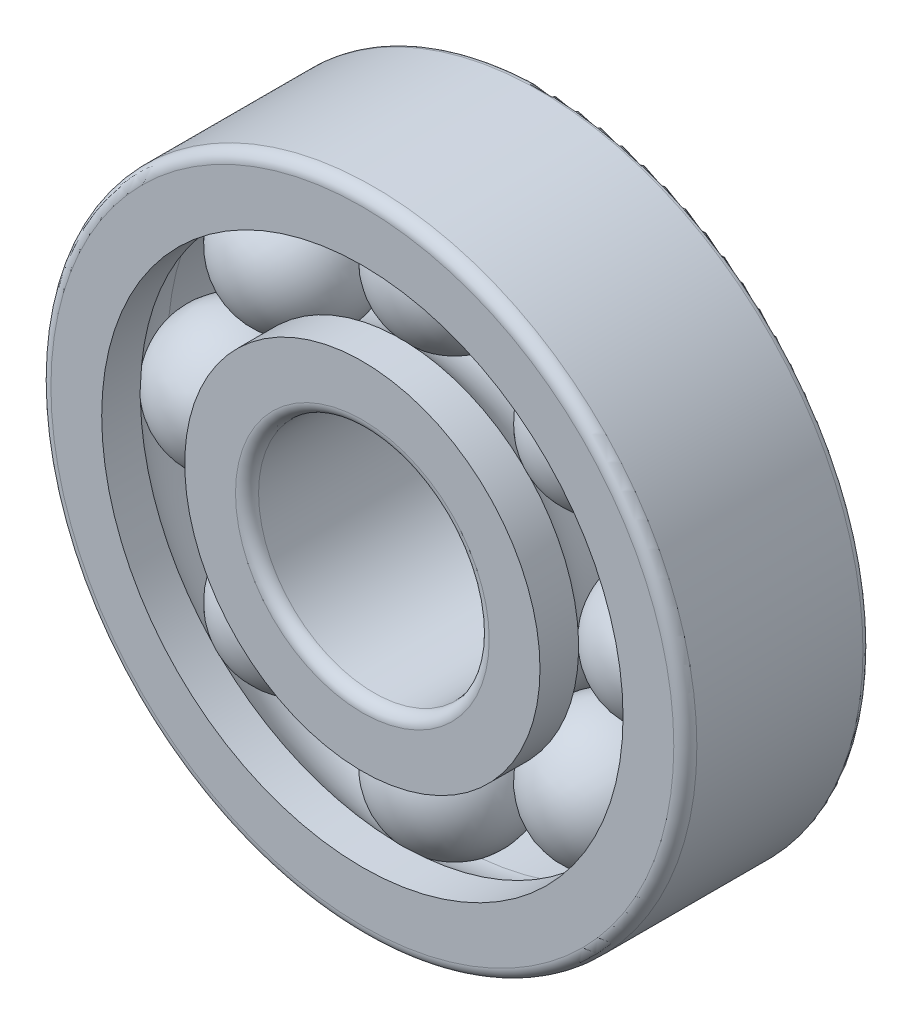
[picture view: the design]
ISO-10303-21;
HEADER;
FILE_DESCRIPTION(('STEP AP214'),'2;1');
FILE_NAME('part.step','',(''),(''),'','','');
FILE_SCHEMA(('AUTOMOTIVE_DESIGN { 1 0 10303 214 1 1 1 1 }'));
ENDSEC;
DATA;
#1=APPLICATION_CONTEXT('core data for automotive mechanical design processes');
#2=APPLICATION_PROTOCOL_DEFINITION('international standard','automotive_design',2000,#1);
#3=PRODUCT_CONTEXT('',#1,'mechanical');
#4=PRODUCT('Part','Part','',(#3));
#5=PRODUCT_RELATED_PRODUCT_CATEGORY('part','',(#4));
#6=PRODUCT_DEFINITION_FORMATION('','',#4);
#7=PRODUCT_DEFINITION_CONTEXT('part definition',#1,'design');
#8=PRODUCT_DEFINITION('design','',#6,#7);
#9=PRODUCT_DEFINITION_SHAPE('','',#8);
#10=(LENGTH_UNIT() NAMED_UNIT(*) SI_UNIT(.MILLI.,.METRE.));
#11=(NAMED_UNIT(*) PLANE_ANGLE_UNIT() SI_UNIT($,.RADIAN.));
#12=(NAMED_UNIT(*) SI_UNIT($,.STERADIAN.) SOLID_ANGLE_UNIT());
#13=UNCERTAINTY_MEASURE_WITH_UNIT(LENGTH_MEASURE(1.E-05),#10,'distance_accuracy_value','');
#14=(GEOMETRIC_REPRESENTATION_CONTEXT(3) GLOBAL_UNCERTAINTY_ASSIGNED_CONTEXT((#13)) GLOBAL_UNIT_ASSIGNED_CONTEXT((#10,
#11,#12)) REPRESENTATION_CONTEXT('',''));
#15=CARTESIAN_POINT('',(0.,0.,0.));
#16=DIRECTION('',(0.,0.,1.));
#17=DIRECTION('',(1.,0.,0.));
#18=AXIS2_PLACEMENT_3D('',#15,#16,#17);
#19=CARTESIAN_POINT('',(0.,0.,0.));
#20=DIRECTION('',(0.,0.,1.));
#21=DIRECTION('',(1.,0.,0.));
#22=AXIS2_PLACEMENT_3D('',#19,#20,#21);
#23=TOROIDAL_SURFACE('',#22,9.5,2.94);
#24=CARTESIAN_POINT('',(0.,0.,2.32456447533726));
#25=DIRECTION('',(0.,0.,1.));
#26=DIRECTION('',(1.,0.,0.));
#27=AXIS2_PLACEMENT_3D('',#24,#25,#26);
#28=CIRCLE('',#27,11.3);
#29=CARTESIAN_POINT('',(-0.264670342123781,11.2969,2.32456447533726));
#30=VERTEX_POINT('',#29);
#31=CARTESIAN_POINT('',(-7.80096440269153,8.17526479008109,2.32456447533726));
#32=VERTEX_POINT('',#31);
#33=EDGE_CURVE('E258',#30,#32,#28,.T.);
#34=ORIENTED_EDGE('',*,*,#33,.T.);
#35=CARTESIAN_POINT('',(-8.59785136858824,8.9905812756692,-0.0002));
#36=CARTESIAN_POINT('',(-8.59786091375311,8.99059098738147,0.0824851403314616));
#37=CARTESIAN_POINT('',(-8.59542029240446,8.98809530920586,0.165166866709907));
#38=CARTESIAN_POINT('',(-8.58568181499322,8.97813688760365,0.329940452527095));
#39=CARTESIAN_POINT('',(-8.57838412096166,8.97067430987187,0.412032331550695));
#40=CARTESIAN_POINT('',(-8.55898133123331,8.95083269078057,0.57499217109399));
#41=CARTESIAN_POINT('',(-8.5468795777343,8.93845706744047,0.655860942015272));
#42=CARTESIAN_POINT('',(-8.51796677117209,8.90888896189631,0.815832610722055));
#43=CARTESIAN_POINT('',(-8.50115585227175,8.89169661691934,0.894935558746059));
#44=CARTESIAN_POINT('',(-8.44378919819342,8.83302595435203,1.12887100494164));
#45=CARTESIAN_POINT('',(-8.39629702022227,8.7844514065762,1.2803513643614));
#46=CARTESIAN_POINT('',(-8.28425024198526,8.66983603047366,1.56959083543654));
#47=CARTESIAN_POINT('',(-8.21970879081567,8.60380866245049,1.70736040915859));
#48=CARTESIAN_POINT('',(-8.09678328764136,8.4780320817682,1.92723825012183));
#49=CARTESIAN_POINT('',(-8.04221252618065,8.42219015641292,2.01376675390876));
#50=CARTESIAN_POINT('',(-7.92635085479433,8.30361390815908,2.17693738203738));
#51=CARTESIAN_POINT('',(-7.86506421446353,8.2408839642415,2.2535857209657));
#52=CARTESIAN_POINT('',(-7.80078388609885,8.17507999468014,2.32476447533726));
#53=B_SPLINE_CURVE_WITH_KNOTS('',3,(#35,#36,#37,#38,#39,#40,#41,#42,#43,#44,#45,#46,#47,#48,#49,
#50,#51,#52),.UNSPECIFIED.,.F.,.F.,(4,2,2,2,2,2,2,2,4),(0.,0.24797496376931,0.495941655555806,
0.743736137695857,0.991523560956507,1.4870345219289,1.98216443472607,2.33102949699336,
2.67967404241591),.UNSPECIFIED.);
#54=CARTESIAN_POINT('',(-8.59785137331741,8.99058128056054,0.));
#55=VERTEX_POINT('',#54);
#56=EDGE_CURVE('E241',#55,#32,#53,.T.);
#57=ORIENTED_EDGE('',*,*,#56,.F.);
#58=CARTESIAN_POINT('',(0.,0.,0.));
#59=DIRECTION('',(0.,0.,1.));
#60=DIRECTION('',(1.,0.,0.));
#61=AXIS2_PLACEMENT_3D('',#58,#59,#60);
#62=CIRCLE('',#61,12.44);
#63=CARTESIAN_POINT('',(-0.277701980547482,12.4369,0.));
#64=VERTEX_POINT('',#63);
#65=EDGE_CURVE('E274',#64,#55,#62,.T.);
#66=ORIENTED_EDGE('',*,*,#65,.F.);
#67=CARTESIAN_POINT('',(-0.264667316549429,11.2966416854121,2.32476447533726));
#68=CARTESIAN_POINT('',(-0.265433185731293,11.3620290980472,2.27415420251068));
#69=CARTESIAN_POINT('',(-0.266170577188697,11.4252687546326,2.22077514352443));
#70=CARTESIAN_POINT('',(-0.267584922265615,11.5470290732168,2.10888477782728));
#71=CARTESIAN_POINT('',(-0.268261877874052,11.6055498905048,2.050373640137));
#72=CARTESIAN_POINT('',(-0.269551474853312,11.7174148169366,1.92866304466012));
#73=CARTESIAN_POINT('',(-0.270164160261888,11.7707624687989,1.86546684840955));
#74=CARTESIAN_POINT('',(-0.271322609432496,11.8719376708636,1.73482862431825));
#75=CARTESIAN_POINT('',(-0.271868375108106,11.9197653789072,1.66738671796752));
#76=CARTESIAN_POINT('',(-0.273401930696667,12.0545086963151,1.45928173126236));
#77=CARTESIAN_POINT('',(-0.27428614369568,12.1326988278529,1.31282376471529));
#78=CARTESIAN_POINT('',(-0.275758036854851,12.2632799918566,1.00899965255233));
#79=CARTESIAN_POINT('',(-0.276345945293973,12.3156908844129,0.851642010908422));
#80=CARTESIAN_POINT('',(-0.277087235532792,12.3818760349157,0.577980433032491));
#81=CARTESIAN_POINT('',(-0.277317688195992,12.4024912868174,0.463288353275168));
#82=CARTESIAN_POINT('',(-0.27762513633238,12.4300152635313,0.232345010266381));
#83=CARTESIAN_POINT('',(-0.277702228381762,12.4369326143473,0.11609477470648));
#84=CARTESIAN_POINT('',(-0.277701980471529,12.4368999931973,-0.000199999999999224));
#85=B_SPLINE_CURVE_WITH_KNOTS('',3,(#67,#68,#69,#70,#71,#72,#73,#74,#75,#76,#77,#78,#79,#80,#81,
#82,#83,#84),.UNSPECIFIED.,.F.,.F.,(4,2,2,2,2,2,2,2,4),(0.,0.247987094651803,0.495966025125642,
0.743773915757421,0.991574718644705,1.4871135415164,1.9822700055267,2.33108183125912,
2.67967392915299),.UNSPECIFIED.);
#86=EDGE_CURVE('E264',#30,#64,#85,.T.);
#87=ORIENTED_EDGE('',*,*,#86,.F.);
#88=EDGE_LOOP('',(#34,#57,#66,#87));
#89=FACE_BOUND('',#88,.T.);
#90=ADVANCED_FACE('F34',(#89),#23,.F.);
#91=CARTESIAN_POINT('',(0.,0.,0.));
#92=DIRECTION('',(0.,0.,1.));
#93=DIRECTION('',(1.,0.,0.));
#94=AXIS2_PLACEMENT_3D('',#91,#92,#93);
#95=TOROIDAL_SURFACE('',#94,9.5,2.94);
#96=CARTESIAN_POINT('',(0.,0.,2.32456447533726));
#97=DIRECTION('',(0.,0.,1.));
#98=DIRECTION('',(1.,0.,0.));
#99=AXIS2_PLACEMENT_3D('',#96,#97,#98);
#100=CIRCLE('',#99,7.7);
#101=CARTESIAN_POINT('',(-5.59701382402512,5.28804654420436,2.32456447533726));
#102=VERTEX_POINT('',#101);
#103=CARTESIAN_POINT('',(-7.6969,0.21847285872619,2.32456447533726));
#104=VERTEX_POINT('',#103);
#105=EDGE_CURVE('E305',#102,#104,#100,.T.);
#106=ORIENTED_EDGE('',*,*,#105,.F.);
#107=CARTESIAN_POINT('',(-5.59719907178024,5.28822660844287,-2.32476447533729));
#108=CARTESIAN_POINT('',(-5.55030713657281,5.24264670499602,-2.27415407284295));
#109=CARTESIAN_POINT('',(-5.50495120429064,5.19856819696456,-2.22077502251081));
#110=CARTESIAN_POINT('',(-5.417617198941,5.11370815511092,-2.10888540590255));
#111=CARTESIAN_POINT('',(-5.37563896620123,5.07292646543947,-2.05037508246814));
#112=CARTESIAN_POINT('',(-5.29538898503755,4.99497636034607,-1.92866518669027));
#113=CARTESIAN_POINT('',(-5.2571147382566,4.95780550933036,-1.86546882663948));
#114=CARTESIAN_POINT('',(-5.18452081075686,4.8873147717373,-1.73483020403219));
#115=CARTESIAN_POINT('',(-5.15020108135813,4.85399483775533,-1.66738799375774));
#116=CARTESIAN_POINT('',(-5.05352345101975,4.76014612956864,-1.45931209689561));
#117=CARTESIAN_POINT('',(-4.99741517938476,4.70569744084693,-1.31288063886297));
#118=CARTESIAN_POINT('',(-4.90367911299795,4.614750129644,-1.00908566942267));
#119=CARTESIAN_POINT('',(-4.8660464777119,4.578246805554,-0.851725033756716));
#120=CARTESIAN_POINT('',(-4.81027119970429,4.52415007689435,-0.530443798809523));
#121=CARTESIAN_POINT('',(-4.79212516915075,4.50655338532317,-0.366524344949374));
#122=CARTESIAN_POINT('',(-4.77584458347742,4.49076552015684,-0.0366933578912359));
#123=CARTESIAN_POINT('',(-4.77771919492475,4.49258323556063,0.129219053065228));
#124=CARTESIAN_POINT('',(-4.80143983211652,4.51558639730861,0.458305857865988));
#125=CARTESIAN_POINT('',(-4.82329472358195,4.53678044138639,0.621479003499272));
#126=CARTESIAN_POINT('',(-4.88635256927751,4.59794384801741,0.940223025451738));
#127=CARTESIAN_POINT('',(-4.92752699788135,4.63788552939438,1.09580473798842));
#128=CARTESIAN_POINT('',(-5.0051179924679,4.71317439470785,1.32701813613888));
#129=CARTESIAN_POINT('',(-5.03521272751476,4.74237952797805,1.40688828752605));
#130=CARTESIAN_POINT('',(-5.10053105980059,4.8057771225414,1.56244542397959));
#131=CARTESIAN_POINT('',(-5.13575390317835,4.83996885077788,1.63813302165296));
#132=CARTESIAN_POINT('',(-5.22336373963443,4.92502886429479,1.80867878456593));
#133=CARTESIAN_POINT('',(-5.27759567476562,4.97769294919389,1.90170534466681));
#134=CARTESIAN_POINT('',(-5.39374990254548,5.09051839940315,2.07781658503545));
#135=CARTESIAN_POINT('',(-5.45566783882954,5.15067551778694,2.16090684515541));
#136=CARTESIAN_POINT('',(-5.5458769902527,5.23834308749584,2.26802026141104));
#137=CARTESIAN_POINT('',(-5.57130760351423,5.26305959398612,2.29681885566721));
#138=CARTESIAN_POINT('',(-5.59719907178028,5.28822660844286,2.32476447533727));
#139=B_SPLINE_CURVE_WITH_KNOTS('',3,(#107,#108,#109,#110,#111,#112,#113,#114,#115,#116,#117,
#118,#119,#120,#121,#122,#123,#124,#125,#126,#127,#128,#129,#130,#131,#132,#133,#134,#135,#136,
#137,#138),.UNSPECIFIED.,.F.,.F.,(4,2,2,2,2,2,2,2,2,2,2,2,2,2,2,4),(0.,0.247992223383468,
0.495972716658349,0.743784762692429,0.991593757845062,1.48701674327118,1.98230986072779,
2.47751685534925,2.97295059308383,3.46860427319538,3.96352840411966,4.23382992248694,
4.50409174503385,4.86279314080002,5.22129214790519,5.35828916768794),.UNSPECIFIED.);
#140=CARTESIAN_POINT('',(-5.59701382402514,5.28804654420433,-2.32456447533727));
#141=VERTEX_POINT('',#140);
#142=EDGE_CURVE('E57',#141,#102,#139,.T.);
#143=ORIENTED_EDGE('',*,*,#142,.F.);
#144=CARTESIAN_POINT('',(0.,0.,-2.32456447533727));
#145=DIRECTION('',(0.,0.,1.));
#146=DIRECTION('',(1.,0.,0.));
#147=AXIS2_PLACEMENT_3D('',#144,#145,#146);
#148=CIRCLE('',#147,7.7);
#149=CARTESIAN_POINT('',(-7.6969,0.218472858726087,-2.32456447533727));
#150=VERTEX_POINT('',#149);
#151=EDGE_CURVE('E300',#141,#150,#148,.T.);
#152=ORIENTED_EDGE('',*,*,#151,.T.);
#153=CARTESIAN_POINT('',(-7.69715831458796,0.218476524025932,2.32476447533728));
#154=CARTESIAN_POINT('',(-7.63177085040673,0.217548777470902,2.27415407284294));
#155=CARTESIAN_POINT('',(-7.56853115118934,0.216645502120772,2.2207750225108));
#156=CARTESIAN_POINT('',(-7.44677157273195,0.214896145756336,2.10888540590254));
#157=CARTESIAN_POINT('',(-7.38825147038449,0.214050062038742,2.05037508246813));
#158=CARTESIAN_POINT('',(-7.27638711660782,0.212423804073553,1.92866518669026));
#159=CARTESIAN_POINT('',(-7.22303937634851,0.211643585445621,1.86546882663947));
#160=CARTESIAN_POINT('',(-7.12186323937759,0.210156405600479,1.73483020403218));
#161=CARTESIAN_POINT('',(-7.07403477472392,0.209449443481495,1.66738799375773));
#162=CARTESIAN_POINT('',(-6.9393123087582,0.207449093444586,1.4593120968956));
#163=CARTESIAN_POINT('',(-6.8611367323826,0.206275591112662,1.31288063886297));
#164=CARTESIAN_POINT('',(-6.73054586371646,0.204303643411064,1.00908566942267));
#165=CARTESIAN_POINT('',(-6.67812382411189,0.203505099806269,0.851725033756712));
#166=CARTESIAN_POINT('',(-6.60043258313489,0.202318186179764,0.530443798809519));
#167=CARTESIAN_POINT('',(-6.57515866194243,0.201929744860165,0.36652434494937));
#168=CARTESIAN_POINT('',(-6.55248284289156,0.201581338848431,0.0366933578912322));
#169=CARTESIAN_POINT('',(-6.55509371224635,0.20162157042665,-0.129219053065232));
#170=CARTESIAN_POINT('',(-6.58813242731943,0.202128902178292,-0.458305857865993));
#171=CARTESIAN_POINT('',(-6.61857262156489,0.202596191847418,-0.621479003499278));
#172=CARTESIAN_POINT('',(-6.7064103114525,0.203935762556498,-0.940223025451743));
#173=CARTESIAN_POINT('',(-6.76376806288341,0.204807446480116,-1.09580473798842));
#174=CARTESIAN_POINT('',(-6.87187044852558,0.206435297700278,-1.32701813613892));
#175=CARTESIAN_POINT('',(-6.91380178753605,0.207064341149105,-1.40688828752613));
#176=CARTESIAN_POINT('',(-7.00481769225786,0.208422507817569,-1.56244542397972));
#177=CARTESIAN_POINT('',(-7.05390120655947,0.209151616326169,-1.63813302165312));
#178=CARTESIAN_POINT('',(-7.1759972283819,0.210954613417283,-1.80867878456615));
#179=CARTESIAN_POINT('',(-7.2515841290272,0.212063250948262,-1.90170534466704));
#180=CARTESIAN_POINT('',(-7.41349721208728,0.214417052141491,-2.07781658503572));
#181=CARTESIAN_POINT('',(-7.49981731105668,0.215662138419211,-2.1609068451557));
#182=CARTESIAN_POINT('',(-7.62559514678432,0.217459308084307,-2.26802026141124));
#183=CARTESIAN_POINT('',(-7.66105451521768,0.217964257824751,-2.29681885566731));
#184=CARTESIAN_POINT('',(-7.69715831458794,0.218476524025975,-2.32476447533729));
#185=B_SPLINE_CURVE_WITH_KNOTS('',3,(#153,#154,#155,#156,#157,#158,#159,#160,#161,#162,#163,
#164,#165,#166,#167,#168,#169,#170,#171,#172,#173,#174,#175,#176,#177,#178,#179,#180,#181,#182,
#183,#184),.UNSPECIFIED.,.F.,.F.,(4,2,2,2,2,2,2,2,2,2,2,2,2,2,2,4),(0.,0.247992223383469,
0.495972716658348,0.743784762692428,0.991593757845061,1.48701674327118,1.98230986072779,
2.47751685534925,2.97295059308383,3.46860427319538,3.96352840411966,4.23382992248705,
4.50409174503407,4.86279314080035,5.22129214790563,5.35828916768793),.UNSPECIFIED.);
#186=EDGE_CURVE('E669',#104,#150,#185,.T.);
#187=ORIENTED_EDGE('',*,*,#186,.F.);
#188=EDGE_LOOP('',(#106,#143,#152,#187));
#189=FACE_BOUND('',#188,.T.);
#190=ADVANCED_FACE('F445',(#189),#95,.F.);
#191=CARTESIAN_POINT('',(-8.99058128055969,8.59785137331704,0.));
#192=VERTEX_POINT('',#191);
#193=CARTESIAN_POINT('',(-12.4369,0.277701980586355,0.));
#194=VERTEX_POINT('',#193);
#195=EDGE_CURVE('E280',#192,#194,#62,.T.);
#196=ORIENTED_EDGE('',*,*,#195,.F.);
#197=CARTESIAN_POINT('',(-8.17507999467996,7.80078388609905,2.32476447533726));
#198=CARTESIAN_POINT('',(-8.22185742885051,7.84647821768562,2.27415420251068));
#199=CARTESIAN_POINT('',(-8.26709603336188,7.89067399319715,2.22077514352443));
#200=CARTESIAN_POINT('',(-8.35419367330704,7.97577144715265,2.10888477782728));
#201=CARTESIAN_POINT('',(-8.39605281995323,8.01667323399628,2.050373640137));
#202=CARTESIAN_POINT('',(-8.47606515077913,8.09486179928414,1.92866304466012));
#203=CARTESIAN_POINT('',(-8.51422087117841,8.13215105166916,1.86546684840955));
#204=CARTESIAN_POINT('',(-8.58658168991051,8.20287357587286,1.73482862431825));
#205=CARTESIAN_POINT('',(-8.62078690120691,8.23630695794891,1.66738671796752));
#206=CARTESIAN_POINT('',(-8.71714920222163,8.3305004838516,1.45928173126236));
#207=CARTESIAN_POINT('',(-8.77306320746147,8.38516402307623,1.31282376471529));
#208=CARTESIAN_POINT('',(-8.86643881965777,8.47645806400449,1.00899965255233));
#209=CARTESIAN_POINT('',(-8.90391463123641,8.51310244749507,0.851642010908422));
#210=CARTESIAN_POINT('',(-8.95123877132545,8.55937824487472,0.577980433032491));
#211=CARTESIAN_POINT('',(-8.96597891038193,8.57379247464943,0.463288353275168));
#212=CARTESIAN_POINT('',(-8.98565869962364,8.59303746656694,0.232345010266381));
#213=CARTESIAN_POINT('',(-8.99060451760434,8.59787425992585,0.116094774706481));
#214=CARTESIAN_POINT('',(-8.99058127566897,8.59785136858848,-0.000199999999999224));
#215=B_SPLINE_CURVE_WITH_KNOTS('',3,(#197,#198,#199,#200,#201,#202,#203,#204,#205,#206,#207,
#208,#209,#210,#211,#212,#213,#214),.UNSPECIFIED.,.F.,.F.,(4,2,2,2,2,2,2,2,4),(0.,
0.247987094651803,0.495966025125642,0.743773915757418,0.991574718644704,1.4871135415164,
1.9822700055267,2.33108183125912,2.67967392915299),.UNSPECIFIED.);
#216=CARTESIAN_POINT('',(-8.17526479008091,7.80096440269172,2.32456447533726));
#217=VERTEX_POINT('',#216);
#218=EDGE_CURVE('E49',#217,#192,#215,.T.);
#219=ORIENTED_EDGE('',*,*,#218,.F.);
#220=CARTESIAN_POINT('',(-11.2969,0.264670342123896,2.32456447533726));
#221=VERTEX_POINT('',#220);
#222=EDGE_CURVE('E261',#217,#221,#28,.T.);
#223=ORIENTED_EDGE('',*,*,#222,.T.);
#224=CARTESIAN_POINT('',(-12.4368999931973,0.277701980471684,-0.0002));
#225=CARTESIAN_POINT('',(-12.4369136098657,0.277702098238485,0.082485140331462));
#226=CARTESIAN_POINT('',(-12.4334231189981,0.277663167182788,0.165166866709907));
#227=CARTESIAN_POINT('',(-12.4194953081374,0.277507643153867,0.329940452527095));
#228=CARTESIAN_POINT('',(-12.4090582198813,0.277391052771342,0.412032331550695));
#229=CARTESIAN_POINT('',(-12.3813082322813,0.277080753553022,0.57499217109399));
#230=CARTESIAN_POINT('',(-12.3640001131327,0.276887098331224,0.655860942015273));
#231=CARTESIAN_POINT('',(-12.3226478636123,0.276423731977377,0.815832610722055));
#232=CARTESIAN_POINT('',(-12.2986039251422,0.276154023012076,0.894935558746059));
#233=CARTESIAN_POINT('',(-12.2165531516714,0.275231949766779,1.12887100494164));
#234=CARTESIAN_POINT('',(-12.1486237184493,0.274466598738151,1.2803513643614));
#235=CARTESIAN_POINT('',(-11.9883493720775,0.272650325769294,1.56959083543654));
#236=CARTESIAN_POINT('',(-11.8960232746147,0.271599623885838,1.70736040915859));
#237=CARTESIAN_POINT('',(-11.7201643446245,0.269583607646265,1.92723825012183));
#238=CARTESIAN_POINT('',(-11.6420907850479,0.26868475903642,2.01376675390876));
#239=CARTESIAN_POINT('',(-11.4763181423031,0.26676526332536,2.17693738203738));
#240=CARTESIAN_POINT('',(-11.3886251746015,0.265744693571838,2.2535857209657));
#241=CARTESIAN_POINT('',(-11.2966416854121,0.264667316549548,2.32476447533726));
#242=B_SPLINE_CURVE_WITH_KNOTS('',3,(#224,#225,#226,#227,#228,#229,#230,#231,#232,#233,#234,
#235,#236,#237,#238,#239,#240,#241),.UNSPECIFIED.,.F.,.F.,(4,2,2,2,2,2,2,2,4),(0.,
0.24797496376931,0.495941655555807,0.743736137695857,0.991523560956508,1.4870345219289,
1.98216443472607,2.33102949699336,2.67967404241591),.UNSPECIFIED.);
#243=EDGE_CURVE('E676',#194,#221,#242,.T.);
#244=ORIENTED_EDGE('',*,*,#243,.F.);
#245=EDGE_LOOP('',(#196,#219,#223,#244));
#246=FACE_BOUND('',#245,.T.);
#247=ADVANCED_FACE('F446',(#246),#23,.F.);
#248=CARTESIAN_POINT('',(-7.6969,-0.218472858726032,2.32456447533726));
#249=VERTEX_POINT('',#248);
#250=CARTESIAN_POINT('',(-5.59701382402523,-5.28804654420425,2.32456447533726));
#251=VERTEX_POINT('',#250);
#252=EDGE_CURVE('E656',#249,#251,#100,.T.);
#253=ORIENTED_EDGE('',*,*,#252,.F.);
#254=CARTESIAN_POINT('',(-7.69715831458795,-0.218476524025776,-2.32476447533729));
#255=CARTESIAN_POINT('',(-7.63177085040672,-0.217548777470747,-2.27415407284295));
#256=CARTESIAN_POINT('',(-7.56853115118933,-0.216645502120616,-2.22077502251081));
#257=CARTESIAN_POINT('',(-7.44677157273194,-0.214896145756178,-2.10888540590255));
#258=CARTESIAN_POINT('',(-7.38825147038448,-0.214050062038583,-2.05037508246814));
#259=CARTESIAN_POINT('',(-7.27638711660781,-0.212423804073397,-1.92866518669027));
#260=CARTESIAN_POINT('',(-7.2230393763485,-0.211643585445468,-1.86546882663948));
#261=CARTESIAN_POINT('',(-7.12186323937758,-0.210156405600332,-1.73483020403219));
#262=CARTESIAN_POINT('',(-7.07403477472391,-0.209449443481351,-1.66738799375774));
#263=CARTESIAN_POINT('',(-6.93931230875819,-0.207449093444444,-1.45931209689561));
#264=CARTESIAN_POINT('',(-6.8611367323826,-0.206275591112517,-1.31288063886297));
#265=CARTESIAN_POINT('',(-6.73054586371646,-0.204303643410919,-1.00908566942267));
#266=CARTESIAN_POINT('',(-6.67812382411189,-0.203505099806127,-0.851725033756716));
#267=CARTESIAN_POINT('',(-6.60043258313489,-0.202318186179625,-0.530443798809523));
#268=CARTESIAN_POINT('',(-6.57515866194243,-0.201929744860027,-0.366524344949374));
#269=CARTESIAN_POINT('',(-6.55248284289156,-0.201581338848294,-0.0366933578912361));
#270=CARTESIAN_POINT('',(-6.55509371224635,-0.201621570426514,0.129219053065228));
#271=CARTESIAN_POINT('',(-6.58813242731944,-0.202128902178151,0.458305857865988));
#272=CARTESIAN_POINT('',(-6.6185726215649,-0.202596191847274,0.621479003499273));
#273=CARTESIAN_POINT('',(-6.70641031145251,-0.203935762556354,0.940223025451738));
#274=CARTESIAN_POINT('',(-6.76376806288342,-0.204807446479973,1.09580473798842));
#275=CARTESIAN_POINT('',(-6.87187044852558,-0.206435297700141,1.32701813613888));
#276=CARTESIAN_POINT('',(-6.91380178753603,-0.20706434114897,1.40688828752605));
#277=CARTESIAN_POINT('',(-7.0048176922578,-0.208422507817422,1.56244542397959));
#278=CARTESIAN_POINT('',(-7.05390120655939,-0.209151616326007,1.63813302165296));
#279=CARTESIAN_POINT('',(-7.17599722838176,-0.210954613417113,1.80867878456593));
#280=CARTESIAN_POINT('',(-7.25158412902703,-0.212063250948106,1.90170534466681));
#281=CARTESIAN_POINT('',(-7.41349721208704,-0.214417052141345,2.07781658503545));
#282=CARTESIAN_POINT('',(-7.49981731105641,-0.21566213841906,2.16090684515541));
#283=CARTESIAN_POINT('',(-7.62559514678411,-0.217459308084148,2.26802026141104));
#284=CARTESIAN_POINT('',(-7.66105451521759,-0.217964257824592,2.29681885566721));
#285=CARTESIAN_POINT('',(-7.69715831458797,-0.218476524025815,2.32476447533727));
#286=B_SPLINE_CURVE_WITH_KNOTS('',3,(#254,#255,#256,#257,#258,#259,#260,#261,#262,#263,#264,
#265,#266,#267,#268,#269,#270,#271,#272,#273,#274,#275,#276,#277,#278,#279,#280,#281,#282,#283,
#284,#285),.UNSPECIFIED.,.F.,.F.,(4,2,2,2,2,2,2,2,2,2,2,2,2,2,2,4),(0.,0.247992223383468,
0.495972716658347,0.743784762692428,0.991593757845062,1.48701674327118,1.98230986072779,
2.47751685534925,2.97295059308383,3.46860427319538,3.96352840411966,4.23382992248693,
4.50409174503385,4.86279314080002,5.22129214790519,5.35828916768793),.UNSPECIFIED.);
#287=CARTESIAN_POINT('',(-7.6969,-0.21847285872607,-2.32456447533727));
#288=VERTEX_POINT('',#287);
#289=EDGE_CURVE('E672',#288,#249,#286,.T.);
#290=ORIENTED_EDGE('',*,*,#289,.F.);
#291=CARTESIAN_POINT('',(-5.59701382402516,-5.28804654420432,-2.32456447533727));
#292=VERTEX_POINT('',#291);
#293=EDGE_CURVE('E934',#288,#292,#148,.T.);
#294=ORIENTED_EDGE('',*,*,#293,.T.);
#295=CARTESIAN_POINT('',(-5.59719907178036,-5.28822660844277,2.32476447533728));
#296=CARTESIAN_POINT('',(-5.55030713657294,-5.24264670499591,2.27415407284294));
#297=CARTESIAN_POINT('',(-5.50495120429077,-5.19856819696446,2.2207750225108));
#298=CARTESIAN_POINT('',(-5.41761719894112,-5.11370815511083,2.10888540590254));
#299=CARTESIAN_POINT('',(-5.37563896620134,-5.07292646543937,2.05037508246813));
#300=CARTESIAN_POINT('',(-5.29538898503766,-4.99497636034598,1.92866518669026));
#301=CARTESIAN_POINT('',(-5.2571147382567,-4.95780550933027,1.86546882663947));
#302=CARTESIAN_POINT('',(-5.18452081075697,-4.88731477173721,1.73483020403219));
#303=CARTESIAN_POINT('',(-5.15020108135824,-4.85399483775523,1.66738799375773));
#304=CARTESIAN_POINT('',(-5.05352345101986,-4.76014612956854,1.4593120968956));
#305=CARTESIAN_POINT('',(-4.99741517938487,-4.70569744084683,1.31288063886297));
#306=CARTESIAN_POINT('',(-4.90367911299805,-4.61475012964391,1.00908566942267));
#307=CARTESIAN_POINT('',(-4.86604647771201,-4.57824680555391,0.851725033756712));
#308=CARTESIAN_POINT('',(-4.81027119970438,-4.52415007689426,0.530443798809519));
#309=CARTESIAN_POINT('',(-4.79212516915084,-4.50655338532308,0.36652434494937));
#310=CARTESIAN_POINT('',(-4.7758445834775,-4.49076552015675,0.0366933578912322));
#311=CARTESIAN_POINT('',(-4.77771919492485,-4.49258323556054,-0.129219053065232));
#312=CARTESIAN_POINT('',(-4.80143983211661,-4.5155863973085,-0.458305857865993));
#313=CARTESIAN_POINT('',(-4.82329472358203,-4.53678044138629,-0.621479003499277));
#314=CARTESIAN_POINT('',(-4.88635256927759,-4.59794384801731,-0.940223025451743));
#315=CARTESIAN_POINT('',(-4.92752699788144,-4.63788552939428,-1.09580473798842));
#316=CARTESIAN_POINT('',(-5.005117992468,-4.71317439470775,-1.32701813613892));
#317=CARTESIAN_POINT('',(-5.03521272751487,-4.74237952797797,-1.40688828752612));
#318=CARTESIAN_POINT('',(-5.10053105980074,-4.80577712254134,-1.56244542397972));
#319=CARTESIAN_POINT('',(-5.13575390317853,-4.83996885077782,-1.63813302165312));
#320=CARTESIAN_POINT('',(-5.22336373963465,-4.92502886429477,-1.80867878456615));
#321=CARTESIAN_POINT('',(-5.27759567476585,-4.9776929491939,-1.90170534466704));
#322=CARTESIAN_POINT('',(-5.39374990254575,-5.09051839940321,-2.07781658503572));
#323=CARTESIAN_POINT('',(-5.45566783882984,-5.15067551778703,-2.1609068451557));
#324=CARTESIAN_POINT('',(-5.54587699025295,-5.23834308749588,-2.26802026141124));
#325=CARTESIAN_POINT('',(-5.57130760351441,-5.26305959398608,-2.29681885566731));
#326=CARTESIAN_POINT('',(-5.59719907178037,-5.28822660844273,-2.32476447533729));
#327=B_SPLINE_CURVE_WITH_KNOTS('',3,(#295,#296,#297,#298,#299,#300,#301,#302,#303,#304,#305,
#306,#307,#308,#309,#310,#311,#312,#313,#314,#315,#316,#317,#318,#319,#320,#321,#322,#323,#324,
#325,#326),.UNSPECIFIED.,.F.,.F.,(4,2,2,2,2,2,2,2,2,2,2,2,2,2,2,4),(0.,0.247992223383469,
0.495972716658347,0.743784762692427,0.991593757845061,1.48701674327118,1.98230986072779,
2.47751685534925,2.97295059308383,3.46860427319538,3.96352840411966,4.23382992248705,
4.50409174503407,4.86279314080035,5.22129214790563,5.35828916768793),.UNSPECIFIED.);
#328=EDGE_CURVE('E740',#251,#292,#327,.T.);
#329=ORIENTED_EDGE('',*,*,#328,.F.);
#330=EDGE_LOOP('',(#253,#290,#294,#329));
#331=FACE_BOUND('',#330,.T.);
#332=ADVANCED_FACE('F451',(#331),#95,.F.);
#333=CARTESIAN_POINT('',(-12.4368999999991,-0.277701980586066,0.));
#334=VERTEX_POINT('',#333);
#335=CARTESIAN_POINT('',(-8.99058128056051,-8.59785137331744,0.));
#336=VERTEX_POINT('',#335);
#337=EDGE_CURVE('E283',#334,#336,#62,.T.);
#338=ORIENTED_EDGE('',*,*,#337,.F.);
#339=CARTESIAN_POINT('',(-11.2966416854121,-0.264667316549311,2.32476447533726));
#340=CARTESIAN_POINT('',(-11.3620290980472,-0.265433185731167,2.27415420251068));
#341=CARTESIAN_POINT('',(-11.4252687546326,-0.266170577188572,2.22077514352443));
#342=CARTESIAN_POINT('',(-11.5470290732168,-0.267584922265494,2.10888477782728));
#343=CARTESIAN_POINT('',(-11.6055498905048,-0.268261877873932,2.050373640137));
#344=CARTESIAN_POINT('',(-11.7174148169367,-0.269551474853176,1.92866304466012));
#345=CARTESIAN_POINT('',(-11.7707624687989,-0.270164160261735,1.86546684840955));
#346=CARTESIAN_POINT('',(-11.8719376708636,-0.271322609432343,1.73482862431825));
#347=CARTESIAN_POINT('',(-11.9197653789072,-0.271868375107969,1.66738671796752));
#348=CARTESIAN_POINT('',(-12.0545086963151,-0.273401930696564,1.45928173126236));
#349=CARTESIAN_POINT('',(-12.1326988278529,-0.274286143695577,1.31282376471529));
#350=CARTESIAN_POINT('',(-12.2632799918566,-0.275758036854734,1.00899965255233));
#351=CARTESIAN_POINT('',(-12.3156908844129,-0.276345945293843,0.851642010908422));
#352=CARTESIAN_POINT('',(-12.3818760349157,-0.277087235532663,0.577980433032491));
#353=CARTESIAN_POINT('',(-12.4024912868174,-0.27731768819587,0.463288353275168));
#354=CARTESIAN_POINT('',(-12.4300152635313,-0.277625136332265,0.232345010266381));
#355=CARTESIAN_POINT('',(-12.4369326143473,-0.277702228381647,0.11609477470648));
#356=CARTESIAN_POINT('',(-12.4368999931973,-0.277701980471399,-0.000199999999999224));
#357=B_SPLINE_CURVE_WITH_KNOTS('',3,(#339,#340,#341,#342,#343,#344,#345,#346,#347,#348,#349,
#350,#351,#352,#353,#354,#355,#356),.UNSPECIFIED.,.F.,.F.,(4,2,2,2,2,2,2,2,4),(0.,
0.247987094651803,0.495966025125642,0.74377391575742,0.991574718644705,1.4871135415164,
1.9822700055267,2.33108183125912,2.67967392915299),.UNSPECIFIED.);
#358=CARTESIAN_POINT('',(-11.2969,-0.264670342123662,2.32456447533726));
#359=VERTEX_POINT('',#358);
#360=EDGE_CURVE('E678',#359,#334,#357,.T.);
#361=ORIENTED_EDGE('',*,*,#360,.F.);
#362=CARTESIAN_POINT('',(-8.17526479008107,-7.80096440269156,2.32456447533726));
#363=VERTEX_POINT('',#362);
#364=EDGE_CURVE('E271',#359,#363,#28,.T.);
#365=ORIENTED_EDGE('',*,*,#364,.T.);
#366=CARTESIAN_POINT('',(-8.99058127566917,-8.59785136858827,-0.0002));
#367=CARTESIAN_POINT('',(-8.99059098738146,-8.59786091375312,0.0824851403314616));
#368=CARTESIAN_POINT('',(-8.98809530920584,-8.59542029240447,0.165166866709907));
#369=CARTESIAN_POINT('',(-8.97813688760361,-8.58568181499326,0.329940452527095));
#370=CARTESIAN_POINT('',(-8.97067430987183,-8.57838412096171,0.412032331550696));
#371=CARTESIAN_POINT('',(-8.95083269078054,-8.55898133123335,0.574992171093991));
#372=CARTESIAN_POINT('',(-8.93845706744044,-8.54687957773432,0.655860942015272));
#373=CARTESIAN_POINT('',(-8.90888896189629,-8.51796677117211,0.815832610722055));
#374=CARTESIAN_POINT('',(-8.89169661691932,-8.50115585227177,0.894935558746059));
#375=CARTESIAN_POINT('',(-8.83302595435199,-8.44378919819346,1.12887100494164));
#376=CARTESIAN_POINT('',(-8.78445140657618,-8.39629702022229,1.2803513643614));
#377=CARTESIAN_POINT('',(-8.66983603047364,-8.28425024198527,1.56959083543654));
#378=CARTESIAN_POINT('',(-8.60380866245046,-8.2197087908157,1.70736040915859));
#379=CARTESIAN_POINT('',(-8.47803208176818,-8.09678328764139,1.92723825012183));
#380=CARTESIAN_POINT('',(-8.42219015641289,-8.04221252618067,2.01376675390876));
#381=CARTESIAN_POINT('',(-8.30361390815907,-7.92635085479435,2.17693738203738));
#382=CARTESIAN_POINT('',(-8.24088396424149,-7.86506421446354,2.2535857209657));
#383=CARTESIAN_POINT('',(-8.17507999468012,-7.80078388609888,2.32476447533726));
#384=B_SPLINE_CURVE_WITH_KNOTS('',3,(#366,#367,#368,#369,#370,#371,#372,#373,#374,#375,#376,
#377,#378,#379,#380,#381,#382,#383),.UNSPECIFIED.,.F.,.F.,(4,2,2,2,2,2,2,2,4),(0.,
0.24797496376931,0.495941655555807,0.743736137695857,0.991523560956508,1.4870345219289,
1.98216443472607,2.33102949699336,2.67967404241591),.UNSPECIFIED.);
#385=EDGE_CURVE('E673',#336,#363,#384,.T.);
#386=ORIENTED_EDGE('',*,*,#385,.F.);
#387=EDGE_LOOP('',(#338,#361,#365,#386));
#388=FACE_BOUND('',#387,.T.);
#389=ADVANCED_FACE('F454',(#388),#23,.F.);
#390=CARTESIAN_POINT('',(-5.28804654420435,-5.59701382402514,2.32456447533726));
#391=VERTEX_POINT('',#390);
#392=CARTESIAN_POINT('',(-0.218472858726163,-7.6969,2.32456447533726));
#393=VERTEX_POINT('',#392);
#394=EDGE_CURVE('E652',#391,#393,#100,.T.);
#395=ORIENTED_EDGE('',*,*,#394,.F.);
#396=CARTESIAN_POINT('',(-5.28822660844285,-5.59719907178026,-2.32476447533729));
#397=CARTESIAN_POINT('',(-5.242646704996,-5.55030713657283,-2.27415407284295));
#398=CARTESIAN_POINT('',(-5.19856819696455,-5.50495120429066,-2.22077502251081));
#399=CARTESIAN_POINT('',(-5.11370815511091,-5.41761719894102,-2.10888540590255));
#400=CARTESIAN_POINT('',(-5.07292646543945,-5.37563896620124,-2.05037508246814));
#401=CARTESIAN_POINT('',(-4.99497636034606,-5.29538898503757,-1.92866518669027));
#402=CARTESIAN_POINT('',(-4.95780550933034,-5.25711473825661,-1.86546882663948));
#403=CARTESIAN_POINT('',(-4.88731477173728,-5.18452081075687,-1.73483020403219));
#404=CARTESIAN_POINT('',(-4.85399483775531,-5.15020108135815,-1.66738799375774));
#405=CARTESIAN_POINT('',(-4.76014612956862,-5.05352345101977,-1.45931209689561));
#406=CARTESIAN_POINT('',(-4.70569744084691,-4.99741517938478,-1.31288063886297));
#407=CARTESIAN_POINT('',(-4.61475012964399,-4.90367911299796,-1.00908566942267));
#408=CARTESIAN_POINT('',(-4.57824680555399,-4.86604647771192,-0.851725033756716));
#409=CARTESIAN_POINT('',(-4.52415007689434,-4.8102711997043,-0.530443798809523));
#410=CARTESIAN_POINT('',(-4.50655338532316,-4.79212516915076,-0.366524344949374));
#411=CARTESIAN_POINT('',(-4.49076552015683,-4.77584458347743,-0.0366933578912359));
#412=CARTESIAN_POINT('',(-4.49258323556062,-4.77771919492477,0.129219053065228));
#413=CARTESIAN_POINT('',(-4.51558639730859,-4.80143983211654,0.458305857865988));
#414=CARTESIAN_POINT('',(-4.53678044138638,-4.82329472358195,0.621479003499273));
#415=CARTESIAN_POINT('',(-4.5979438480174,-4.88635256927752,0.940223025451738));
#416=CARTESIAN_POINT('',(-4.63788552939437,-4.92752699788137,1.09580473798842));
#417=CARTESIAN_POINT('',(-4.71317439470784,-5.00511799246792,1.32701813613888));
#418=CARTESIAN_POINT('',(-4.74237952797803,-5.03521272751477,1.40688828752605));
#419=CARTESIAN_POINT('',(-4.80577712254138,-5.10053105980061,1.56244542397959));
#420=CARTESIAN_POINT('',(-4.83996885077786,-5.13575390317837,1.63813302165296));
#421=CARTESIAN_POINT('',(-4.92502886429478,-5.22336373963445,1.80867878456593));
#422=CARTESIAN_POINT('',(-4.97769294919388,-5.27759567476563,1.90170534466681));
#423=CARTESIAN_POINT('',(-5.09051839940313,-5.39374990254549,2.07781658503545));
#424=CARTESIAN_POINT('',(-5.15067551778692,-5.45566783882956,2.16090684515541));
#425=CARTESIAN_POINT('',(-5.23834308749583,-5.54587699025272,2.26802026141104));
#426=CARTESIAN_POINT('',(-5.2630595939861,-5.57130760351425,2.29681885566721));
#427=CARTESIAN_POINT('',(-5.28822660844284,-5.5971990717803,2.32476447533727));
#428=B_SPLINE_CURVE_WITH_KNOTS('',3,(#396,#397,#398,#399,#400,#401,#402,#403,#404,#405,#406,
#407,#408,#409,#410,#411,#412,#413,#414,#415,#416,#417,#418,#419,#420,#421,#422,#423,#424,#425,
#426,#427),.UNSPECIFIED.,.F.,.F.,(4,2,2,2,2,2,2,2,2,2,2,2,2,2,2,4),(0.,0.247992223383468,
0.495972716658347,0.743784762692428,0.991593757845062,1.48701674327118,1.98230986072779,
2.47751685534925,2.97295059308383,3.46860427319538,3.96352840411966,4.23382992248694,
4.50409174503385,4.86279314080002,5.22129214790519,5.35828916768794),.UNSPECIFIED.);
#429=CARTESIAN_POINT('',(-5.28804654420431,-5.59701382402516,-2.32456447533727));
#430=VERTEX_POINT('',#429);
#431=EDGE_CURVE('E771',#430,#391,#428,.T.);
#432=ORIENTED_EDGE('',*,*,#431,.F.);
#433=CARTESIAN_POINT('',(-0.218472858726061,-7.6969,-2.32456447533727));
#434=VERTEX_POINT('',#433);
#435=EDGE_CURVE('E924',#430,#434,#148,.T.);
#436=ORIENTED_EDGE('',*,*,#435,.T.);
#437=CARTESIAN_POINT('',(-0.218476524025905,-7.69715831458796,2.32476447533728));
#438=CARTESIAN_POINT('',(-0.217548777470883,-7.63177085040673,2.27415407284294));
#439=CARTESIAN_POINT('',(-0.216645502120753,-7.56853115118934,2.2207750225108));
#440=CARTESIAN_POINT('',(-0.214896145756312,-7.44677157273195,2.10888540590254));
#441=CARTESIAN_POINT('',(-0.214050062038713,-7.38825147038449,2.05037508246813));
#442=CARTESIAN_POINT('',(-0.212423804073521,-7.27638711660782,1.92866518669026));
#443=CARTESIAN_POINT('',(-0.211643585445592,-7.22303937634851,1.86546882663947));
#444=CARTESIAN_POINT('',(-0.210156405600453,-7.12186323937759,1.73483020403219));
#445=CARTESIAN_POINT('',(-0.20944944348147,-7.07403477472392,1.66738799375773));
#446=CARTESIAN_POINT('',(-0.207449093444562,-6.9393123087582,1.4593120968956));
#447=CARTESIAN_POINT('',(-0.206275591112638,-6.8611367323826,1.31288063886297));
#448=CARTESIAN_POINT('',(-0.204303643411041,-6.73054586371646,1.00908566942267));
#449=CARTESIAN_POINT('',(-0.203505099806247,-6.67812382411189,0.851725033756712));
#450=CARTESIAN_POINT('',(-0.202318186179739,-6.60043258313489,0.530443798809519));
#451=CARTESIAN_POINT('',(-0.201929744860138,-6.57515866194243,0.36652434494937));
#452=CARTESIAN_POINT('',(-0.201581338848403,-6.55248284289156,0.0366933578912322));
#453=CARTESIAN_POINT('',(-0.201621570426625,-6.55509371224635,-0.129219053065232));
#454=CARTESIAN_POINT('',(-0.202128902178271,-6.58813242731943,-0.458305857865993));
#455=CARTESIAN_POINT('',(-0.2025961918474,-6.61857262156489,-0.621479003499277));
#456=CARTESIAN_POINT('',(-0.203935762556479,-6.7064103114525,-0.940223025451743));
#457=CARTESIAN_POINT('',(-0.204807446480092,-6.76376806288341,-1.09580473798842));
#458=CARTESIAN_POINT('',(-0.206435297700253,-6.87187044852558,-1.32701813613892));
#459=CARTESIAN_POINT('',(-0.207064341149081,-6.91380178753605,-1.40688828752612));
#460=CARTESIAN_POINT('',(-0.208422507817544,-7.00481769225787,-1.56244542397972));
#461=CARTESIAN_POINT('',(-0.209151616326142,-7.05390120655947,-1.63813302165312));
#462=CARTESIAN_POINT('',(-0.210954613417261,-7.1759972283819,-1.80867878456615));
#463=CARTESIAN_POINT('',(-0.212063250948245,-7.2515841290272,-1.90170534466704));
#464=CARTESIAN_POINT('',(-0.214417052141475,-7.41349721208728,-2.07781658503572));
#465=CARTESIAN_POINT('',(-0.215662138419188,-7.49981731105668,-2.1609068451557));
#466=CARTESIAN_POINT('',(-0.217459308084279,-7.62559514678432,-2.26802026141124));
#467=CARTESIAN_POINT('',(-0.217964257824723,-7.66105451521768,-2.29681885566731));
#468=CARTESIAN_POINT('',(-0.218476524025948,-7.69715831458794,-2.32476447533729));
#469=B_SPLINE_CURVE_WITH_KNOTS('',3,(#437,#438,#439,#440,#441,#442,#443,#444,#445,#446,#447,
#448,#449,#450,#451,#452,#453,#454,#455,#456,#457,#458,#459,#460,#461,#462,#463,#464,#465,#466,
#467,#468),.UNSPECIFIED.,.F.,.F.,(4,2,2,2,2,2,2,2,2,2,2,2,2,2,2,4),(0.,0.247992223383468,
0.495972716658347,0.743784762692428,0.991593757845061,1.48701674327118,1.98230986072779,
2.47751685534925,2.97295059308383,3.46860427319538,3.96352840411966,4.23382992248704,
4.50409174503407,4.86279314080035,5.22129214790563,5.35828916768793),.UNSPECIFIED.);
#470=EDGE_CURVE('E805',#393,#434,#469,.T.);
#471=ORIENTED_EDGE('',*,*,#470,.F.);
#472=EDGE_LOOP('',(#395,#432,#436,#471));
#473=FACE_BOUND('',#472,.T.);
#474=ADVANCED_FACE('F459',(#473),#95,.F.);
#475=CARTESIAN_POINT('',(-8.59785137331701,-8.99058128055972,0.));
#476=VERTEX_POINT('',#475);
#477=CARTESIAN_POINT('',(-0.277701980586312,-12.4369,0.));
#478=VERTEX_POINT('',#477);
#479=EDGE_CURVE('E948',#476,#478,#62,.T.);
#480=ORIENTED_EDGE('',*,*,#479,.F.);
#481=CARTESIAN_POINT('',(-7.80078388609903,-8.17507999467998,2.32476447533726));
#482=CARTESIAN_POINT('',(-7.84647821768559,-8.22185742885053,2.27415420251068));
#483=CARTESIAN_POINT('',(-7.89067399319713,-8.2670960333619,2.22077514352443));
#484=CARTESIAN_POINT('',(-7.97577144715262,-8.35419367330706,2.10888477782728));
#485=CARTESIAN_POINT('',(-8.01667323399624,-8.39605281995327,2.050373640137));
#486=CARTESIAN_POINT('',(-8.09486179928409,-8.47606515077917,1.92866304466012));
#487=CARTESIAN_POINT('',(-8.13215105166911,-8.51422087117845,1.86546684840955));
#488=CARTESIAN_POINT('',(-8.20287357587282,-8.58658168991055,1.73482862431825));
#489=CARTESIAN_POINT('',(-8.23630695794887,-8.62078690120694,1.66738671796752));
#490=CARTESIAN_POINT('',(-8.33050048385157,-8.71714920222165,1.45928173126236));
#491=CARTESIAN_POINT('',(-8.3851640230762,-8.7730632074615,1.31282376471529));
#492=CARTESIAN_POINT('',(-8.47645806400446,-8.8664388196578,1.00899965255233));
#493=CARTESIAN_POINT('',(-8.51310244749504,-8.90391463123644,0.851642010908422));
#494=CARTESIAN_POINT('',(-8.5593782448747,-8.95123877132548,0.577980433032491));
#495=CARTESIAN_POINT('',(-8.5737924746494,-8.96597891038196,0.463288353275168));
#496=CARTESIAN_POINT('',(-8.59303746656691,-8.98565869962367,0.232345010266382));
#497=CARTESIAN_POINT('',(-8.59787425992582,-8.99060451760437,0.116094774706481));
#498=CARTESIAN_POINT('',(-8.59785136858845,-8.990581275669,-0.000199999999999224));
#499=B_SPLINE_CURVE_WITH_KNOTS('',3,(#481,#482,#483,#484,#485,#486,#487,#488,#489,#490,#491,
#492,#493,#494,#495,#496,#497,#498),.UNSPECIFIED.,.F.,.F.,(4,2,2,2,2,2,2,2,4),(0.,
0.247987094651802,0.495966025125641,0.74377391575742,0.991574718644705,1.4871135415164,
1.9822700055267,2.33108183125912,2.67967392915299),.UNSPECIFIED.);
#500=CARTESIAN_POINT('',(-7.80096440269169,-8.17526479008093,2.32456447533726));
#501=VERTEX_POINT('',#500);
#502=EDGE_CURVE('E753',#501,#476,#499,.T.);
#503=ORIENTED_EDGE('',*,*,#502,.F.);
#504=CARTESIAN_POINT('',(-0.264670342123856,-11.2969,2.32456447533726));
#505=VERTEX_POINT('',#504);
#506=EDGE_CURVE('E943',#501,#505,#28,.T.);
#507=ORIENTED_EDGE('',*,*,#506,.T.);
#508=CARTESIAN_POINT('',(-0.27770198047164,-12.4368999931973,-0.0002));
#509=CARTESIAN_POINT('',(-0.277702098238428,-12.4369136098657,0.082485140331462));
#510=CARTESIAN_POINT('',(-0.277663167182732,-12.4334231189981,0.165166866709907));
#511=CARTESIAN_POINT('',(-0.277507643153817,-12.4194953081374,0.329940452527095));
#512=CARTESIAN_POINT('',(-0.277391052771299,-12.4090582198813,0.412032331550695));
#513=CARTESIAN_POINT('',(-0.277080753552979,-12.3813082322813,0.57499217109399));
#514=CARTESIAN_POINT('',(-0.276887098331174,-12.3640001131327,0.655860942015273));
#515=CARTESIAN_POINT('',(-0.276423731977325,-12.3226478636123,0.815832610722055));
#516=CARTESIAN_POINT('',(-0.276154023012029,-12.2986039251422,0.894935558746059));
#517=CARTESIAN_POINT('',(-0.275231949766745,-12.2165531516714,1.12887100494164));
#518=CARTESIAN_POINT('',(-0.274466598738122,-12.1486237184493,1.2803513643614));
#519=CARTESIAN_POINT('',(-0.272650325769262,-11.9883493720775,1.56959083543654));
#520=CARTESIAN_POINT('',(-0.271599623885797,-11.8960232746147,1.70736040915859));
#521=CARTESIAN_POINT('',(-0.269583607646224,-11.7201643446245,1.92723825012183));
#522=CARTESIAN_POINT('',(-0.268684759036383,-11.6420907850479,2.01376675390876));
#523=CARTESIAN_POINT('',(-0.266765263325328,-11.4763181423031,2.17693738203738));
#524=CARTESIAN_POINT('',(-0.265744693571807,-11.3886251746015,2.2535857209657));
#525=CARTESIAN_POINT('',(-0.264667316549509,-11.2966416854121,2.32476447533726));
#526=B_SPLINE_CURVE_WITH_KNOTS('',3,(#508,#509,#510,#511,#512,#513,#514,#515,#516,#517,#518,
#519,#520,#521,#522,#523,#524,#525),.UNSPECIFIED.,.F.,.F.,(4,2,2,2,2,2,2,2,4),(0.,
0.24797496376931,0.495941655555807,0.743736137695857,0.991523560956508,1.4870345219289,
1.98216443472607,2.33102949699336,2.67967404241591),.UNSPECIFIED.);
#527=EDGE_CURVE('E797',#478,#505,#526,.T.);
#528=ORIENTED_EDGE('',*,*,#527,.F.);
#529=EDGE_LOOP('',(#480,#503,#507,#528));
#530=FACE_BOUND('',#529,.T.);
#531=ADVANCED_FACE('F463',(#530),#23,.F.);
#532=CARTESIAN_POINT('',(0.218472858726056,-7.69690000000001,2.32456447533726));
#533=VERTEX_POINT('',#532);
#534=CARTESIAN_POINT('',(5.28804654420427,-5.59701382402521,2.32456447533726));
#535=VERTEX_POINT('',#534);
#536=EDGE_CURVE('E649',#533,#535,#100,.T.);
#537=ORIENTED_EDGE('',*,*,#536,.F.);
#538=CARTESIAN_POINT('',(0.218476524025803,-7.69715831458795,-2.32476447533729));
#539=CARTESIAN_POINT('',(0.217548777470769,-7.63177085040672,-2.27415407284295));
#540=CARTESIAN_POINT('',(0.216645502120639,-7.56853115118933,-2.22077502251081));
#541=CARTESIAN_POINT('',(0.214896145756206,-7.44677157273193,-2.10888540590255));
#542=CARTESIAN_POINT('',(0.214050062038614,-7.38825147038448,-2.05037508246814));
#543=CARTESIAN_POINT('',(0.212423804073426,-7.27638711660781,-1.92866518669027));
#544=CARTESIAN_POINT('',(0.211643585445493,-7.2230393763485,-1.86546882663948));
#545=CARTESIAN_POINT('',(0.210156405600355,-7.12186323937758,-1.73483020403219));
#546=CARTESIAN_POINT('',(0.209449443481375,-7.07403477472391,-1.66738799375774));
#547=CARTESIAN_POINT('',(0.20744909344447,-6.93931230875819,-1.45931209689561));
#548=CARTESIAN_POINT('',(0.206275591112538,-6.8611367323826,-1.31288063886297));
#549=CARTESIAN_POINT('',(0.204303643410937,-6.73054586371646,-1.00908566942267));
#550=CARTESIAN_POINT('',(0.203505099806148,-6.67812382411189,-0.851725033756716));
#551=CARTESIAN_POINT('',(0.20231818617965,-6.60043258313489,-0.530443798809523));
#552=CARTESIAN_POINT('',(0.201929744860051,-6.57515866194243,-0.366524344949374));
#553=CARTESIAN_POINT('',(0.201581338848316,-6.55248284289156,-0.036693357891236));
#554=CARTESIAN_POINT('',(0.201621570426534,-6.55509371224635,0.129219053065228));
#555=CARTESIAN_POINT('',(0.202128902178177,-6.58813242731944,0.458305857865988));
#556=CARTESIAN_POINT('',(0.202596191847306,-6.6185726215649,0.621479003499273));
#557=CARTESIAN_POINT('',(0.203935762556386,-6.70641031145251,0.940223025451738));
#558=CARTESIAN_POINT('',(0.204807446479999,-6.76376806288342,1.09580473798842));
#559=CARTESIAN_POINT('',(0.206435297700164,-6.87187044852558,1.32701813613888));
#560=CARTESIAN_POINT('',(0.207064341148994,-6.91380178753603,1.40688828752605));
#561=CARTESIAN_POINT('',(0.208422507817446,-7.0048176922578,1.56244542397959));
#562=CARTESIAN_POINT('',(0.209151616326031,-7.05390120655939,1.63813302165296));
#563=CARTESIAN_POINT('',(0.210954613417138,-7.17599722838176,1.80867878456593));
#564=CARTESIAN_POINT('',(0.212063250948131,-7.25158412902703,1.90170534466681));
#565=CARTESIAN_POINT('',(0.214417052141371,-7.41349721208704,2.07781658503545));
#566=CARTESIAN_POINT('',(0.215662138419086,-7.4998173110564,2.16090684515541));
#567=CARTESIAN_POINT('',(0.217459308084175,-7.62559514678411,2.26802026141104));
#568=CARTESIAN_POINT('',(0.217964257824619,-7.66105451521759,2.29681885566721));
#569=CARTESIAN_POINT('',(0.218476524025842,-7.69715831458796,2.32476447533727));
#570=B_SPLINE_CURVE_WITH_KNOTS('',3,(#538,#539,#540,#541,#542,#543,#544,#545,#546,#547,#548,
#549,#550,#551,#552,#553,#554,#555,#556,#557,#558,#559,#560,#561,#562,#563,#564,#565,#566,#567,
#568,#569),.UNSPECIFIED.,.F.,.F.,(4,2,2,2,2,2,2,2,2,2,2,2,2,2,2,4),(0.,0.247992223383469,
0.495972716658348,0.743784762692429,0.991593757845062,1.48701674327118,1.98230986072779,
2.47751685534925,2.97295059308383,3.46860427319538,3.96352840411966,4.23382992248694,
4.50409174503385,4.86279314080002,5.22129214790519,5.35828916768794),.UNSPECIFIED.);
#571=CARTESIAN_POINT('',(0.218472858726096,-7.6969,-2.32456447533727));
#572=VERTEX_POINT('',#571);
#573=EDGE_CURVE('E836',#572,#533,#570,.T.);
#574=ORIENTED_EDGE('',*,*,#573,.F.);
#575=CARTESIAN_POINT('',(5.28804654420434,-5.59701382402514,-2.32456447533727));
#576=VERTEX_POINT('',#575);
#577=EDGE_CURVE('E963',#572,#576,#148,.T.);
#578=ORIENTED_EDGE('',*,*,#577,.T.);
#579=CARTESIAN_POINT('',(5.28822660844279,-5.59719907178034,2.32476447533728));
#580=CARTESIAN_POINT('',(5.24264670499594,-5.55030713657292,2.27415407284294));
#581=CARTESIAN_POINT('',(5.19856819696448,-5.50495120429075,2.2207750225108));
#582=CARTESIAN_POINT('',(5.11370815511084,-5.41761719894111,2.10888540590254));
#583=CARTESIAN_POINT('',(5.07292646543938,-5.37563896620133,2.05037508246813));
#584=CARTESIAN_POINT('',(4.99497636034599,-5.29538898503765,1.92866518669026));
#585=CARTESIAN_POINT('',(4.95780550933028,-5.25711473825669,1.86546882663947));
#586=CARTESIAN_POINT('',(4.88731477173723,-5.18452081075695,1.73483020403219));
#587=CARTESIAN_POINT('',(4.85399483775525,-5.15020108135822,1.66738799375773));
#588=CARTESIAN_POINT('',(4.76014612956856,-5.05352345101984,1.4593120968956));
#589=CARTESIAN_POINT('',(4.70569744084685,-4.99741517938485,1.31288063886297));
#590=CARTESIAN_POINT('',(4.61475012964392,-4.90367911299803,1.00908566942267));
#591=CARTESIAN_POINT('',(4.57824680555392,-4.86604647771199,0.851725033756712));
#592=CARTESIAN_POINT('',(4.52415007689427,-4.81027119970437,0.530443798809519));
#593=CARTESIAN_POINT('',(4.50655338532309,-4.79212516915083,0.36652434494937));
#594=CARTESIAN_POINT('',(4.49076552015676,-4.77584458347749,0.036693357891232));
#595=CARTESIAN_POINT('',(4.49258323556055,-4.77771919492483,-0.129219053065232));
#596=CARTESIAN_POINT('',(4.51558639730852,-4.8014398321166,-0.458305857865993));
#597=CARTESIAN_POINT('',(4.5367804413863,-4.82329472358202,-0.621479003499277));
#598=CARTESIAN_POINT('',(4.59794384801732,-4.88635256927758,-0.940223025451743));
#599=CARTESIAN_POINT('',(4.63788552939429,-4.92752699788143,-1.09580473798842));
#600=CARTESIAN_POINT('',(4.71317439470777,-5.00511799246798,-1.32701813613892));
#601=CARTESIAN_POINT('',(4.74237952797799,-5.03521272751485,-1.40688828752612));
#602=CARTESIAN_POINT('',(4.80577712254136,-5.10053105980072,-1.56244542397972));
#603=CARTESIAN_POINT('',(4.83996885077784,-5.13575390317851,-1.63813302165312));
#604=CARTESIAN_POINT('',(4.92502886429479,-5.22336373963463,-1.80867878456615));
#605=CARTESIAN_POINT('',(4.97769294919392,-5.27759567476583,-1.90170534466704));
#606=CARTESIAN_POINT('',(5.09051839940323,-5.39374990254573,-2.07781658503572));
#607=CARTESIAN_POINT('',(5.15067551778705,-5.45566783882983,-2.1609068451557));
#608=CARTESIAN_POINT('',(5.2383430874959,-5.54587699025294,-2.26802026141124));
#609=CARTESIAN_POINT('',(5.2630595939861,-5.57130760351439,-2.29681885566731));
#610=CARTESIAN_POINT('',(5.28822660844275,-5.59719907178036,-2.32476447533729));
#611=B_SPLINE_CURVE_WITH_KNOTS('',3,(#579,#580,#581,#582,#583,#584,#585,#586,#587,#588,#589,
#590,#591,#592,#593,#594,#595,#596,#597,#598,#599,#600,#601,#602,#603,#604,#605,#606,#607,#608,
#609,#610),.UNSPECIFIED.,.F.,.F.,(4,2,2,2,2,2,2,2,2,2,2,2,2,2,2,4),(0.,0.247992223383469,
0.495972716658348,0.743784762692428,0.991593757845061,1.48701674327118,1.98230986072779,
2.47751685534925,2.97295059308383,3.46860427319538,3.96352840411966,4.23382992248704,
4.50409174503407,4.86279314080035,5.22129214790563,5.35828916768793),.UNSPECIFIED.);
#612=EDGE_CURVE('E867',#535,#576,#611,.T.);
#613=ORIENTED_EDGE('',*,*,#612,.F.);
#614=EDGE_LOOP('',(#537,#574,#578,#613));
#615=FACE_BOUND('',#614,.T.);
#616=ADVANCED_FACE('F468',(#615),#95,.F.);
#617=CARTESIAN_POINT('',(0.277701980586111,-12.4368999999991,0.));
#618=VERTEX_POINT('',#617);
#619=CARTESIAN_POINT('',(8.59785137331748,-8.99058128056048,0.));
#620=VERTEX_POINT('',#619);
#621=EDGE_CURVE('E947',#618,#620,#62,.T.);
#622=ORIENTED_EDGE('',*,*,#621,.F.);
#623=CARTESIAN_POINT('',(0.26466731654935,-11.2966416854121,2.32476447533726));
#624=CARTESIAN_POINT('',(0.265433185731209,-11.3620290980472,2.27415420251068));
#625=CARTESIAN_POINT('',(0.266170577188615,-11.4252687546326,2.22077514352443));
#626=CARTESIAN_POINT('',(0.267584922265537,-11.5470290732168,2.10888477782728));
#627=CARTESIAN_POINT('',(0.268261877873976,-11.6055498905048,2.050373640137));
#628=CARTESIAN_POINT('',(0.269551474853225,-11.7174148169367,1.92866304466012));
#629=CARTESIAN_POINT('',(0.270164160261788,-11.7707624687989,1.86546684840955));
#630=CARTESIAN_POINT('',(0.271322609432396,-11.8719376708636,1.73482862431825));
#631=CARTESIAN_POINT('',(0.271868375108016,-11.9197653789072,1.66738671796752));
#632=CARTESIAN_POINT('',(0.273401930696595,-12.0545086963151,1.45928173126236));
#633=CARTESIAN_POINT('',(0.274286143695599,-12.1326988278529,1.31282376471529));
#634=CARTESIAN_POINT('',(0.275758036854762,-12.2632799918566,1.00899965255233));
#635=CARTESIAN_POINT('',(0.276345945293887,-12.3156908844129,0.851642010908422));
#636=CARTESIAN_POINT('',(0.277087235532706,-12.3818760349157,0.577980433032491));
#637=CARTESIAN_POINT('',(0.277317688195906,-12.4024912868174,0.463288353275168));
#638=CARTESIAN_POINT('',(0.277625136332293,-12.4300152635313,0.232345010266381));
#639=CARTESIAN_POINT('',(0.277702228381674,-12.4369326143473,0.11609477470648));
#640=CARTESIAN_POINT('',(0.277701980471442,-12.4368999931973,-0.000199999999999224));
#641=B_SPLINE_CURVE_WITH_KNOTS('',3,(#623,#624,#625,#626,#627,#628,#629,#630,#631,#632,#633,
#634,#635,#636,#637,#638,#639,#640),.UNSPECIFIED.,.F.,.F.,(4,2,2,2,2,2,2,2,4),(0.,
0.247987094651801,0.495966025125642,0.74377391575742,0.991574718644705,1.4871135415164,
1.9822700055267,2.33108183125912,2.67967392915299),.UNSPECIFIED.);
#642=CARTESIAN_POINT('',(0.264670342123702,-11.2969,2.32456447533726));
#643=VERTEX_POINT('',#642);
#644=EDGE_CURVE('E818',#643,#618,#641,.T.);
#645=ORIENTED_EDGE('',*,*,#644,.F.);
#646=CARTESIAN_POINT('',(7.80096440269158,-8.17526479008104,2.32456447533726));
#647=VERTEX_POINT('',#646);
#648=EDGE_CURVE('E945',#643,#647,#28,.T.);
#649=ORIENTED_EDGE('',*,*,#648,.T.);
#650=CARTESIAN_POINT('',(8.5978513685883,-8.99058127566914,-0.0002));
#651=CARTESIAN_POINT('',(8.59786091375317,-8.99059098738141,0.0824851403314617));
#652=CARTESIAN_POINT('',(8.59542029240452,-8.98809530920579,0.165166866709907));
#653=CARTESIAN_POINT('',(8.5856818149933,-8.97813688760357,0.329940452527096));
#654=CARTESIAN_POINT('',(8.57838412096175,-8.97067430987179,0.412032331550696));
#655=CARTESIAN_POINT('',(8.55898133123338,-8.9508326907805,0.574992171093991));
#656=CARTESIAN_POINT('',(8.54687957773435,-8.93845706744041,0.655860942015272));
#657=CARTESIAN_POINT('',(8.51796677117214,-8.90888896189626,0.815832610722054));
#658=CARTESIAN_POINT('',(8.50115585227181,-8.89169661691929,0.894935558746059));
#659=CARTESIAN_POINT('',(8.44378919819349,-8.83302595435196,1.12887100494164));
#660=CARTESIAN_POINT('',(8.39629702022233,-8.78445140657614,1.2803513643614));
#661=CARTESIAN_POINT('',(8.28425024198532,-8.6698360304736,1.56959083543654));
#662=CARTESIAN_POINT('',(8.21970879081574,-8.60380866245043,1.70736040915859));
#663=CARTESIAN_POINT('',(8.09678328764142,-8.47803208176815,1.92723825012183));
#664=CARTESIAN_POINT('',(8.0422125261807,-8.42219015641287,2.01376675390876));
#665=CARTESIAN_POINT('',(7.92635085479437,-8.30361390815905,2.17693738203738));
#666=CARTESIAN_POINT('',(7.86506421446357,-8.24088396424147,2.2535857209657));
#667=CARTESIAN_POINT('',(7.80078388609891,-8.17507999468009,2.32476447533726));
#668=B_SPLINE_CURVE_WITH_KNOTS('',3,(#650,#651,#652,#653,#654,#655,#656,#657,#658,#659,#660,
#661,#662,#663,#664,#665,#666,#667),.UNSPECIFIED.,.F.,.F.,(4,2,2,2,2,2,2,2,4),(0.,
0.24797496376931,0.495941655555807,0.743736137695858,0.991523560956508,1.4870345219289,
1.98216443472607,2.33102949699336,2.67967404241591),.UNSPECIFIED.);
#669=EDGE_CURVE('E860',#620,#647,#668,.T.);
#670=ORIENTED_EDGE('',*,*,#669,.F.);
#671=EDGE_LOOP('',(#622,#645,#649,#670));
#672=FACE_BOUND('',#671,.T.);
#673=ADVANCED_FACE('F472',(#672),#23,.F.);
#674=CARTESIAN_POINT('',(5.59701382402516,-5.28804654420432,2.32456447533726));
#675=VERTEX_POINT('',#674);
#676=CARTESIAN_POINT('',(7.6969,-0.218472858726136,2.32456447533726));
#677=VERTEX_POINT('',#676);
#678=EDGE_CURVE('E646',#675,#677,#100,.T.);
#679=ORIENTED_EDGE('',*,*,#678,.F.);
#680=CARTESIAN_POINT('',(5.59719907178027,-5.28822660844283,-2.32476447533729));
#681=CARTESIAN_POINT('',(5.55030713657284,-5.24264670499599,-2.27415407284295));
#682=CARTESIAN_POINT('',(5.50495120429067,-5.19856819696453,-2.22077502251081));
#683=CARTESIAN_POINT('',(5.41761719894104,-5.11370815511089,-2.10888540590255));
#684=CARTESIAN_POINT('',(5.37563896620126,-5.07292646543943,-2.05037508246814));
#685=CARTESIAN_POINT('',(5.29538898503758,-4.99497636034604,-1.92866518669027));
#686=CARTESIAN_POINT('',(5.25711473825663,-4.95780550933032,-1.86546882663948));
#687=CARTESIAN_POINT('',(5.18452081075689,-4.88731477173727,-1.73483020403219));
#688=CARTESIAN_POINT('',(5.15020108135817,-4.85399483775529,-1.66738799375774));
#689=CARTESIAN_POINT('',(5.05352345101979,-4.7601461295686,-1.45931209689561));
#690=CARTESIAN_POINT('',(4.9974151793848,-4.70569744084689,-1.31288063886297));
#691=CARTESIAN_POINT('',(4.90367911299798,-4.61475012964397,-1.00908566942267));
#692=CARTESIAN_POINT('',(4.86604647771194,-4.57824680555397,-0.851725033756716));
#693=CARTESIAN_POINT('',(4.81027119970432,-4.52415007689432,-0.530443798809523));
#694=CARTESIAN_POINT('',(4.79212516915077,-4.50655338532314,-0.366524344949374));
#695=CARTESIAN_POINT('',(4.77584458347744,-4.49076552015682,-0.0366933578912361));
#696=CARTESIAN_POINT('',(4.77771919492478,-4.4925832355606,0.129219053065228));
#697=CARTESIAN_POINT('',(4.80143983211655,-4.51558639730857,0.458305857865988));
#698=CARTESIAN_POINT('',(4.82329472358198,-4.53678044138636,0.621479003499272));
#699=CARTESIAN_POINT('',(4.88635256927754,-4.59794384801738,0.940223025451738));
#700=CARTESIAN_POINT('',(4.92752699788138,-4.63788552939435,1.09580473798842));
#701=CARTESIAN_POINT('',(5.00511799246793,-4.71317439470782,1.32701813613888));
#702=CARTESIAN_POINT('',(5.03521272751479,-4.74237952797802,1.40688828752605));
#703=CARTESIAN_POINT('',(5.10053105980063,-4.80577712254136,1.56244542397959));
#704=CARTESIAN_POINT('',(5.13575390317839,-4.83996885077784,1.63813302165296));
#705=CARTESIAN_POINT('',(5.22336373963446,-4.92502886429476,1.80867878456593));
#706=CARTESIAN_POINT('',(5.27759567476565,-4.97769294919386,1.90170534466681));
#707=CARTESIAN_POINT('',(5.39374990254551,-5.09051839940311,2.07781658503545));
#708=CARTESIAN_POINT('',(5.45566783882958,-5.15067551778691,2.16090684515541));
#709=CARTESIAN_POINT('',(5.54587699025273,-5.23834308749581,2.26802026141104));
#710=CARTESIAN_POINT('',(5.57130760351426,-5.26305959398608,2.29681885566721));
#711=CARTESIAN_POINT('',(5.59719907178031,-5.28822660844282,2.32476447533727));
#712=B_SPLINE_CURVE_WITH_KNOTS('',3,(#680,#681,#682,#683,#684,#685,#686,#687,#688,#689,#690,
#691,#692,#693,#694,#695,#696,#697,#698,#699,#700,#701,#702,#703,#704,#705,#706,#707,#708,#709,
#710,#711),.UNSPECIFIED.,.F.,.F.,(4,2,2,2,2,2,2,2,2,2,2,2,2,2,2,4),(0.,0.247992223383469,
0.495972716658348,0.743784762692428,0.991593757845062,1.48701674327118,1.98230986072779,
2.47751685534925,2.97295059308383,3.46860427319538,3.96352840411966,4.23382992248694,
4.50409174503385,4.86279314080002,5.22129214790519,5.35828916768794),.UNSPECIFIED.);
#713=CARTESIAN_POINT('',(5.59701382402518,-5.28804654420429,-2.32456447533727));
#714=VERTEX_POINT('',#713);
#715=EDGE_CURVE('E897',#714,#675,#712,.T.);
#716=ORIENTED_EDGE('',*,*,#715,.F.);
#717=CARTESIAN_POINT('',(7.6969,-0.218472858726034,-2.32456447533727));
#718=VERTEX_POINT('',#717);
#719=EDGE_CURVE('E964',#714,#718,#148,.T.);
#720=ORIENTED_EDGE('',*,*,#719,.T.);
#721=CARTESIAN_POINT('',(7.69715831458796,-0.218476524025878,2.32476447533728));
#722=CARTESIAN_POINT('',(7.63177085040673,-0.217548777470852,2.27415407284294));
#723=CARTESIAN_POINT('',(7.56853115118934,-0.21664550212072,2.2207750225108));
#724=CARTESIAN_POINT('',(7.44677157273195,-0.214896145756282,2.10888540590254));
#725=CARTESIAN_POINT('',(7.38825147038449,-0.214050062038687,2.05037508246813));
#726=CARTESIAN_POINT('',(7.27638711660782,-0.212423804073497,1.92866518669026));
#727=CARTESIAN_POINT('',(7.22303937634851,-0.211643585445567,1.86546882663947));
#728=CARTESIAN_POINT('',(7.12186323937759,-0.210156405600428,1.73483020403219));
#729=CARTESIAN_POINT('',(7.07403477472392,-0.209449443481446,1.66738799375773));
#730=CARTESIAN_POINT('',(6.9393123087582,-0.207449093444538,1.4593120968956));
#731=CARTESIAN_POINT('',(6.86113673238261,-0.206275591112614,1.31288063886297));
#732=CARTESIAN_POINT('',(6.73054586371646,-0.204303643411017,1.00908566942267));
#733=CARTESIAN_POINT('',(6.67812382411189,-0.203505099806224,0.851725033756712));
#734=CARTESIAN_POINT('',(6.60043258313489,-0.202318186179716,0.530443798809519));
#735=CARTESIAN_POINT('',(6.57515866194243,-0.201929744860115,0.36652434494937));
#736=CARTESIAN_POINT('',(6.55248284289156,-0.20158133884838,0.0366933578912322));
#737=CARTESIAN_POINT('',(6.55509371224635,-0.201621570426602,-0.129219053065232));
#738=CARTESIAN_POINT('',(6.58813242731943,-0.202128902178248,-0.458305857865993));
#739=CARTESIAN_POINT('',(6.61857262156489,-0.202596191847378,-0.621479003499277));
#740=CARTESIAN_POINT('',(6.7064103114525,-0.203935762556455,-0.940223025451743));
#741=CARTESIAN_POINT('',(6.76376806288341,-0.204807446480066,-1.09580473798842));
#742=CARTESIAN_POINT('',(6.87187044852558,-0.206435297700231,-1.32701813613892));
#743=CARTESIAN_POINT('',(6.91380178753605,-0.207064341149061,-1.40688828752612));
#744=CARTESIAN_POINT('',(7.00481769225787,-0.208422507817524,-1.56244542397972));
#745=CARTESIAN_POINT('',(7.05390120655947,-0.20915161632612,-1.63813302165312));
#746=CARTESIAN_POINT('',(7.1759972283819,-0.210954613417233,-1.80867878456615));
#747=CARTESIAN_POINT('',(7.2515841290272,-0.212063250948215,-1.90170534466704));
#748=CARTESIAN_POINT('',(7.41349721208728,-0.214417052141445,-2.07781658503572));
#749=CARTESIAN_POINT('',(7.49981731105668,-0.21566213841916,-2.1609068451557));
#750=CARTESIAN_POINT('',(7.62559514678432,-0.217459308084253,-2.26802026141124));
#751=CARTESIAN_POINT('',(7.66105451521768,-0.217964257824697,-2.29681885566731));
#752=CARTESIAN_POINT('',(7.69715831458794,-0.218476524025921,-2.32476447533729));
#753=B_SPLINE_CURVE_WITH_KNOTS('',3,(#721,#722,#723,#724,#725,#726,#727,#728,#729,#730,#731,
#732,#733,#734,#735,#736,#737,#738,#739,#740,#741,#742,#743,#744,#745,#746,#747,#748,#749,#750,
#751,#752),.UNSPECIFIED.,.F.,.F.,(4,2,2,2,2,2,2,2,2,2,2,2,2,2,2,4),(0.,0.247992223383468,
0.495972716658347,0.743784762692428,0.991593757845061,1.48701674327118,1.98230986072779,
2.47751685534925,2.97295059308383,3.46860427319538,3.96352840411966,4.23382992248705,
4.50409174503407,4.86279314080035,5.22129214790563,5.35828916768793),.UNSPECIFIED.);
#754=EDGE_CURVE('E603',#677,#718,#753,.T.);
#755=ORIENTED_EDGE('',*,*,#754,.F.);
#756=EDGE_LOOP('',(#679,#716,#720,#755));
#757=FACE_BOUND('',#756,.T.);
#758=ADVANCED_FACE('F477',(#757),#95,.F.);
#759=CARTESIAN_POINT('',(8.99058128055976,-8.59785137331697,0.));
#760=VERTEX_POINT('',#759);
#761=CARTESIAN_POINT('',(12.4369,-0.277701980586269,0.));
#762=VERTEX_POINT('',#761);
#763=EDGE_CURVE('E289',#760,#762,#62,.T.);
#764=ORIENTED_EDGE('',*,*,#763,.F.);
#765=CARTESIAN_POINT('',(8.17507999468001,-7.800783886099,2.32476447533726));
#766=CARTESIAN_POINT('',(8.22185742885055,-7.84647821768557,2.27415420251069));
#767=CARTESIAN_POINT('',(8.26709603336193,-7.8906739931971,2.22077514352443));
#768=CARTESIAN_POINT('',(8.35419367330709,-7.9757714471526,2.10888477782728));
#769=CARTESIAN_POINT('',(8.3960528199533,-8.01667323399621,2.050373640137));
#770=CARTESIAN_POINT('',(8.4760651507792,-8.09486179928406,1.92866304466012));
#771=CARTESIAN_POINT('',(8.51422087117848,-8.13215105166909,1.86546684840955));
#772=CARTESIAN_POINT('',(8.58658168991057,-8.2028735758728,1.73482862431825));
#773=CARTESIAN_POINT('',(8.62078690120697,-8.23630695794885,1.66738671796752));
#774=CARTESIAN_POINT('',(8.71714920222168,-8.33050048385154,1.45928173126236));
#775=CARTESIAN_POINT('',(8.77306320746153,-8.38516402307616,1.31282376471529));
#776=CARTESIAN_POINT('',(8.86643881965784,-8.47645806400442,1.00899965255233));
#777=CARTESIAN_POINT('',(8.90391463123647,-8.513102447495,0.851642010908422));
#778=CARTESIAN_POINT('',(8.95123877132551,-8.55937824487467,0.577980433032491));
#779=CARTESIAN_POINT('',(8.96597891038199,-8.57379247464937,0.463288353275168));
#780=CARTESIAN_POINT('',(8.9856586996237,-8.59303746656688,0.232345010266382));
#781=CARTESIAN_POINT('',(8.9906045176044,-8.59787425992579,0.116094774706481));
#782=CARTESIAN_POINT('',(8.99058127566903,-8.59785136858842,-0.000199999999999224));
#783=B_SPLINE_CURVE_WITH_KNOTS('',3,(#765,#766,#767,#768,#769,#770,#771,#772,#773,#774,#775,
#776,#777,#778,#779,#780,#781,#782),.UNSPECIFIED.,.F.,.F.,(4,2,2,2,2,2,2,2,4),(0.,
0.247987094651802,0.49596602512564,0.743773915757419,0.991574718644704,1.4871135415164,
1.9822700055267,2.33108183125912,2.67967392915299),.UNSPECIFIED.);
#784=CARTESIAN_POINT('',(8.17526479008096,-7.80096440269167,2.32456447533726));
#785=VERTEX_POINT('',#784);
#786=EDGE_CURVE('E880',#785,#760,#783,.T.);
#787=ORIENTED_EDGE('',*,*,#786,.F.);
#788=CARTESIAN_POINT('',(11.2969,-0.264670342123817,2.32456447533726));
#789=VERTEX_POINT('',#788);
#790=EDGE_CURVE('E279',#785,#789,#28,.T.);
#791=ORIENTED_EDGE('',*,*,#790,.T.);
#792=CARTESIAN_POINT('',(12.4368999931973,-0.277701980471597,-0.0002));
#793=CARTESIAN_POINT('',(12.4369136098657,-0.27770209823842,0.0824851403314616));
#794=CARTESIAN_POINT('',(12.4334231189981,-0.277663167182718,0.165166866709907));
#795=CARTESIAN_POINT('',(12.4194953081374,-0.277507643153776,0.329940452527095));
#796=CARTESIAN_POINT('',(12.4090582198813,-0.277391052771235,0.412032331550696));
#797=CARTESIAN_POINT('',(12.3813082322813,-0.27708075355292,0.574992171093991));
#798=CARTESIAN_POINT('',(12.3640001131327,-0.276887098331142,0.655860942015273));
#799=CARTESIAN_POINT('',(12.3226478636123,-0.276423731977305,0.815832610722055));
#800=CARTESIAN_POINT('',(12.2986039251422,-0.276154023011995,0.894935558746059));
#801=CARTESIAN_POINT('',(12.2165531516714,-0.275231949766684,1.12887100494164));
#802=CARTESIAN_POINT('',(12.1486237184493,-0.274466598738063,1.2803513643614));
#803=CARTESIAN_POINT('',(11.9883493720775,-0.272650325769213,1.56959083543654));
#804=CARTESIAN_POINT('',(11.8960232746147,-0.271599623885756,1.70736040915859));
#805=CARTESIAN_POINT('',(11.7201643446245,-0.269583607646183,1.92723825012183));
#806=CARTESIAN_POINT('',(11.6420907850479,-0.268684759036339,2.01376675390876));
#807=CARTESIAN_POINT('',(11.4763181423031,-0.26676526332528,2.17693738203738));
#808=CARTESIAN_POINT('',(11.3886251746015,-0.265744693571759,2.2535857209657));
#809=CARTESIAN_POINT('',(11.2966416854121,-0.264667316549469,2.32476447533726));
#810=B_SPLINE_CURVE_WITH_KNOTS('',3,(#792,#793,#794,#795,#796,#797,#798,#799,#800,#801,#802,
#803,#804,#805,#806,#807,#808,#809),.UNSPECIFIED.,.F.,.F.,(4,2,2,2,2,2,2,2,4),(0.,
0.24797496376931,0.495941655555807,0.743736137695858,0.991523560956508,1.4870345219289,
1.98216443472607,2.33102949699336,2.67967404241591),.UNSPECIFIED.);
#811=EDGE_CURVE('E597',#762,#789,#810,.T.);
#812=ORIENTED_EDGE('',*,*,#811,.F.);
#813=EDGE_LOOP('',(#764,#787,#791,#812));
#814=FACE_BOUND('',#813,.T.);
#815=ADVANCED_FACE('F481',(#814),#23,.F.);
#816=CARTESIAN_POINT('',(7.6969,0.218472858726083,2.32456447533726));
#817=VERTEX_POINT('',#816);
#818=CARTESIAN_POINT('',(5.59701382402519,5.28804654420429,2.32456447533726));
#819=VERTEX_POINT('',#818);
#820=EDGE_CURVE('E645',#817,#819,#100,.T.);
#821=ORIENTED_EDGE('',*,*,#820,.F.);
#822=CARTESIAN_POINT('',(7.69715831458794,0.21847652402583,-2.32476447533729));
#823=CARTESIAN_POINT('',(7.63177085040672,0.217548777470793,-2.27415407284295));
#824=CARTESIAN_POINT('',(7.56853115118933,0.216645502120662,-2.22077502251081));
#825=CARTESIAN_POINT('',(7.44677157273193,0.214896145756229,-2.10888540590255));
#826=CARTESIAN_POINT('',(7.38825147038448,0.214050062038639,-2.05037508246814));
#827=CARTESIAN_POINT('',(7.27638711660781,0.212423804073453,-1.92866518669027));
#828=CARTESIAN_POINT('',(7.2230393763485,0.211643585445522,-1.86546882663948));
#829=CARTESIAN_POINT('',(7.12186323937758,0.210156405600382,-1.73483020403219));
#830=CARTESIAN_POINT('',(7.07403477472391,0.2094494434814,-1.66738799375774));
#831=CARTESIAN_POINT('',(6.93931230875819,0.207449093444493,-1.45931209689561));
#832=CARTESIAN_POINT('',(6.8611367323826,0.206275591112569,-1.31288063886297));
#833=CARTESIAN_POINT('',(6.73054586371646,0.204303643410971,-1.00908566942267));
#834=CARTESIAN_POINT('',(6.67812382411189,0.203505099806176,-0.851725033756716));
#835=CARTESIAN_POINT('',(6.60043258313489,0.202318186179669,-0.530443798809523));
#836=CARTESIAN_POINT('',(6.57515866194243,0.201929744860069,-0.366524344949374));
#837=CARTESIAN_POINT('',(6.55248284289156,0.201581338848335,-0.0366933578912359));
#838=CARTESIAN_POINT('',(6.55509371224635,0.201621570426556,0.129219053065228));
#839=CARTESIAN_POINT('',(6.58813242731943,0.202128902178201,0.458305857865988));
#840=CARTESIAN_POINT('',(6.6185726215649,0.20259619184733,0.621479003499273));
#841=CARTESIAN_POINT('',(6.70641031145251,0.203935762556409,0.940223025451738));
#842=CARTESIAN_POINT('',(6.76376806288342,0.204807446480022,1.09580473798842));
#843=CARTESIAN_POINT('',(6.87187044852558,0.206435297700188,1.32701813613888));
#844=CARTESIAN_POINT('',(6.91380178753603,0.207064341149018,1.40688828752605));
#845=CARTESIAN_POINT('',(7.0048176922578,0.208422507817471,1.56244542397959));
#846=CARTESIAN_POINT('',(7.05390120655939,0.209151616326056,1.63813302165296));
#847=CARTESIAN_POINT('',(7.17599722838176,0.210954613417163,1.80867878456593));
#848=CARTESIAN_POINT('',(7.25158412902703,0.212063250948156,1.90170534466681));
#849=CARTESIAN_POINT('',(7.41349721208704,0.214417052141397,2.07781658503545));
#850=CARTESIAN_POINT('',(7.4998173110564,0.215662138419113,2.16090684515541));
#851=CARTESIAN_POINT('',(7.62559514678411,0.217459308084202,2.26802026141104));
#852=CARTESIAN_POINT('',(7.66105451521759,0.217964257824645,2.29681885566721));
#853=CARTESIAN_POINT('',(7.69715831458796,0.218476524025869,2.32476447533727));
#854=B_SPLINE_CURVE_WITH_KNOTS('',3,(#822,#823,#824,#825,#826,#827,#828,#829,#830,#831,#832,
#833,#834,#835,#836,#837,#838,#839,#840,#841,#842,#843,#844,#845,#846,#847,#848,#849,#850,#851,
#852,#853),.UNSPECIFIED.,.F.,.F.,(4,2,2,2,2,2,2,2,2,2,2,2,2,2,2,4),(0.,0.247992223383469,
0.495972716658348,0.743784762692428,0.991593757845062,1.48701674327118,1.98230986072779,
2.47751685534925,2.97295059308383,3.46860427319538,3.96352840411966,4.23382992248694,
4.50409174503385,4.86279314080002,5.22129214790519,5.35828916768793),.UNSPECIFIED.);
#855=CARTESIAN_POINT('',(7.6969,0.218472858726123,-2.32456447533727));
#856=VERTEX_POINT('',#855);
#857=EDGE_CURVE('E559',#856,#817,#854,.T.);
#858=ORIENTED_EDGE('',*,*,#857,.F.);
#859=CARTESIAN_POINT('',(5.59701382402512,5.28804654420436,-2.32456447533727));
#860=VERTEX_POINT('',#859);
#861=EDGE_CURVE('E632',#856,#860,#148,.T.);
#862=ORIENTED_EDGE('',*,*,#861,.T.);
#863=CARTESIAN_POINT('',(5.59719907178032,5.28822660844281,2.32476447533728));
#864=CARTESIAN_POINT('',(5.5503071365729,5.24264670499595,2.27415407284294));
#865=CARTESIAN_POINT('',(5.50495120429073,5.1985681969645,2.2207750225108));
#866=CARTESIAN_POINT('',(5.41761719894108,5.11370815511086,2.10888540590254));
#867=CARTESIAN_POINT('',(5.3756389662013,5.07292646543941,2.05037508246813));
#868=CARTESIAN_POINT('',(5.29538898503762,4.99497636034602,1.92866518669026));
#869=CARTESIAN_POINT('',(5.25711473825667,4.9578055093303,1.86546882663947));
#870=CARTESIAN_POINT('',(5.18452081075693,4.88731477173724,1.73483020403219));
#871=CARTESIAN_POINT('',(5.15020108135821,4.85399483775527,1.66738799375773));
#872=CARTESIAN_POINT('',(5.05352345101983,4.76014612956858,1.4593120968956));
#873=CARTESIAN_POINT('',(4.99741517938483,4.70569744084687,1.31288063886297));
#874=CARTESIAN_POINT('',(4.90367911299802,4.61475012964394,1.00908566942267));
#875=CARTESIAN_POINT('',(4.86604647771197,4.57824680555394,0.851725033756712));
#876=CARTESIAN_POINT('',(4.81027119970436,4.52415007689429,0.530443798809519));
#877=CARTESIAN_POINT('',(4.79212516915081,4.50655338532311,0.36652434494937));
#878=CARTESIAN_POINT('',(4.77584458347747,4.49076552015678,0.0366933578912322));
#879=CARTESIAN_POINT('',(4.77771919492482,4.49258323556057,-0.129219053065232));
#880=CARTESIAN_POINT('',(4.80143983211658,4.51558639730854,-0.458305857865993));
#881=CARTESIAN_POINT('',(4.823294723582,4.53678044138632,-0.621479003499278));
#882=CARTESIAN_POINT('',(4.88635256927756,4.59794384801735,-0.940223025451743));
#883=CARTESIAN_POINT('',(4.92752699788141,4.63788552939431,-1.09580473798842));
#884=CARTESIAN_POINT('',(5.00511799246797,4.71317439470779,-1.32701813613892));
#885=CARTESIAN_POINT('',(5.03521272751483,4.742379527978,-1.40688828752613));
#886=CARTESIAN_POINT('',(5.1005310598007,4.80577712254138,-1.56244542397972));
#887=CARTESIAN_POINT('',(5.13575390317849,4.83996885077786,-1.63813302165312));
#888=CARTESIAN_POINT('',(5.22336373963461,4.92502886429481,-1.80867878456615));
#889=CARTESIAN_POINT('',(5.27759567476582,4.97769294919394,-1.90170534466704));
#890=CARTESIAN_POINT('',(5.39374990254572,5.09051839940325,-2.07781658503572));
#891=CARTESIAN_POINT('',(5.45566783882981,5.15067551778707,-2.1609068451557));
#892=CARTESIAN_POINT('',(5.54587699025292,5.23834308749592,-2.26802026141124));
#893=CARTESIAN_POINT('',(5.57130760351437,5.26305959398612,-2.29681885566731));
#894=CARTESIAN_POINT('',(5.59719907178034,5.28822660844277,-2.32476447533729));
#895=B_SPLINE_CURVE_WITH_KNOTS('',3,(#863,#864,#865,#866,#867,#868,#869,#870,#871,#872,#873,
#874,#875,#876,#877,#878,#879,#880,#881,#882,#883,#884,#885,#886,#887,#888,#889,#890,#891,#892,
#893,#894),.UNSPECIFIED.,.F.,.F.,(4,2,2,2,2,2,2,2,2,2,2,2,2,2,2,4),(0.,0.247992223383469,
0.495972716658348,0.743784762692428,0.991593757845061,1.48701674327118,1.98230986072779,
2.47751685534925,2.97295059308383,3.46860427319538,3.96352840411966,4.23382992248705,
4.50409174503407,4.86279314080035,5.22129214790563,5.35828916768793),.UNSPECIFIED.);
#896=EDGE_CURVE('E540',#819,#860,#895,.T.);
#897=ORIENTED_EDGE('',*,*,#896,.F.);
#898=EDGE_LOOP('',(#821,#858,#862,#897));
#899=FACE_BOUND('',#898,.T.);
#900=ADVANCED_FACE('F486',(#899),#95,.F.);
#901=CARTESIAN_POINT('',(12.4368999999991,0.277701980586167,0.));
#902=VERTEX_POINT('',#901);
#903=CARTESIAN_POINT('',(8.99058128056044,8.59785137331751,0.));
#904=VERTEX_POINT('',#903);
#905=EDGE_CURVE('E285',#902,#904,#62,.T.);
#906=ORIENTED_EDGE('',*,*,#905,.F.);
#907=CARTESIAN_POINT('',(11.2966416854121,0.26466731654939,2.32476447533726));
#908=CARTESIAN_POINT('',(11.3620290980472,0.265433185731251,2.27415420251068));
#909=CARTESIAN_POINT('',(11.4252687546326,0.266170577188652,2.22077514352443));
#910=CARTESIAN_POINT('',(11.5470290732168,0.267584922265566,2.10888477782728));
#911=CARTESIAN_POINT('',(11.6055498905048,0.268261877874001,2.050373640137));
#912=CARTESIAN_POINT('',(11.7174148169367,0.269551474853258,1.92866304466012));
#913=CARTESIAN_POINT('',(11.7707624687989,0.270164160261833,1.86546684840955));
#914=CARTESIAN_POINT('',(11.8719376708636,0.271322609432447,1.73482862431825));
#915=CARTESIAN_POINT('',(11.9197653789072,0.271868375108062,1.66738671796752));
#916=CARTESIAN_POINT('',(12.0545086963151,0.273401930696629,1.45928173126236));
#917=CARTESIAN_POINT('',(12.1326988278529,0.274286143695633,1.31282376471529));
#918=CARTESIAN_POINT('',(12.2632799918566,0.275758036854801,1.00899965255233));
#919=CARTESIAN_POINT('',(12.3156908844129,0.276345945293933,0.851642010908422));
#920=CARTESIAN_POINT('',(12.3818760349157,0.277087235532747,0.577980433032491));
#921=CARTESIAN_POINT('',(12.4024912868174,0.27731768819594,0.463288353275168));
#922=CARTESIAN_POINT('',(12.4300152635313,0.277625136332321,0.232345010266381));
#923=CARTESIAN_POINT('',(12.4369326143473,0.277702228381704,0.11609477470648));
#924=CARTESIAN_POINT('',(12.4368999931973,0.277701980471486,-0.000199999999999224));
#925=B_SPLINE_CURVE_WITH_KNOTS('',3,(#907,#908,#909,#910,#911,#912,#913,#914,#915,#916,#917,
#918,#919,#920,#921,#922,#923,#924),.UNSPECIFIED.,.F.,.F.,(4,2,2,2,2,2,2,2,4),(0.,
0.247987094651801,0.495966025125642,0.743773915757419,0.991574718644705,1.4871135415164,
1.9822700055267,2.33108183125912,2.67967392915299),.UNSPECIFIED.);
#926=CARTESIAN_POINT('',(11.2969,0.264670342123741,2.32456447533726));
#927=VERTEX_POINT('',#926);
#928=EDGE_CURVE('E504',#927,#902,#925,.T.);
#929=ORIENTED_EDGE('',*,*,#928,.F.);
#930=CARTESIAN_POINT('',(8.17526479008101,7.80096440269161,2.32456447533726));
#931=VERTEX_POINT('',#930);
#932=EDGE_CURVE('E273',#927,#931,#28,.T.);
#933=ORIENTED_EDGE('',*,*,#932,.T.);
#934=CARTESIAN_POINT('',(8.99058127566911,8.59785136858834,-0.0002));
#935=CARTESIAN_POINT('',(8.99059098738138,8.5978609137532,0.0824851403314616));
#936=CARTESIAN_POINT('',(8.98809530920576,8.59542029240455,0.165166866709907));
#937=CARTESIAN_POINT('',(8.97813688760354,8.58568181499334,0.329940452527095));
#938=CARTESIAN_POINT('',(8.97067430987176,8.57838412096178,0.412032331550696));
#939=CARTESIAN_POINT('',(8.95083269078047,8.55898133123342,0.57499217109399));
#940=CARTESIAN_POINT('',(8.93845706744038,8.54687957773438,0.655860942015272));
#941=CARTESIAN_POINT('',(8.90888896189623,8.51796677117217,0.815832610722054));
#942=CARTESIAN_POINT('',(8.89169661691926,8.50115585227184,0.894935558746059));
#943=CARTESIAN_POINT('',(8.83302595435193,8.44378919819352,1.12887100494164));
#944=CARTESIAN_POINT('',(8.78445140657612,8.39629702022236,1.2803513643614));
#945=CARTESIAN_POINT('',(8.66983603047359,8.28425024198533,1.56959083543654));
#946=CARTESIAN_POINT('',(8.60380866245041,8.21970879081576,1.70736040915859));
#947=CARTESIAN_POINT('',(8.47803208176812,8.09678328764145,1.92723825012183));
#948=CARTESIAN_POINT('',(8.42219015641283,8.04221252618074,2.01376675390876));
#949=CARTESIAN_POINT('',(8.30361390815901,7.92635085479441,2.17693738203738));
#950=CARTESIAN_POINT('',(8.24088396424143,7.86506421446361,2.2535857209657));
#951=CARTESIAN_POINT('',(8.17507999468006,7.80078388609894,2.32476447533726));
#952=B_SPLINE_CURVE_WITH_KNOTS('',3,(#934,#935,#936,#937,#938,#939,#940,#941,#942,#943,#944,
#945,#946,#947,#948,#949,#950,#951),.UNSPECIFIED.,.F.,.F.,(4,2,2,2,2,2,2,2,4),(0.,
0.24797496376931,0.495941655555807,0.743736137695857,0.991523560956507,1.4870345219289,
1.98216443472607,2.33102949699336,2.67967404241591),.UNSPECIFIED.);
#953=EDGE_CURVE('E507',#904,#931,#952,.T.);
#954=ORIENTED_EDGE('',*,*,#953,.F.);
#955=EDGE_LOOP('',(#906,#929,#933,#954));
#956=FACE_BOUND('',#955,.T.);
#957=ADVANCED_FACE('F436',(#956),#23,.F.);
#958=CARTESIAN_POINT('',(5.28804654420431,5.59701382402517,2.32456447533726));
#959=VERTEX_POINT('',#958);
#960=CARTESIAN_POINT('',(0.218472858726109,7.6969,2.32456447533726));
#961=VERTEX_POINT('',#960);
#962=EDGE_CURVE('E306',#959,#961,#100,.T.);
#963=ORIENTED_EDGE('',*,*,#962,.F.);
#964=CARTESIAN_POINT('',(5.28822660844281,5.59719907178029,-2.32476447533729));
#965=CARTESIAN_POINT('',(5.24264670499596,5.55030713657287,-2.27415407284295));
#966=CARTESIAN_POINT('',(5.19856819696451,5.5049512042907,-2.22077502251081));
#967=CARTESIAN_POINT('',(5.11370815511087,5.41761719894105,-2.10888540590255));
#968=CARTESIAN_POINT('',(5.07292646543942,5.37563896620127,-2.05037508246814));
#969=CARTESIAN_POINT('',(4.99497636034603,5.29538898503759,-1.92866518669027));
#970=CARTESIAN_POINT('',(4.95780550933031,5.25711473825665,-1.86546882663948));
#971=CARTESIAN_POINT('',(4.88731477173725,5.18452081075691,-1.73483020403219));
#972=CARTESIAN_POINT('',(4.85399483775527,5.15020108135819,-1.66738799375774));
#973=CARTESIAN_POINT('',(4.76014612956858,5.0535234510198,-1.45931209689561));
#974=CARTESIAN_POINT('',(4.70569744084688,4.9974151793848,-1.31288063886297));
#975=CARTESIAN_POINT('',(4.61475012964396,4.90367911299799,-1.00908566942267));
#976=CARTESIAN_POINT('',(4.57824680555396,4.86604647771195,-0.851725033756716));
#977=CARTESIAN_POINT('',(4.5241500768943,4.81027119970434,-0.530443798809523));
#978=CARTESIAN_POINT('',(4.50655338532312,4.79212516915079,-0.366524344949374));
#979=CARTESIAN_POINT('',(4.4907655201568,4.77584458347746,-0.0366933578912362));
#980=CARTESIAN_POINT('',(4.49258323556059,4.7777191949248,0.129219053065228));
#981=CARTESIAN_POINT('',(4.51558639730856,4.80143983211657,0.458305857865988));
#982=CARTESIAN_POINT('',(4.53678044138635,4.82329472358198,0.621479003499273));
#983=CARTESIAN_POINT('',(4.59794384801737,4.88635256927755,0.940223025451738));
#984=CARTESIAN_POINT('',(4.63788552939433,4.9275269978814,1.09580473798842));
#985=CARTESIAN_POINT('',(4.7131743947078,5.00511799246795,1.32701813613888));
#986=CARTESIAN_POINT('',(4.742379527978,5.0352127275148,1.40688828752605));
#987=CARTESIAN_POINT('',(4.80577712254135,5.10053105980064,1.56244542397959));
#988=CARTESIAN_POINT('',(4.83996885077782,5.1357539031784,1.63813302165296));
#989=CARTESIAN_POINT('',(4.92502886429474,5.22336373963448,1.80867878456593));
#990=CARTESIAN_POINT('',(4.97769294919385,5.27759567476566,1.90170534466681));
#991=CARTESIAN_POINT('',(5.0905183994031,5.39374990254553,2.07781658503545));
#992=CARTESIAN_POINT('',(5.15067551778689,5.4556678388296,2.16090684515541));
#993=CARTESIAN_POINT('',(5.23834308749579,5.54587699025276,2.26802026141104));
#994=CARTESIAN_POINT('',(5.26305959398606,5.57130760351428,2.29681885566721));
#995=CARTESIAN_POINT('',(5.2882266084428,5.59719907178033,2.32476447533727));
#996=B_SPLINE_CURVE_WITH_KNOTS('',3,(#964,#965,#966,#967,#968,#969,#970,#971,#972,#973,#974,
#975,#976,#977,#978,#979,#980,#981,#982,#983,#984,#985,#986,#987,#988,#989,#990,#991,#992,#993,
#994,#995),.UNSPECIFIED.,.F.,.F.,(4,2,2,2,2,2,2,2,2,2,2,2,2,2,2,4),(0.,0.247992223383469,
0.495972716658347,0.743784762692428,0.991593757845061,1.48701674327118,1.98230986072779,
2.47751685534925,2.97295059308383,3.46860427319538,3.96352840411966,4.23382992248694,
4.50409174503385,4.86279314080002,5.22129214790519,5.35828916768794),.UNSPECIFIED.);
#997=CARTESIAN_POINT('',(5.28804654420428,5.5970138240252,-2.32456447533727));
#998=VERTEX_POINT('',#997);
#999=EDGE_CURVE('E318',#998,#959,#996,.T.);
#1000=ORIENTED_EDGE('',*,*,#999,.F.);
#1001=CARTESIAN_POINT('',(0.218472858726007,7.6969,-2.32456447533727));
#1002=VERTEX_POINT('',#1001);
#1003=EDGE_CURVE('E301',#998,#1002,#148,.T.);
#1004=ORIENTED_EDGE('',*,*,#1003,.T.);
#1005=CARTESIAN_POINT('',(0.218476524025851,7.69715831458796,2.32476447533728));
#1006=CARTESIAN_POINT('',(0.217548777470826,7.63177085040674,2.27415407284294));
#1007=CARTESIAN_POINT('',(0.216645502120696,7.56853115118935,2.2207750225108));
#1008=CARTESIAN_POINT('',(0.21489614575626,7.44677157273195,2.10888540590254));
#1009=CARTESIAN_POINT('',(0.214050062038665,7.38825147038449,2.05037508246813));
#1010=CARTESIAN_POINT('',(0.212423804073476,7.27638711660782,1.92866518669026));
#1011=CARTESIAN_POINT('',(0.211643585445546,7.22303937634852,1.86546882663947));
#1012=CARTESIAN_POINT('',(0.210156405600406,7.12186323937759,1.73483020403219));
#1013=CARTESIAN_POINT('',(0.209449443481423,7.07403477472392,1.66738799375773));
#1014=CARTESIAN_POINT('',(0.20744909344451,6.9393123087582,1.4593120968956));
#1015=CARTESIAN_POINT('',(0.206275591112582,6.86113673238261,1.31288063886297));
#1016=CARTESIAN_POINT('',(0.204303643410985,6.73054586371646,1.00908566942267));
#1017=CARTESIAN_POINT('',(0.203505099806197,6.67812382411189,0.851725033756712));
#1018=CARTESIAN_POINT('',(0.202318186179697,6.60043258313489,0.530443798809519));
#1019=CARTESIAN_POINT('',(0.201929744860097,6.57515866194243,0.36652434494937));
#1020=CARTESIAN_POINT('',(0.201581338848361,6.55248284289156,0.0366933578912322));
#1021=CARTESIAN_POINT('',(0.20162157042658,6.55509371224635,-0.129219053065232));
#1022=CARTESIAN_POINT('',(0.202128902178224,6.58813242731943,-0.458305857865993));
#1023=CARTESIAN_POINT('',(0.202596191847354,6.6185726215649,-0.621479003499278));
#1024=CARTESIAN_POINT('',(0.203935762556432,6.70641031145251,-0.940223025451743));
#1025=CARTESIAN_POINT('',(0.204807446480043,6.76376806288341,-1.09580473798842));
#1026=CARTESIAN_POINT('',(0.206435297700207,6.87187044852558,-1.32701813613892));
#1027=CARTESIAN_POINT('',(0.207064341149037,6.91380178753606,-1.40688828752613));
#1028=CARTESIAN_POINT('',(0.2084225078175,7.00481769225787,-1.56244542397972));
#1029=CARTESIAN_POINT('',(0.209151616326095,7.05390120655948,-1.63813302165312));
#1030=CARTESIAN_POINT('',(0.210954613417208,7.1759972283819,-1.80867878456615));
#1031=CARTESIAN_POINT('',(0.21206325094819,7.2515841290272,-1.90170534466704));
#1032=CARTESIAN_POINT('',(0.214417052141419,7.41349721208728,-2.07781658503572));
#1033=CARTESIAN_POINT('',(0.215662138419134,7.49981731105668,-2.1609068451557));
#1034=CARTESIAN_POINT('',(0.217459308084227,7.62559514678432,-2.26802026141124));
#1035=CARTESIAN_POINT('',(0.21796425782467,7.66105451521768,-2.29681885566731));
#1036=CARTESIAN_POINT('',(0.218476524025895,7.69715831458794,-2.32476447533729));
#1037=B_SPLINE_CURVE_WITH_KNOTS('',3,(#1005,#1006,#1007,#1008,#1009,#1010,#1011,#1012,#1013,
#1014,#1015,#1016,#1017,#1018,#1019,#1020,#1021,#1022,#1023,#1024,#1025,#1026,#1027,#1028,#1029,
#1030,#1031,#1032,#1033,#1034,#1035,#1036),.UNSPECIFIED.,.F.,.F.,(4,2,2,2,2,2,2,2,2,2,2,2,2,2,2,
4),(0.,0.247992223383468,0.495972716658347,0.743784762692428,0.991593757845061,1.48701674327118,
1.98230986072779,2.47751685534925,2.97295059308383,3.46860427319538,3.96352840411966,
4.23382992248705,4.50409174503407,4.86279314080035,5.22129214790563,5.35828916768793),.UNSPECIFIED.);
#1038=EDGE_CURVE('E393',#961,#1002,#1037,.T.);
#1039=ORIENTED_EDGE('',*,*,#1038,.F.);
#1040=EDGE_LOOP('',(#963,#1000,#1004,#1039));
#1041=FACE_BOUND('',#1040,.T.);
#1042=ADVANCED_FACE('F368',(#1041),#95,.F.);
#1043=CARTESIAN_POINT('',(0.,9.5,0.));
#1044=DIRECTION('',(0.,1.,0.));
#1045=DIRECTION('',(0.,0.,-1.));
#1046=AXIS2_PLACEMENT_3D('',#1043,#1044,#1045);
#1047=SPHERICAL_SURFACE('',#1046,2.95);
#1048=CARTESIAN_POINT('',(0.277701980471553,12.4368999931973,-0.0002));
#1049=CARTESIAN_POINT('',(0.277702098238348,12.4369136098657,0.0824851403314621));
#1050=CARTESIAN_POINT('',(0.277663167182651,12.4334231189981,0.165166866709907));
#1051=CARTESIAN_POINT('',(0.27750764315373,12.4194953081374,0.329940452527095));
#1052=CARTESIAN_POINT('',(0.277391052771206,12.4090582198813,0.412032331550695));
#1053=CARTESIAN_POINT('',(0.277080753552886,12.3813082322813,0.57499217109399));
#1054=CARTESIAN_POINT('',(0.276887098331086,12.3640001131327,0.655860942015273));
#1055=CARTESIAN_POINT('',(0.276423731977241,12.3226478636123,0.815832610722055));
#1056=CARTESIAN_POINT('',(0.276154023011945,12.2986039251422,0.894935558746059));
#1057=CARTESIAN_POINT('',(0.275231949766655,12.2165531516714,1.12887100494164));
#1058=CARTESIAN_POINT('',(0.274466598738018,12.1486237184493,1.2803513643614));
#1059=CARTESIAN_POINT('',(0.272650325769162,11.9883493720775,1.56959083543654));
#1060=CARTESIAN_POINT('',(0.271599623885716,11.8960232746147,1.70736040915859));
#1061=CARTESIAN_POINT('',(0.269583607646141,11.7201643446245,1.92723825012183));
#1062=CARTESIAN_POINT('',(0.26868475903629,11.6420907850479,2.01376675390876));
#1063=CARTESIAN_POINT('',(0.266765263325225,11.4763181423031,2.17693738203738));
#1064=CARTESIAN_POINT('',(0.265744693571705,11.3886251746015,2.2535857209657));
#1065=CARTESIAN_POINT('',(0.26466731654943,11.2966416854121,2.32476447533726));
#1066=B_SPLINE_CURVE_WITH_KNOTS('',3,(#1048,#1049,#1050,#1051,#1052,#1053,#1054,#1055,#1056,
#1057,#1058,#1059,#1060,#1061,#1062,#1063,#1064,#1065),.UNSPECIFIED.,.F.,.F.,(4,2,2,2,2,2,2,2,
4),(0.,0.24797496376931,0.495941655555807,0.743736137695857,0.991523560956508,1.4870345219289,
1.98216443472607,2.33102949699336,2.67967404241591),.UNSPECIFIED.);
#1067=CARTESIAN_POINT('',(0.277701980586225,12.4369,0.));
#1068=VERTEX_POINT('',#1067);
#1069=CARTESIAN_POINT('',(0.264670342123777,11.2969,2.32456447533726));
#1070=VERTEX_POINT('',#1069);
#1071=EDGE_CURVE('E382',#1068,#1070,#1066,.T.);
#1072=ORIENTED_EDGE('',*,*,#1071,.T.);
#1073=CARTESIAN_POINT('',(0.266750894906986,11.2968510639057,2.32436447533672));
#1074=CARTESIAN_POINT('',(0.177833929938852,11.2989503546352,2.33292094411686));
#1075=CARTESIAN_POINT('',(0.0889169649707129,11.3,2.33719917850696));
#1076=CARTESIAN_POINT('',(-0.0889169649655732,11.3,2.33719917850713));
#1077=CARTESIAN_POINT('',(-0.17783392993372,11.2989503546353,2.33292094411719));
#1078=CARTESIAN_POINT('',(-0.266750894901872,11.2968510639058,2.32436447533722));
#1079=B_SPLINE_CURVE_WITH_KNOTS('',3,(#1073,#1074,#1075,#1076,#1077,#1078),.UNSPECIFIED.,.F.,
.F.,(4,2,4),(0.,0.267078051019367,0.534156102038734),.UNSPECIFIED.);
#1080=EDGE_CURVE('E352',#1070,#30,#1079,.T.);
#1081=ORIENTED_EDGE('',*,*,#1080,.T.);
#1082=ORIENTED_EDGE('',*,*,#86,.T.);
#1083=CARTESIAN_POINT('',(-0.277701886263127,12.4369000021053,0.000199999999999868));
#1084=CARTESIAN_POINT('',(-0.277735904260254,12.4368986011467,-0.0128250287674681));
#1085=CARTESIAN_POINT('',(-0.27652841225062,12.4369262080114,-0.0258344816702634));
#1086=CARTESIAN_POINT('',(-0.271806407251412,12.4370306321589,-0.0513664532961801));
#1087=CARTESIAN_POINT('',(-0.268302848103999,12.4371072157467,-0.0638909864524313));
#1088=CARTESIAN_POINT('',(-0.259166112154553,12.4373008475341,-0.0881169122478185));
#1089=CARTESIAN_POINT('',(-0.253534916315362,12.437417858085,-0.0998190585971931));
#1090=CARTESIAN_POINT('',(-0.240409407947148,12.4376785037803,-0.122130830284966));
#1091=CARTESIAN_POINT('',(-0.232913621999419,12.4378221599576,-0.132739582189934));
#1092=CARTESIAN_POINT('',(-0.21628523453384,12.4381224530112,-0.152734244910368));
#1093=CARTESIAN_POINT('',(-0.207138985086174,12.4382791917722,-0.162108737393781));
#1094=CARTESIAN_POINT('',(-0.187559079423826,12.4385898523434,-0.179393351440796));
#1095=CARTESIAN_POINT('',(-0.177125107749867,12.4387437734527,-0.18730311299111));
#1096=CARTESIAN_POINT('',(-0.153890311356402,12.4390541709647,-0.202469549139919));
#1097=CARTESIAN_POINT('',(-0.140956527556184,12.43920858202,-0.209522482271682));
#1098=CARTESIAN_POINT('',(-0.114183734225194,12.4394831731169,-0.2216233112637));
#1099=CARTESIAN_POINT('',(-0.100344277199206,12.4396033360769,-0.22667020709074));
#1100=CARTESIAN_POINT('',(-0.0703947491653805,12.4398108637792,-0.235217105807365));
#1101=CARTESIAN_POINT('',(-0.0542110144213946,12.4398925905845,-0.238460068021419));
#1102=CARTESIAN_POINT('',(-0.0215336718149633,12.4399921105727,-0.242391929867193));
#1103=CARTESIAN_POINT('',(-0.00503992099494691,12.440009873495,-0.243079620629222));
#1104=CARTESIAN_POINT('',(0.029076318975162,12.4399785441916,-0.241853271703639));
#1105=CARTESIAN_POINT('',(0.0466921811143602,12.4399244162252,-0.239743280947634));
#1106=CARTESIAN_POINT('',(0.0813217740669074,12.4397462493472,-0.232575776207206));
#1107=CARTESIAN_POINT('',(0.0983353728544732,12.4396221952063,-0.227517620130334));
#1108=CARTESIAN_POINT('',(0.131067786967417,12.4393201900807,-0.214535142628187));
#1109=CARTESIAN_POINT('',(0.14679665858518,12.4391427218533,-0.206636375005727));
#1110=CARTESIAN_POINT('',(0.176512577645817,12.4387565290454,-0.188042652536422));
#1111=CARTESIAN_POINT('',(0.190500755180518,12.4385478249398,-0.177349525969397));
#1112=CARTESIAN_POINT('',(0.214810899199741,12.438150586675,-0.154525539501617));
#1113=CARTESIAN_POINT('',(0.225356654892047,12.4379620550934,-0.142633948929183));
#1114=CARTESIAN_POINT('',(0.243917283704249,12.4376119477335,-0.117004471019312));
#1115=CARTESIAN_POINT('',(0.251933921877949,12.4374503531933,-0.103267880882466));
#1116=CARTESIAN_POINT('',(0.264026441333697,12.43719910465,-0.0764074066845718));
#1117=CARTESIAN_POINT('',(0.268492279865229,12.4371026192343,-0.0634583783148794));
#1118=CARTESIAN_POINT('',(0.274893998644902,12.4369628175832,-0.0369737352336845));
#1119=CARTESIAN_POINT('',(0.27683793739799,12.4369193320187,-0.0234401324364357));
#1120=CARTESIAN_POINT('',(0.277629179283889,12.4369016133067,-0.00651308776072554));
#1121=CARTESIAN_POINT('',(0.277705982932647,12.4368998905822,-0.00315564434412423));
#1122=CARTESIAN_POINT('',(0.277701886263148,12.4369000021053,0.000199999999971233));
#1123=B_SPLINE_CURVE_WITH_KNOTS('',3,(#1083,#1084,#1085,#1086,#1087,#1088,#1089,#1090,#1091,
#1092,#1093,#1094,#1095,#1096,#1097,#1098,#1099,#1100,#1101,#1102,#1103,#1104,#1105,#1106,#1107,
#1108,#1109,#1110,#1111,#1112,#1113,#1114,#1115,#1116,#1117,#1118,#1119,#1120,#1121,#1122),
.UNSPECIFIED.,.F.,.F.,(4,2,2,2,2,2,2,2,2,2,2,2,2,2,2,2,2,2,2,4),(0.,0.0389918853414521,
0.077799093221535,0.116570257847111,0.155372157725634,0.194510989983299,0.233659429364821,
0.277679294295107,0.321721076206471,0.371027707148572,0.420357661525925,0.47333177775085,
0.526317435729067,0.578837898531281,0.631324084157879,0.678731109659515,0.726104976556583,
0.766973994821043,0.807712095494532,0.817782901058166),.UNSPECIFIED.);
#1124=EDGE_CURVE('E269',#64,#1068,#1123,.T.);
#1125=ORIENTED_EDGE('',*,*,#1124,.T.);
#1126=EDGE_LOOP('',(#1072,#1081,#1082,#1125));
#1127=FACE_BOUND('',#1126,.T.);
#1128=ORIENTED_EDGE('',*,*,#1038,.T.);
#1129=CARTESIAN_POINT('',(0.220190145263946,7.69685106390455,-2.32436447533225));
#1130=CARTESIAN_POINT('',(0.1467934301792,7.69895035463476,-2.33292094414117));
#1131=CARTESIAN_POINT('',(0.0733967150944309,7.69999999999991,-2.33719917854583));
#1132=CARTESIAN_POINT('',(-0.0733967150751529,7.70000000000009,-2.33719917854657));
#1133=CARTESIAN_POINT('',(-0.146793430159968,7.69895035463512,-2.33292094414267));
#1134=CARTESIAN_POINT('',(-0.220190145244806,7.6968510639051,-2.32436447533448));
#1135=B_SPLINE_CURVE_WITH_KNOTS('',3,(#1129,#1130,#1131,#1132,#1133,#1134),.UNSPECIFIED.,.F.,
.F.,(4,2,4),(0.,0.220586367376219,0.441172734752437),.UNSPECIFIED.);
#1136=CARTESIAN_POINT('',(-0.21847285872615,7.6969,-2.32456447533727));
#1137=VERTEX_POINT('',#1136);
#1138=EDGE_CURVE('E398',#1002,#1137,#1135,.T.);
#1139=ORIENTED_EDGE('',*,*,#1138,.T.);
#1140=CARTESIAN_POINT('',(-0.218476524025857,7.69715831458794,-2.32476447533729));
#1141=CARTESIAN_POINT('',(-0.217548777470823,7.63177085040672,-2.27415407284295));
#1142=CARTESIAN_POINT('',(-0.21664550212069,7.56853115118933,-2.22077502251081));
#1143=CARTESIAN_POINT('',(-0.214896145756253,7.44677157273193,-2.10888540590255));
#1144=CARTESIAN_POINT('',(-0.21405006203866,7.38825147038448,-2.05037508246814));
#1145=CARTESIAN_POINT('',(-0.212423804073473,7.27638711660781,-1.92866518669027));
#1146=CARTESIAN_POINT('',(-0.211643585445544,7.2230393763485,-1.86546882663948));
#1147=CARTESIAN_POINT('',(-0.210156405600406,7.12186323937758,-1.73483020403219));
#1148=CARTESIAN_POINT('',(-0.209449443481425,7.07403477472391,-1.66738799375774));
#1149=CARTESIAN_POINT('',(-0.207449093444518,6.93931230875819,-1.45931209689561));
#1150=CARTESIAN_POINT('',(-0.206275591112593,6.86113673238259,-1.31288063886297));
#1151=CARTESIAN_POINT('',(-0.204303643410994,6.73054586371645,-1.00908566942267));
#1152=CARTESIAN_POINT('',(-0.203505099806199,6.67812382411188,-0.851725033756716));
#1153=CARTESIAN_POINT('',(-0.202318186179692,6.60043258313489,-0.530443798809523));
#1154=CARTESIAN_POINT('',(-0.201929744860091,6.57515866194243,-0.366524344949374));
#1155=CARTESIAN_POINT('',(-0.201581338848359,6.55248284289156,-0.036693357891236));
#1156=CARTESIAN_POINT('',(-0.201621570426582,6.55509371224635,0.129219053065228));
#1157=CARTESIAN_POINT('',(-0.202128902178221,6.58813242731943,0.458305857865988));
#1158=CARTESIAN_POINT('',(-0.202596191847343,6.6185726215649,0.621479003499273));
#1159=CARTESIAN_POINT('',(-0.203935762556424,6.70641031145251,0.940223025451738));
#1160=CARTESIAN_POINT('',(-0.204807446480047,6.76376806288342,1.09580473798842));
#1161=CARTESIAN_POINT('',(-0.206435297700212,6.87187044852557,1.32701813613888));
#1162=CARTESIAN_POINT('',(-0.207064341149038,6.91380178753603,1.40688828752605));
#1163=CARTESIAN_POINT('',(-0.208422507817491,7.0048176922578,1.56244542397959));
#1164=CARTESIAN_POINT('',(-0.20915161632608,7.05390120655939,1.63813302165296));
#1165=CARTESIAN_POINT('',(-0.210954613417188,7.17599722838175,1.80867878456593));
#1166=CARTESIAN_POINT('',(-0.212063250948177,7.25158412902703,1.90170534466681));
#1167=CARTESIAN_POINT('',(-0.214417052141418,7.41349721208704,2.07781658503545));
#1168=CARTESIAN_POINT('',(-0.215662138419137,7.4998173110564,2.16090684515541));
#1169=CARTESIAN_POINT('',(-0.217459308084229,7.62559514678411,2.26802026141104));
#1170=CARTESIAN_POINT('',(-0.217964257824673,7.66105451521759,2.29681885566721));
#1171=CARTESIAN_POINT('',(-0.218476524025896,7.69715831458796,2.32476447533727));
#1172=B_SPLINE_CURVE_WITH_KNOTS('',3,(#1140,#1141,#1142,#1143,#1144,#1145,#1146,#1147,#1148,
#1149,#1150,#1151,#1152,#1153,#1154,#1155,#1156,#1157,#1158,#1159,#1160,#1161,#1162,#1163,#1164,
#1165,#1166,#1167,#1168,#1169,#1170,#1171),.UNSPECIFIED.,.F.,.F.,(4,2,2,2,2,2,2,2,2,2,2,2,2,2,2,
4),(0.,0.247992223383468,0.495972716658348,0.743784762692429,0.991593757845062,1.48701674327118,
1.98230986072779,2.47751685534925,2.97295059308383,3.46860427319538,3.96352840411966,
4.23382992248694,4.50409174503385,4.86279314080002,5.22129214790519,5.35828916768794),.UNSPECIFIED.);
#1173=CARTESIAN_POINT('',(-0.218472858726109,7.6969,2.32456447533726));
#1174=VERTEX_POINT('',#1173);
#1175=EDGE_CURVE('E351',#1137,#1174,#1172,.T.);
#1176=ORIENTED_EDGE('',*,*,#1175,.T.);
#1177=CARTESIAN_POINT('',(-0.220190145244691,7.6968510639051,2.32436447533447));
#1178=CARTESIAN_POINT('',(-0.146793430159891,7.69895035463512,2.33292094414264));
#1179=CARTESIAN_POINT('',(-0.0733967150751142,7.70000000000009,2.33719917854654));
#1180=CARTESIAN_POINT('',(0.0733967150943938,7.69999999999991,2.3371991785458));
#1181=CARTESIAN_POINT('',(0.146793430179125,7.69895035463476,2.33292094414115));
#1182=CARTESIAN_POINT('',(0.220190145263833,7.69685106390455,2.32436447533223));
#1183=B_SPLINE_CURVE_WITH_KNOTS('',3,(#1177,#1178,#1179,#1180,#1181,#1182),.UNSPECIFIED.,.F.,
.F.,(4,2,4),(0.,0.220586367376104,0.441172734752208),.UNSPECIFIED.);
#1184=EDGE_CURVE('E343',#1174,#961,#1183,.T.);
#1185=ORIENTED_EDGE('',*,*,#1184,.T.);
#1186=EDGE_LOOP('',(#1128,#1139,#1176,#1185));
#1187=FACE_BOUND('',#1186,.T.);
#1188=ADVANCED_FACE('F362',(#1127,#1187),#1047,.T.);
#1189=CARTESIAN_POINT('',(0.,14.,3.99999999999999));
#1190=DIRECTION('',(0.,0.,-1.));
#1191=DIRECTION('',(-1.,0.,0.));
#1192=AXIS2_PLACEMENT_3D('',#1189,#1190,#1191);
#1193=PLANE('',#1192);
#1194=CARTESIAN_POINT('',(0.,0.,3.99999999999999));
#1195=DIRECTION('',(0.,0.,-1.));
#1196=DIRECTION('',(-1.,0.,0.));
#1197=AXIS2_PLACEMENT_3D('',#1194,#1195,#1196);
#1198=CIRCLE('',#1197,13.5);
#1199=CARTESIAN_POINT('',(-13.5,0.,3.99999999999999));
#1200=VERTEX_POINT('',#1199);
#1201=EDGE_CURVE('E988',#1200,#1200,#1198,.F.);
#1202=ORIENTED_EDGE('',*,*,#1201,.T.);
#1203=EDGE_LOOP('',(#1202));
#1204=FACE_BOUND('',#1203,.T.);
#1205=CARTESIAN_POINT('',(0.,0.,3.99999999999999));
#1206=DIRECTION('',(0.,0.,1.));
#1207=DIRECTION('',(1.,0.,0.));
#1208=AXIS2_PLACEMENT_3D('',#1205,#1206,#1207);
#1209=CIRCLE('',#1208,11.3);
#1210=CARTESIAN_POINT('',(11.3,0.,3.99999999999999));
#1211=VERTEX_POINT('',#1210);
#1212=EDGE_CURVE('E265',#1211,#1211,#1209,.T.);
#1213=ORIENTED_EDGE('',*,*,#1212,.F.);
#1214=EDGE_LOOP('',(#1213));
#1215=FACE_BOUND('',#1214,.T.);
#1216=ADVANCED_FACE('F367',(#1204,#1215),#1193,.F.);
#1217=CARTESIAN_POINT('',(0.,0.,50.3916163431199));
#1218=DIRECTION('',(0.,0.,1.));
#1219=DIRECTION('',(1.,0.,0.));
#1220=AXIS2_PLACEMENT_3D('',#1217,#1218,#1219);
#1221=CYLINDRICAL_SURFACE('',#1220,11.3);
#1222=ORIENTED_EDGE('',*,*,#222,.F.);
#1223=CARTESIAN_POINT('',(-7.79945862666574,8.17670136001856,2.32436447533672));
#1224=CARTESIAN_POINT('',(-7.86381683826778,8.1153119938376,2.33292094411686));
#1225=CARTESIAN_POINT('',(-7.92743283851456,8.05318041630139,2.33719917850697));
#1226=CARTESIAN_POINT('',(-8.05318041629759,7.92743283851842,2.33719917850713));
#1227=CARTESIAN_POINT('',(-8.11531199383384,7.86381683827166,2.33292094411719));
#1228=CARTESIAN_POINT('',(-8.17670136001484,7.79945862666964,2.32436447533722));
#1229=B_SPLINE_CURVE_WITH_KNOTS('',3,(#1223,#1224,#1225,#1226,#1227,#1228),.UNSPECIFIED.,.F.,
.F.,(4,2,4),(0.,0.267078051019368,0.534156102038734),.UNSPECIFIED.);
#1230=EDGE_CURVE('E244',#32,#217,#1229,.T.);
#1231=ORIENTED_EDGE('',*,*,#1230,.F.);
#1232=ORIENTED_EDGE('',*,*,#33,.F.);
#1233=ORIENTED_EDGE('',*,*,#1080,.F.);
#1234=CARTESIAN_POINT('',(7.80096440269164,8.17526479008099,2.32456447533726));
#1235=VERTEX_POINT('',#1234);
#1236=EDGE_CURVE('E267',#1235,#1070,#28,.T.);
#1237=ORIENTED_EDGE('',*,*,#1236,.F.);
#1238=CARTESIAN_POINT('',(8.17670136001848,7.79945862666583,2.32436447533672));
#1239=CARTESIAN_POINT('',(8.11531199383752,7.86381683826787,2.33292094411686));
#1240=CARTESIAN_POINT('',(8.0531804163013,7.92743283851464,2.33719917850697));
#1241=CARTESIAN_POINT('',(7.92743283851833,8.05318041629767,2.33719917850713));
#1242=CARTESIAN_POINT('',(7.86381683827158,8.11531199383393,2.33292094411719));
#1243=CARTESIAN_POINT('',(7.79945862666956,8.17670136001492,2.32436447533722));
#1244=B_SPLINE_CURVE_WITH_KNOTS('',3,(#1238,#1239,#1240,#1241,#1242,#1243),.UNSPECIFIED.,.F.,
.F.,(4,2,4),(0.,0.267078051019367,0.534156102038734),.UNSPECIFIED.);
#1245=EDGE_CURVE('E520',#931,#1235,#1244,.T.);
#1246=ORIENTED_EDGE('',*,*,#1245,.F.);
#1247=ORIENTED_EDGE('',*,*,#932,.F.);
#1248=CARTESIAN_POINT('',(11.2968510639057,-0.266750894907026,2.32436447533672));
#1249=CARTESIAN_POINT('',(11.2989503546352,-0.177833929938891,2.33292094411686));
#1250=CARTESIAN_POINT('',(11.3,-0.0889169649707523,2.33719917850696));
#1251=CARTESIAN_POINT('',(11.3,0.0889169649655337,2.33719917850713));
#1252=CARTESIAN_POINT('',(11.2989503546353,0.177833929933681,2.33292094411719));
#1253=CARTESIAN_POINT('',(11.2968510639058,0.266750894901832,2.32436447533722));
#1254=B_SPLINE_CURVE_WITH_KNOTS('',3,(#1248,#1249,#1250,#1251,#1252,#1253),.UNSPECIFIED.,.F.,
.F.,(4,2,4),(0.,0.267078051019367,0.534156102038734),.UNSPECIFIED.);
#1255=EDGE_CURVE('E588',#789,#927,#1254,.T.);
#1256=ORIENTED_EDGE('',*,*,#1255,.F.);
#1257=ORIENTED_EDGE('',*,*,#790,.F.);
#1258=CARTESIAN_POINT('',(7.7994586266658,-8.17670136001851,2.32436447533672));
#1259=CARTESIAN_POINT('',(7.86381683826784,-8.11531199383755,2.33292094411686));
#1260=CARTESIAN_POINT('',(7.92743283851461,-8.05318041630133,2.33719917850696));
#1261=CARTESIAN_POINT('',(8.05318041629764,-7.92743283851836,2.33719917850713));
#1262=CARTESIAN_POINT('',(8.1153119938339,-7.86381683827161,2.33292094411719));
#1263=CARTESIAN_POINT('',(8.17670136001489,-7.79945862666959,2.32436447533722));
#1264=B_SPLINE_CURVE_WITH_KNOTS('',3,(#1258,#1259,#1260,#1261,#1262,#1263),.UNSPECIFIED.,.F.,
.F.,(4,2,4),(0.,0.267078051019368,0.534156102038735),.UNSPECIFIED.);
#1265=EDGE_CURVE('E873',#647,#785,#1264,.T.);
#1266=ORIENTED_EDGE('',*,*,#1265,.F.);
#1267=ORIENTED_EDGE('',*,*,#648,.F.);
#1268=CARTESIAN_POINT('',(-0.266750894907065,-11.2968510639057,2.32436447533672));
#1269=CARTESIAN_POINT('',(-0.177833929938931,-11.2989503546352,2.33292094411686));
#1270=CARTESIAN_POINT('',(-0.0889169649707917,-11.3,2.33719917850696));
#1271=CARTESIAN_POINT('',(0.0889169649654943,-11.3,2.33719917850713));
#1272=CARTESIAN_POINT('',(0.177833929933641,-11.2989503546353,2.33292094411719));
#1273=CARTESIAN_POINT('',(0.266750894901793,-11.2968510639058,2.32436447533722));
#1274=B_SPLINE_CURVE_WITH_KNOTS('',3,(#1268,#1269,#1270,#1271,#1272,#1273),.UNSPECIFIED.,.F.,
.F.,(4,2,4),(0.,0.267078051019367,0.534156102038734),.UNSPECIFIED.);
#1275=EDGE_CURVE('E811',#505,#643,#1274,.T.);
#1276=ORIENTED_EDGE('',*,*,#1275,.F.);
#1277=ORIENTED_EDGE('',*,*,#506,.F.);
#1278=CARTESIAN_POINT('',(-8.17670136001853,-7.79945862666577,2.32436447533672));
#1279=CARTESIAN_POINT('',(-8.11531199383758,-7.86381683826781,2.33292094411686));
#1280=CARTESIAN_POINT('',(-8.05318041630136,-7.92743283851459,2.33719917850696));
#1281=CARTESIAN_POINT('',(-7.92743283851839,-8.05318041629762,2.33719917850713));
#1282=CARTESIAN_POINT('',(-7.86381683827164,-8.11531199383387,2.33292094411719));
#1283=CARTESIAN_POINT('',(-7.79945862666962,-8.17670136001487,2.32436447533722));
#1284=B_SPLINE_CURVE_WITH_KNOTS('',3,(#1278,#1279,#1280,#1281,#1282,#1283),.UNSPECIFIED.,.F.,
.F.,(4,2,4),(0.,0.267078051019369,0.534156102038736),.UNSPECIFIED.);
#1285=EDGE_CURVE('E746',#363,#501,#1284,.T.);
#1286=ORIENTED_EDGE('',*,*,#1285,.F.);
#1287=ORIENTED_EDGE('',*,*,#364,.F.);
#1288=CARTESIAN_POINT('',(-11.2968510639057,0.266750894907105,2.32436447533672));
#1289=CARTESIAN_POINT('',(-11.2989503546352,0.17783392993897,2.33292094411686));
#1290=CARTESIAN_POINT('',(-11.3,0.0889169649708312,2.33719917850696));
#1291=CARTESIAN_POINT('',(-11.3,-0.0889169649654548,2.33719917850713));
#1292=CARTESIAN_POINT('',(-11.2989503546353,-0.177833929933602,2.33292094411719));
#1293=CARTESIAN_POINT('',(-11.2968510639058,-0.266750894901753,2.32436447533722));
#1294=B_SPLINE_CURVE_WITH_KNOTS('',3,(#1288,#1289,#1290,#1291,#1292,#1293),.UNSPECIFIED.,.F.,
.F.,(4,2,4),(0.,0.267078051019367,0.534156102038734),.UNSPECIFIED.);
#1295=EDGE_CURVE('E675',#221,#359,#1294,.T.);
#1296=ORIENTED_EDGE('',*,*,#1295,.F.);
#1297=EDGE_LOOP('',(#1222,#1231,#1232,#1233,#1237,#1246,#1247,#1256,#1257,#1266,#1267,#1276,
#1277,#1286,#1287,#1296));
#1298=FACE_BOUND('',#1297,.T.);
#1299=ORIENTED_EDGE('',*,*,#1212,.T.);
#1300=EDGE_LOOP('',(#1299));
#1301=FACE_BOUND('',#1300,.T.);
#1302=ADVANCED_FACE('F255',(#1298,#1301),#1221,.F.);
#1303=CARTESIAN_POINT('',(8.59785137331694,8.99058128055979,0.));
#1304=VERTEX_POINT('',#1303);
#1305=EDGE_CURVE('E281',#1304,#1068,#62,.T.);
#1306=ORIENTED_EDGE('',*,*,#1305,.F.);
#1307=CARTESIAN_POINT('',(7.80078388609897,8.17507999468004,2.32476447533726));
#1308=CARTESIAN_POINT('',(7.84647821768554,8.22185742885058,2.27415420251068));
#1309=CARTESIAN_POINT('',(7.89067399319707,8.26709603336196,2.22077514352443));
#1310=CARTESIAN_POINT('',(7.97577144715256,8.35419367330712,2.10888477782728));
#1311=CARTESIAN_POINT('',(8.01667323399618,8.39605281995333,2.050373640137));
#1312=CARTESIAN_POINT('',(8.09486179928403,8.47606515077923,1.92866304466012));
#1313=CARTESIAN_POINT('',(8.13215105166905,8.51422087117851,1.86546684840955));
#1314=CARTESIAN_POINT('',(8.20287357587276,8.58658168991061,1.73482862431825));
#1315=CARTESIAN_POINT('',(8.23630695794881,8.620786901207,1.66738671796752));
#1316=CARTESIAN_POINT('',(8.33050048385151,8.71714920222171,1.45928173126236));
#1317=CARTESIAN_POINT('',(8.38516402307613,8.77306320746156,1.31282376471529));
#1318=CARTESIAN_POINT('',(8.47645806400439,8.86643881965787,1.00899965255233));
#1319=CARTESIAN_POINT('',(8.51310244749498,8.9039146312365,0.851642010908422));
#1320=CARTESIAN_POINT('',(8.55937824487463,8.95123877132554,0.577980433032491));
#1321=CARTESIAN_POINT('',(8.57379247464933,8.96597891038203,0.463288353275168));
#1322=CARTESIAN_POINT('',(8.59303746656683,8.98565869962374,0.232345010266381));
#1323=CARTESIAN_POINT('',(8.59787425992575,8.99060451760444,0.11609477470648));
#1324=CARTESIAN_POINT('',(8.59785136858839,8.99058127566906,-0.000199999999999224));
#1325=B_SPLINE_CURVE_WITH_KNOTS('',3,(#1307,#1308,#1309,#1310,#1311,#1312,#1313,#1314,#1315,
#1316,#1317,#1318,#1319,#1320,#1321,#1322,#1323,#1324),.UNSPECIFIED.,.F.,.F.,(4,2,2,2,2,2,2,2,
4),(0.,0.247987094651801,0.495966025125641,0.743773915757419,0.991574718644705,1.4871135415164,
1.9822700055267,2.33108183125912,2.67967392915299),.UNSPECIFIED.);
#1326=EDGE_CURVE('E517',#1235,#1304,#1325,.T.);
#1327=ORIENTED_EDGE('',*,*,#1326,.F.);
#1328=ORIENTED_EDGE('',*,*,#1236,.T.);
#1329=ORIENTED_EDGE('',*,*,#1071,.F.);
#1330=EDGE_LOOP('',(#1306,#1327,#1328,#1329));
#1331=FACE_BOUND('',#1330,.T.);
#1332=ADVANCED_FACE('F433',(#1331),#23,.F.);
#1333=CARTESIAN_POINT('',(0.,0.,50.3916163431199));
#1334=DIRECTION('',(0.,0.,1.));
#1335=DIRECTION('',(1.,0.,0.));
#1336=AXIS2_PLACEMENT_3D('',#1333,#1334,#1335);
#1337=CYLINDRICAL_SURFACE('',#1336,12.44);
#1338=ORIENTED_EDGE('',*,*,#65,.T.);
#1339=CARTESIAN_POINT('',(-8.99058121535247,8.59785144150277,0.000199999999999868));
#1340=CARTESIAN_POINT('',(-8.9906042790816,8.59782639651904,-0.0128250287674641));
#1341=CARTESIAN_POINT('',(-8.98976997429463,8.59869974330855,-0.0258344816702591));
#1342=CARTESIAN_POINT('',(-8.98650485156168,8.60211254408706,-0.0513664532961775));
#1343=CARTESIAN_POINT('',(-8.98408161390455,8.60464408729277,-0.0638909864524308));
#1344=CARTESIAN_POINT('',(-8.9777578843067,8.61124165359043,-0.0881169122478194));
#1345=CARTESIAN_POINT('',(-8.97385876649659,8.6153062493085,-0.0998190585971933));
#1346=CARTESIAN_POINT('',(-8.96476193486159,8.62477168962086,-0.122130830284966));
#1347=CARTESIAN_POINT('',(-8.9595631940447,8.6301735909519,-0.132739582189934));
#1348=CARTESIAN_POINT('',(-8.94801748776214,8.64214397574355,-0.152734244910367));
#1349=CARTESIAN_POINT('',(-8.94166094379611,8.64872218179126,-0.16210873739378));
#1350=CARTESIAN_POINT('',(-8.92803552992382,8.66278693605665,-0.179393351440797));
#1351=CARTESIAN_POINT('',(-8.92076643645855,8.6702737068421,-0.187303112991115));
#1352=CARTESIAN_POINT('',(-8.90455643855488,8.68692267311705,-0.202469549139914));
#1353=CARTESIAN_POINT('',(-8.89552005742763,8.69617742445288,-0.209522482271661));
#1354=CARTESIAN_POINT('',(-8.87678299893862,8.71530281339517,-0.221623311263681));
#1355=CARTESIAN_POINT('',(-8.86708199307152,8.7251737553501,-0.226670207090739));
#1356=CARTESIAN_POINT('',(-8.84605122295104,8.74649801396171,-0.235217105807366));
#1357=CARTESIAN_POINT('',(-8.83466538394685,8.75799943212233,-0.2384600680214));
#1358=CARTESIAN_POINT('',(-8.81162938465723,8.78117617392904,-0.242391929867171));
#1359=CARTESIAN_POINT('',(-8.79997910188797,8.79285157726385,-0.243079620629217));
#1360=CARTESIAN_POINT('',(-8.77583312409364,8.81695324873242,-0.241853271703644));
#1361=CARTESIAN_POINT('',(-8.76333855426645,8.82937127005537,-0.239743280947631));
#1362=CARTESIAN_POINT('',(-8.73872575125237,8.85373210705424,-0.232575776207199));
#1363=CARTESIAN_POINT('',(-8.72660760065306,8.86567481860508,-0.227517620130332));
#1364=CARTESIAN_POINT('',(-8.70324873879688,8.88860658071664,-0.214535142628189));
#1365=CARTESIAN_POINT('',(-8.69200125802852,8.89960308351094,-0.206636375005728));
#1366=CARTESIAN_POINT('',(-8.67071585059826,8.92034233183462,-0.188042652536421));
#1367=CARTESIAN_POINT('',(-8.66067713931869,8.9300858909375,-0.177349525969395));
#1368=CARTESIAN_POINT('',(-8.64320638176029,8.94699486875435,-0.154525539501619));
#1369=CARTESIAN_POINT('',(-8.63561609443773,8.95431853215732,-0.14263394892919));
#1370=CARTESIAN_POINT('',(-8.62224418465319,8.96719531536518,-0.117004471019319));
#1371=CARTESIAN_POINT('',(-8.61646130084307,8.97274966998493,-0.103267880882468));
#1372=CARTESIAN_POINT('',(-8.60773293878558,8.98112271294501,-0.0764074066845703));
#1373=CARTESIAN_POINT('',(-8.6045068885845,8.98421231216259,-0.0634583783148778));
#1374=CARTESIAN_POINT('',(-8.59988133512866,8.98864015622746,-0.0369737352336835));
#1375=CARTESIAN_POINT('',(-8.59847601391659,8.98998397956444,-0.0234401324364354));
#1376=CARTESIAN_POINT('',(-8.59790399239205,8.99053094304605,-0.00651308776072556));
#1377=CARTESIAN_POINT('',(-8.59784846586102,8.99058403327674,-0.00315564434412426));
#1378=CARTESIAN_POINT('',(-8.59785144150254,8.99058121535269,0.000199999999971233));
#1379=B_SPLINE_CURVE_WITH_KNOTS('',3,(#1339,#1340,#1341,#1342,#1343,#1344,#1345,#1346,#1347,
#1348,#1349,#1350,#1351,#1352,#1353,#1354,#1355,#1356,#1357,#1358,#1359,#1360,#1361,#1362,#1363,
#1364,#1365,#1366,#1367,#1368,#1369,#1370,#1371,#1372,#1373,#1374,#1375,#1376,#1377,#1378),
.UNSPECIFIED.,.F.,.F.,(4,2,2,2,2,2,2,2,2,2,2,2,2,2,2,2,2,2,2,4),(0.,0.0389918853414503,
0.0777990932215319,0.116570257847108,0.155372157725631,0.194510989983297,0.233659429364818,
0.277679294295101,0.321721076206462,0.371027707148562,0.420357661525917,0.473331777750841,
0.526317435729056,0.578837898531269,0.631324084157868,0.678731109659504,0.726104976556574,
0.766973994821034,0.807712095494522,0.817782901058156),.UNSPECIFIED.);
#1380=EDGE_CURVE('E245',#192,#55,#1379,.T.);
#1381=ORIENTED_EDGE('',*,*,#1380,.F.);
#1382=ORIENTED_EDGE('',*,*,#195,.T.);
#1383=CARTESIAN_POINT('',(-12.4369000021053,-0.277701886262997,0.000199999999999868));
#1384=CARTESIAN_POINT('',(-12.4368986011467,-0.277735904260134,-0.0128250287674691));
#1385=CARTESIAN_POINT('',(-12.4369262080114,-0.276528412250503,-0.0258344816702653));
#1386=CARTESIAN_POINT('',(-12.4370306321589,-0.271806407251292,-0.0513664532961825));
#1387=CARTESIAN_POINT('',(-12.4371072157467,-0.268302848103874,-0.0638909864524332));
#1388=CARTESIAN_POINT('',(-12.4373008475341,-0.259166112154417,-0.088116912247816));
#1389=CARTESIAN_POINT('',(-12.437417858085,-0.253534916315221,-0.0998190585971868));
#1390=CARTESIAN_POINT('',(-12.4376785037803,-0.240409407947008,-0.12213083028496));
#1391=CARTESIAN_POINT('',(-12.4378221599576,-0.232913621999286,-0.132739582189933));
#1392=CARTESIAN_POINT('',(-12.4381224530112,-0.216285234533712,-0.152734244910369));
#1393=CARTESIAN_POINT('',(-12.4382791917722,-0.207138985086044,-0.16210873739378));
#1394=CARTESIAN_POINT('',(-12.4385898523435,-0.187559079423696,-0.179393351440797));
#1395=CARTESIAN_POINT('',(-12.4387437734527,-0.17712510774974,-0.187303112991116));
#1396=CARTESIAN_POINT('',(-12.4390541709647,-0.15389031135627,-0.202469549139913));
#1397=CARTESIAN_POINT('',(-12.43920858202,-0.140956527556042,-0.209522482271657));
#1398=CARTESIAN_POINT('',(-12.4394831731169,-0.114183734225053,-0.221623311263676));
#1399=CARTESIAN_POINT('',(-12.439603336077,-0.100344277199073,-0.226670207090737));
#1400=CARTESIAN_POINT('',(-12.4398108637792,-0.070394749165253,-0.235217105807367));
#1401=CARTESIAN_POINT('',(-12.4398925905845,-0.0542110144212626,-0.238460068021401));
#1402=CARTESIAN_POINT('',(-12.4399921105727,-0.0215336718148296,-0.242391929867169));
#1403=CARTESIAN_POINT('',(-12.440009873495,-0.00503992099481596,-0.243079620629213));
#1404=CARTESIAN_POINT('',(-12.4399785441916,0.0290763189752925,-0.241853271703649));
#1405=CARTESIAN_POINT('',(-12.4399244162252,0.0466921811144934,-0.239743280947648));
#1406=CARTESIAN_POINT('',(-12.4397462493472,0.0813217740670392,-0.232575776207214));
#1407=CARTESIAN_POINT('',(-12.4396221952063,0.098335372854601,-0.227517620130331));
#1408=CARTESIAN_POINT('',(-12.4393201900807,0.13106778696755,-0.21453514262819));
#1409=CARTESIAN_POINT('',(-12.4391427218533,0.146796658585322,-0.206636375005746));
#1410=CARTESIAN_POINT('',(-12.4387565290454,0.176512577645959,-0.188042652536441));
#1411=CARTESIAN_POINT('',(-12.4385478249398,0.190500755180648,-0.1773495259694));
#1412=CARTESIAN_POINT('',(-12.438150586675,0.214810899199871,-0.154525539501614));
#1413=CARTESIAN_POINT('',(-12.4379620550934,0.225356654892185,-0.142633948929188));
#1414=CARTESIAN_POINT('',(-12.4376119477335,0.243917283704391,-0.117004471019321));
#1415=CARTESIAN_POINT('',(-12.4374503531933,0.251933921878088,-0.10326788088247));
#1416=CARTESIAN_POINT('',(-12.43719910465,0.26402644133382,-0.0764074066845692));
#1417=CARTESIAN_POINT('',(-12.4371026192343,0.268492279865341,-0.0634583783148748));
#1418=CARTESIAN_POINT('',(-12.4369628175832,0.274893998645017,-0.0369737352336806));
#1419=CARTESIAN_POINT('',(-12.4369193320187,0.276837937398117,-0.0234401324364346));
#1420=CARTESIAN_POINT('',(-12.4369016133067,0.27762917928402,-0.00651308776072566));
#1421=CARTESIAN_POINT('',(-12.4368998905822,0.277705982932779,-0.00315564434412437));
#1422=CARTESIAN_POINT('',(-12.4369000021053,0.277701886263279,0.000199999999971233));
#1423=B_SPLINE_CURVE_WITH_KNOTS('',3,(#1383,#1384,#1385,#1386,#1387,#1388,#1389,#1390,#1391,
#1392,#1393,#1394,#1395,#1396,#1397,#1398,#1399,#1400,#1401,#1402,#1403,#1404,#1405,#1406,#1407,
#1408,#1409,#1410,#1411,#1412,#1413,#1414,#1415,#1416,#1417,#1418,#1419,#1420,#1421,#1422),
.UNSPECIFIED.,.F.,.F.,(4,2,2,2,2,2,2,2,2,2,2,2,2,2,2,2,2,2,2,4),(0.,0.0389918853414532,
0.0777990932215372,0.116570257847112,0.155372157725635,0.194510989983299,0.233659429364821,
0.277679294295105,0.321721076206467,0.371027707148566,0.420357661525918,0.473331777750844,
0.526317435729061,0.578837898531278,0.631324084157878,0.678731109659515,0.726104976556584,
0.766973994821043,0.807712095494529,0.817782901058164),.UNSPECIFIED.);
#1424=EDGE_CURVE('E952',#334,#194,#1423,.T.);
#1425=ORIENTED_EDGE('',*,*,#1424,.F.);
#1426=ORIENTED_EDGE('',*,*,#337,.T.);
#1427=CARTESIAN_POINT('',(-8.59785144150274,-8.9905812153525,0.000199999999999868));
#1428=CARTESIAN_POINT('',(-8.59782639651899,-8.99060427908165,-0.01282502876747));
#1429=CARTESIAN_POINT('',(-8.5986997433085,-8.98976997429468,-0.0258344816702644));
#1430=CARTESIAN_POINT('',(-8.60211254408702,-8.98650485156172,-0.0513664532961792));
#1431=CARTESIAN_POINT('',(-8.60464408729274,-8.98408161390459,-0.0638909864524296));
#1432=CARTESIAN_POINT('',(-8.61124165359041,-8.97775788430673,-0.0881169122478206));
#1433=CARTESIAN_POINT('',(-8.61530624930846,-8.97385876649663,-0.0998190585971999));
#1434=CARTESIAN_POINT('',(-8.62477168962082,-8.96476193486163,-0.122130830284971));
#1435=CARTESIAN_POINT('',(-8.63017359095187,-8.95956319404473,-0.132739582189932));
#1436=CARTESIAN_POINT('',(-8.64214397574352,-8.94801748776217,-0.152734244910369));
#1437=CARTESIAN_POINT('',(-8.64872218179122,-8.94166094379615,-0.162108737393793));
#1438=CARTESIAN_POINT('',(-8.6627869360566,-8.92803552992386,-0.179393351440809));
#1439=CARTESIAN_POINT('',(-8.67027370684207,-8.92076643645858,-0.187303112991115));
#1440=CARTESIAN_POINT('',(-8.68692267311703,-8.90455643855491,-0.202469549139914));
#1441=CARTESIAN_POINT('',(-8.69617742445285,-8.89552005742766,-0.209522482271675));
#1442=CARTESIAN_POINT('',(-8.71530281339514,-8.87678299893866,-0.221623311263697));
#1443=CARTESIAN_POINT('',(-8.72517375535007,-8.86708199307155,-0.226670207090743));
#1444=CARTESIAN_POINT('',(-8.74649801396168,-8.84605122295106,-0.235217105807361));
#1445=CARTESIAN_POINT('',(-8.7579994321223,-8.83466538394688,-0.238460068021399));
#1446=CARTESIAN_POINT('',(-8.78117617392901,-8.81162938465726,-0.242391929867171));
#1447=CARTESIAN_POINT('',(-8.79285157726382,-8.79997910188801,-0.243079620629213));
#1448=CARTESIAN_POINT('',(-8.81695324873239,-8.77583312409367,-0.241853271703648));
#1449=CARTESIAN_POINT('',(-8.82937127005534,-8.76333855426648,-0.239743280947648));
#1450=CARTESIAN_POINT('',(-8.85373210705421,-8.73872575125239,-0.232575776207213));
#1451=CARTESIAN_POINT('',(-8.86567481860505,-8.72660760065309,-0.227517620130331));
#1452=CARTESIAN_POINT('',(-8.88860658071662,-8.70324873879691,-0.21453514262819));
#1453=CARTESIAN_POINT('',(-8.89960308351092,-8.69200125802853,-0.206636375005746));
#1454=CARTESIAN_POINT('',(-8.9203423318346,-8.67071585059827,-0.188042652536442));
#1455=CARTESIAN_POINT('',(-8.93008589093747,-8.66067713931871,-0.177349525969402));
#1456=CARTESIAN_POINT('',(-8.94699486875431,-8.64320638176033,-0.154525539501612));
#1457=CARTESIAN_POINT('',(-8.95431853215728,-8.63561609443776,-0.142633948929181));
#1458=CARTESIAN_POINT('',(-8.96719531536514,-8.62224418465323,-0.117004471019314));
#1459=CARTESIAN_POINT('',(-8.97274966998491,-8.6164613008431,-0.103267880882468));
#1460=CARTESIAN_POINT('',(-8.98112271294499,-8.60773293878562,-0.0764074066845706));
#1461=CARTESIAN_POINT('',(-8.98421231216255,-8.60450688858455,-0.0634583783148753));
#1462=CARTESIAN_POINT('',(-8.98864015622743,-8.5998813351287,-0.0369737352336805));
#1463=CARTESIAN_POINT('',(-8.98998397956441,-8.59847601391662,-0.0234401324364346));
#1464=CARTESIAN_POINT('',(-8.99053094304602,-8.59790399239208,-0.00651308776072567));
#1465=CARTESIAN_POINT('',(-8.99058403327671,-8.59784846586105,-0.00315564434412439));
#1466=CARTESIAN_POINT('',(-8.99058121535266,-8.59785144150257,0.000199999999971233));
#1467=B_SPLINE_CURVE_WITH_KNOTS('',3,(#1427,#1428,#1429,#1430,#1431,#1432,#1433,#1434,#1435,
#1436,#1437,#1438,#1439,#1440,#1441,#1442,#1443,#1444,#1445,#1446,#1447,#1448,#1449,#1450,#1451,
#1452,#1453,#1454,#1455,#1456,#1457,#1458,#1459,#1460,#1461,#1462,#1463,#1464,#1465,#1466),
.UNSPECIFIED.,.F.,.F.,(4,2,2,2,2,2,2,2,2,2,2,2,2,2,2,2,2,2,2,4),(0.,0.038991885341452,
0.0777990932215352,0.116570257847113,0.155372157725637,0.194510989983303,0.233659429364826,
0.277679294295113,0.321721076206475,0.371027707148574,0.420357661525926,0.47333177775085,
0.526317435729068,0.578837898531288,0.631324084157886,0.678731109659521,0.72610497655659,
0.766973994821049,0.807712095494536,0.81778290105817),.UNSPECIFIED.);
#1468=EDGE_CURVE('E759',#476,#336,#1467,.T.);
#1469=ORIENTED_EDGE('',*,*,#1468,.F.);
#1470=ORIENTED_EDGE('',*,*,#479,.T.);
#1471=CARTESIAN_POINT('',(0.277701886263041,-12.4369000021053,0.000199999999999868));
#1472=CARTESIAN_POINT('',(0.277735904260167,-12.4368986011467,-0.012825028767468));
#1473=CARTESIAN_POINT('',(0.276528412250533,-12.4369262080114,-0.0258344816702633));
#1474=CARTESIAN_POINT('',(0.271806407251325,-12.4370306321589,-0.0513664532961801));
#1475=CARTESIAN_POINT('',(0.268302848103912,-12.4371072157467,-0.0638909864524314));
#1476=CARTESIAN_POINT('',(0.259166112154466,-12.4373008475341,-0.0881169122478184));
#1477=CARTESIAN_POINT('',(0.253534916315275,-12.437417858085,-0.0998190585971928));
#1478=CARTESIAN_POINT('',(0.240409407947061,-12.4376785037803,-0.122130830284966));
#1479=CARTESIAN_POINT('',(0.232913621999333,-12.4378221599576,-0.132739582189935));
#1480=CARTESIAN_POINT('',(0.216285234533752,-12.4381224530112,-0.152734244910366));
#1481=CARTESIAN_POINT('',(0.207138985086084,-12.4382791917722,-0.162108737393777));
#1482=CARTESIAN_POINT('',(0.187559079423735,-12.4385898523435,-0.179393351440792));
#1483=CARTESIAN_POINT('',(0.17712510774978,-12.4387437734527,-0.18730311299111));
#1484=CARTESIAN_POINT('',(0.153890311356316,-12.4390541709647,-0.202469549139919));
#1485=CARTESIAN_POINT('',(0.140956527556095,-12.43920858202,-0.209522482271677));
#1486=CARTESIAN_POINT('',(0.114183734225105,-12.4394831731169,-0.221623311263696));
#1487=CARTESIAN_POINT('',(0.100344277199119,-12.4396033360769,-0.226670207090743));
#1488=CARTESIAN_POINT('',(0.070394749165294,-12.4398108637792,-0.235217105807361));
#1489=CARTESIAN_POINT('',(0.0542110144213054,-12.4398925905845,-0.238460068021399));
#1490=CARTESIAN_POINT('',(0.0215336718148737,-12.4399921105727,-0.24239192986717));
#1491=CARTESIAN_POINT('',(0.00503992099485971,-12.440009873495,-0.243079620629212));
#1492=CARTESIAN_POINT('',(-0.0290763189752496,-12.4399785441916,-0.24185327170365));
#1493=CARTESIAN_POINT('',(-0.0466921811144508,-12.4399244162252,-0.239743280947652));
#1494=CARTESIAN_POINT('',(-0.081321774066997,-12.4397462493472,-0.232575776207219));
#1495=CARTESIAN_POINT('',(-0.0983353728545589,-12.4396221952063,-0.227517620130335));
#1496=CARTESIAN_POINT('',(-0.131067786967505,-12.4393201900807,-0.214535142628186));
#1497=CARTESIAN_POINT('',(-0.146796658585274,-12.4391427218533,-0.206636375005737));
#1498=CARTESIAN_POINT('',(-0.176512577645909,-12.4387565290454,-0.188042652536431));
#1499=CARTESIAN_POINT('',(-0.1905007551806,-12.4385478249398,-0.177349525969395));
#1500=CARTESIAN_POINT('',(-0.214810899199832,-12.438150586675,-0.154525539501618));
#1501=CARTESIAN_POINT('',(-0.225356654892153,-12.4379620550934,-0.142633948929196));
#1502=CARTESIAN_POINT('',(-0.243917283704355,-12.4376119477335,-0.117004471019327));
#1503=CARTESIAN_POINT('',(-0.251933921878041,-12.4374503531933,-0.10326788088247));
#1504=CARTESIAN_POINT('',(-0.26402644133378,-12.43719910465,-0.0764074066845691));
#1505=CARTESIAN_POINT('',(-0.268492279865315,-12.4371026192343,-0.0634583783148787));
#1506=CARTESIAN_POINT('',(-0.27489399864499,-12.4369628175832,-0.0369737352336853));
#1507=CARTESIAN_POINT('',(-0.276837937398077,-12.4369193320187,-0.0234401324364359));
#1508=CARTESIAN_POINT('',(-0.277629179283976,-12.4369016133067,-0.00651308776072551));
#1509=CARTESIAN_POINT('',(-0.277705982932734,-12.4368998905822,-0.00315564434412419));
#1510=CARTESIAN_POINT('',(-0.277701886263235,-12.4369000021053,0.000199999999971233));
#1511=B_SPLINE_CURVE_WITH_KNOTS('',3,(#1471,#1472,#1473,#1474,#1475,#1476,#1477,#1478,#1479,
#1480,#1481,#1482,#1483,#1484,#1485,#1486,#1487,#1488,#1489,#1490,#1491,#1492,#1493,#1494,#1495,
#1496,#1497,#1498,#1499,#1500,#1501,#1502,#1503,#1504,#1505,#1506,#1507,#1508,#1509,#1510),
.UNSPECIFIED.,.F.,.F.,(4,2,2,2,2,2,2,2,2,2,2,2,2,2,2,2,2,2,2,4),(0.,0.0389918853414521,
0.077799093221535,0.116570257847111,0.155372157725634,0.194510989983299,0.23365942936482,
0.277679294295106,0.321721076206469,0.371027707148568,0.42035766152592,0.473331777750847,
0.526317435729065,0.57883789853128,0.631324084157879,0.678731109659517,0.726104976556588,
0.766973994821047,0.807712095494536,0.81778290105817),.UNSPECIFIED.);
#1512=EDGE_CURVE('E824',#618,#478,#1511,.T.);
#1513=ORIENTED_EDGE('',*,*,#1512,.F.);
#1514=ORIENTED_EDGE('',*,*,#621,.T.);
#1515=CARTESIAN_POINT('',(8.99058121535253,-8.59785144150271,0.000199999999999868));
#1516=CARTESIAN_POINT('',(8.99060427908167,-8.59782639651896,-0.0128250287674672));
#1517=CARTESIAN_POINT('',(8.9897699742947,-8.59869974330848,-0.0258344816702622));
#1518=CARTESIAN_POINT('',(8.98650485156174,-8.60211254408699,-0.0513664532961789));
#1519=CARTESIAN_POINT('',(8.98408161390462,-8.60464408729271,-0.0638909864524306));
#1520=CARTESIAN_POINT('',(8.97775788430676,-8.61124165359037,-0.0881169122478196));
#1521=CARTESIAN_POINT('',(8.97385876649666,-8.61530624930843,-0.0998190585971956));
#1522=CARTESIAN_POINT('',(8.96476193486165,-8.6247716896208,-0.122130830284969));
#1523=CARTESIAN_POINT('',(8.95956319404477,-8.63017359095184,-0.132739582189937));
#1524=CARTESIAN_POINT('',(8.9480174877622,-8.6421439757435,-0.152734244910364));
#1525=CARTESIAN_POINT('',(8.94166094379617,-8.64872218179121,-0.162108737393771));
#1526=CARTESIAN_POINT('',(8.92803552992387,-8.66278693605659,-0.179393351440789));
#1527=CARTESIAN_POINT('',(8.92076643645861,-8.67027370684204,-0.187303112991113));
#1528=CARTESIAN_POINT('',(8.90455643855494,-8.68692267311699,-0.202469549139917));
#1529=CARTESIAN_POINT('',(8.89552005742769,-8.69617742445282,-0.209522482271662));
#1530=CARTESIAN_POINT('',(8.87678299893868,-8.71530281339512,-0.22162331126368));
#1531=CARTESIAN_POINT('',(8.86708199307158,-8.72517375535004,-0.226670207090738));
#1532=CARTESIAN_POINT('',(8.8460512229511,-8.74649801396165,-0.235217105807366));
#1533=CARTESIAN_POINT('',(8.83466538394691,-8.75799943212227,-0.238460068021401));
#1534=CARTESIAN_POINT('',(8.81162938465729,-8.78117617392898,-0.242391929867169));
#1535=CARTESIAN_POINT('',(8.79997910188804,-8.79285157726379,-0.243079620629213));
#1536=CARTESIAN_POINT('',(8.7758331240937,-8.81695324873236,-0.241853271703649));
#1537=CARTESIAN_POINT('',(8.76333855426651,-8.82937127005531,-0.239743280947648));
#1538=CARTESIAN_POINT('',(8.73872575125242,-8.85373210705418,-0.232575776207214));
#1539=CARTESIAN_POINT('',(8.72660760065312,-8.86567481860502,-0.227517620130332));
#1540=CARTESIAN_POINT('',(8.70324873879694,-8.88860658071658,-0.214535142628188));
#1541=CARTESIAN_POINT('',(8.69200125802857,-8.89960308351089,-0.206636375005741));
#1542=CARTESIAN_POINT('',(8.67071585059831,-8.92034233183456,-0.188042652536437));
#1543=CARTESIAN_POINT('',(8.66067713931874,-8.93008589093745,-0.177349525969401));
#1544=CARTESIAN_POINT('',(8.64320638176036,-8.94699486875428,-0.154525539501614));
#1545=CARTESIAN_POINT('',(8.6356160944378,-8.95431853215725,-0.142633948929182));
#1546=CARTESIAN_POINT('',(8.62224418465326,-8.96719531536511,-0.117004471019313));
#1547=CARTESIAN_POINT('',(8.61646130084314,-8.97274966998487,-0.103267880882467));
#1548=CARTESIAN_POINT('',(8.60773293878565,-8.98112271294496,-0.0764074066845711));
#1549=CARTESIAN_POINT('',(8.60450688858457,-8.98421231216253,-0.0634583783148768));
#1550=CARTESIAN_POINT('',(8.59988133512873,-8.9886401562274,-0.0369737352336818));
#1551=CARTESIAN_POINT('',(8.59847601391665,-8.98998397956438,-0.0234401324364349));
#1552=CARTESIAN_POINT('',(8.59790399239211,-8.99053094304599,-0.00651308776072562));
#1553=CARTESIAN_POINT('',(8.59784846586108,-8.99058403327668,-0.00315564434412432));
#1554=CARTESIAN_POINT('',(8.5978514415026,-8.99058121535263,0.000199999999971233));
#1555=B_SPLINE_CURVE_WITH_KNOTS('',3,(#1515,#1516,#1517,#1518,#1519,#1520,#1521,#1522,#1523,
#1524,#1525,#1526,#1527,#1528,#1529,#1530,#1531,#1532,#1533,#1534,#1535,#1536,#1537,#1538,#1539,
#1540,#1541,#1542,#1543,#1544,#1545,#1546,#1547,#1548,#1549,#1550,#1551,#1552,#1553,#1554),
.UNSPECIFIED.,.F.,.F.,(4,2,2,2,2,2,2,2,2,2,2,2,2,2,2,2,2,2,2,4),(0.,0.0389918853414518,
0.0777990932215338,0.11657025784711,0.155372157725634,0.194510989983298,0.233659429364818,
0.277679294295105,0.321721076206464,0.371027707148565,0.420357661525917,0.473331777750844,
0.52631743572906,0.578837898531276,0.631324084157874,0.678731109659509,0.726104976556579,
0.766973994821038,0.807712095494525,0.817782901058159),.UNSPECIFIED.);
#1556=EDGE_CURVE('E886',#760,#620,#1555,.T.);
#1557=ORIENTED_EDGE('',*,*,#1556,.F.);
#1558=ORIENTED_EDGE('',*,*,#763,.T.);
#1559=CARTESIAN_POINT('',(12.4369000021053,0.277701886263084,0.000199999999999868));
#1560=CARTESIAN_POINT('',(12.4368986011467,0.277735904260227,-0.0128250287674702));
#1561=CARTESIAN_POINT('',(12.4369262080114,0.276528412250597,-0.0258344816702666));
#1562=CARTESIAN_POINT('',(12.4370306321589,0.271806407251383,-0.0513664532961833));
#1563=CARTESIAN_POINT('',(12.4371072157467,0.268302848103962,-0.0638909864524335));
#1564=CARTESIAN_POINT('',(12.4373008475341,0.259166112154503,-0.0881169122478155));
#1565=CARTESIAN_POINT('',(12.437417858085,0.253534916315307,-0.0998190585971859));
#1566=CARTESIAN_POINT('',(12.4376785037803,0.240409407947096,-0.122130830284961));
#1567=CARTESIAN_POINT('',(12.4378221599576,0.232913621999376,-0.132739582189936));
#1568=CARTESIAN_POINT('',(12.4381224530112,0.216285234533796,-0.152734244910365));
#1569=CARTESIAN_POINT('',(12.4382791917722,0.20713898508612,-0.162108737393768));
#1570=CARTESIAN_POINT('',(12.4385898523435,0.187559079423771,-0.179393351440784));
#1571=CARTESIAN_POINT('',(12.4387437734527,0.177125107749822,-0.18730311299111));
#1572=CARTESIAN_POINT('',(12.4390541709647,0.153890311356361,-0.20246954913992));
#1573=CARTESIAN_POINT('',(12.43920858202,0.140956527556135,-0.209522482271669));
#1574=CARTESIAN_POINT('',(12.4394831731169,0.114183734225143,-0.221623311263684));
#1575=CARTESIAN_POINT('',(12.4396033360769,0.10034427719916,-0.226670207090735));
#1576=CARTESIAN_POINT('',(12.4398108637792,0.0703947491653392,-0.23521710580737));
#1577=CARTESIAN_POINT('',(12.4398925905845,0.0542110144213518,-0.23846006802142));
#1578=CARTESIAN_POINT('',(12.4399921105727,0.0215336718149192,-0.242391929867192));
#1579=CARTESIAN_POINT('',(12.440009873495,0.00503992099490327,-0.243079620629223));
#1580=CARTESIAN_POINT('',(12.4399785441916,-0.0290763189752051,-0.241853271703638));
#1581=CARTESIAN_POINT('',(12.4399244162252,-0.0466921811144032,-0.23974328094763));
#1582=CARTESIAN_POINT('',(12.4397462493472,-0.0813217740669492,-0.2325757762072));
#1583=CARTESIAN_POINT('',(12.4396221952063,-0.0983353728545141,-0.227517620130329));
#1584=CARTESIAN_POINT('',(12.4393201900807,-0.131067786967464,-0.214535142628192));
#1585=CARTESIAN_POINT('',(12.4391427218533,-0.146796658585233,-0.206636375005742));
#1586=CARTESIAN_POINT('',(12.4387565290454,-0.176512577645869,-0.188042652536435));
#1587=CARTESIAN_POINT('',(12.4385478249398,-0.190500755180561,-0.177349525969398));
#1588=CARTESIAN_POINT('',(12.438150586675,-0.214810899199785,-0.154525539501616));
#1589=CARTESIAN_POINT('',(12.4379620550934,-0.225356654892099,-0.142633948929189));
#1590=CARTESIAN_POINT('',(12.4376119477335,-0.243917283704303,-0.11700447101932));
#1591=CARTESIAN_POINT('',(12.4374503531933,-0.251933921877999,-0.103267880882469));
#1592=CARTESIAN_POINT('',(12.43719910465,-0.264026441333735,-0.0764074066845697));
#1593=CARTESIAN_POINT('',(12.4371026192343,-0.26849227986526,-0.0634583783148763));
#1594=CARTESIAN_POINT('',(12.4369628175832,-0.274893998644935,-0.0369737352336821));
#1595=CARTESIAN_POINT('',(12.4369193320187,-0.276837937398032,-0.023440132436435));
#1596=CARTESIAN_POINT('',(12.4369016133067,-0.277629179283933,-0.00651308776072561));
#1597=CARTESIAN_POINT('',(12.4368998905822,-0.277705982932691,-0.00315564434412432));
#1598=CARTESIAN_POINT('',(12.4369000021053,-0.277701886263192,0.000199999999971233));
#1599=B_SPLINE_CURVE_WITH_KNOTS('',3,(#1559,#1560,#1561,#1562,#1563,#1564,#1565,#1566,#1567,
#1568,#1569,#1570,#1571,#1572,#1573,#1574,#1575,#1576,#1577,#1578,#1579,#1580,#1581,#1582,#1583,
#1584,#1585,#1586,#1587,#1588,#1589,#1590,#1591,#1592,#1593,#1594,#1595,#1596,#1597,#1598),
.UNSPECIFIED.,.F.,.F.,(4,2,2,2,2,2,2,2,2,2,2,2,2,2,2,2,2,2,2,4),(0.,0.0389918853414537,
0.0777990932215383,0.116570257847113,0.155372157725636,0.194510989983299,0.23365942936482,
0.277679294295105,0.321721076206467,0.371027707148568,0.420357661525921,0.473331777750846,
0.526317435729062,0.578837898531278,0.631324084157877,0.678731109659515,0.726104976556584,
0.766973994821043,0.80771209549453,0.817782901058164),.UNSPECIFIED.);
#1600=EDGE_CURVE('E513',#902,#762,#1599,.T.);
#1601=ORIENTED_EDGE('',*,*,#1600,.F.);
#1602=ORIENTED_EDGE('',*,*,#905,.T.);
#1603=CARTESIAN_POINT('',(8.59785144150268,8.99058121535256,0.000199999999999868));
#1604=CARTESIAN_POINT('',(8.59782639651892,8.99060427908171,-0.0128250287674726));
#1605=CARTESIAN_POINT('',(8.59869974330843,8.98976997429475,-0.0258344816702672));
#1606=CARTESIAN_POINT('',(8.60211254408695,8.98650485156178,-0.0513664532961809));
#1607=CARTESIAN_POINT('',(8.60464408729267,8.98408161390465,-0.0638909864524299));
#1608=CARTESIAN_POINT('',(8.61124165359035,8.97775788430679,-0.0881169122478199));
#1609=CARTESIAN_POINT('',(8.61530624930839,8.97385876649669,-0.0998190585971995));
#1610=CARTESIAN_POINT('',(8.62477168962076,8.96476193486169,-0.122130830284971));
#1611=CARTESIAN_POINT('',(8.63017359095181,8.95956319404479,-0.132739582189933));
#1612=CARTESIAN_POINT('',(8.64214397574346,8.94801748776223,-0.152734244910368));
#1613=CARTESIAN_POINT('',(8.64872218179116,8.94166094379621,-0.162108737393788));
#1614=CARTESIAN_POINT('',(8.66278693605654,8.92803552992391,-0.179393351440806));
#1615=CARTESIAN_POINT('',(8.67027370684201,8.92076643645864,-0.187303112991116));
#1616=CARTESIAN_POINT('',(8.68692267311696,8.90455643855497,-0.202469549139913));
#1617=CARTESIAN_POINT('',(8.69617742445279,8.89552005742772,-0.209522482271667));
#1618=CARTESIAN_POINT('',(8.71530281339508,8.87678299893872,-0.221623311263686));
#1619=CARTESIAN_POINT('',(8.72517375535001,8.86708199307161,-0.226670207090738));
#1620=CARTESIAN_POINT('',(8.74649801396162,8.84605122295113,-0.235217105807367));
#1621=CARTESIAN_POINT('',(8.75799943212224,8.83466538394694,-0.23846006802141));
#1622=CARTESIAN_POINT('',(8.78117617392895,8.81162938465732,-0.24239192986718));
#1623=CARTESIAN_POINT('',(8.79285157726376,8.79997910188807,-0.243079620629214));
#1624=CARTESIAN_POINT('',(8.81695324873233,8.77583312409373,-0.241853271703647));
#1625=CARTESIAN_POINT('',(8.82937127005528,8.76333855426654,-0.239743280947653));
#1626=CARTESIAN_POINT('',(8.85373210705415,8.73872575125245,-0.232575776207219));
#1627=CARTESIAN_POINT('',(8.86567481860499,8.72660760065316,-0.22751762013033));
#1628=CARTESIAN_POINT('',(8.88860658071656,8.70324873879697,-0.214535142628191));
#1629=CARTESIAN_POINT('',(8.89960308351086,8.69200125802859,-0.206636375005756));
#1630=CARTESIAN_POINT('',(8.92034233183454,8.67071585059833,-0.18804265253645));
#1631=CARTESIAN_POINT('',(8.93008589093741,8.66067713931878,-0.1773495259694));
#1632=CARTESIAN_POINT('',(8.94699486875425,8.64320638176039,-0.154525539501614));
#1633=CARTESIAN_POINT('',(8.95431853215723,8.63561609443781,-0.142633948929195));
#1634=CARTESIAN_POINT('',(8.96719531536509,8.62224418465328,-0.117004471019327));
#1635=CARTESIAN_POINT('',(8.97274966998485,8.61646130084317,-0.10326788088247));
#1636=CARTESIAN_POINT('',(8.98112271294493,8.60773293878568,-0.0764074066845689));
#1637=CARTESIAN_POINT('',(8.98421231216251,8.6045068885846,-0.0634583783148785));
#1638=CARTESIAN_POINT('',(8.98864015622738,8.59988133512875,-0.0369737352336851));
#1639=CARTESIAN_POINT('',(8.98998397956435,8.59847601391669,-0.0234401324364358));
#1640=CARTESIAN_POINT('',(8.99053094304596,8.59790399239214,-0.00651308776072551));
#1641=CARTESIAN_POINT('',(8.99058403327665,8.59784846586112,-0.00315564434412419));
#1642=CARTESIAN_POINT('',(8.9905812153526,8.59785144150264,0.000199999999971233));
#1643=B_SPLINE_CURVE_WITH_KNOTS('',3,(#1603,#1604,#1605,#1606,#1607,#1608,#1609,#1610,#1611,
#1612,#1613,#1614,#1615,#1616,#1617,#1618,#1619,#1620,#1621,#1622,#1623,#1624,#1625,#1626,#1627,
#1628,#1629,#1630,#1631,#1632,#1633,#1634,#1635,#1636,#1637,#1638,#1639,#1640,#1641,#1642),
.UNSPECIFIED.,.F.,.F.,(4,2,2,2,2,2,2,2,2,2,2,2,2,2,2,2,2,2,2,4),(0.,0.0389918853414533,
0.0777990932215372,0.116570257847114,0.155372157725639,0.194510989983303,0.233659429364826,
0.277679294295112,0.321721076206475,0.371027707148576,0.420357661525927,0.473331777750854,
0.52631743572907,0.578837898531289,0.63132408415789,0.678731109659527,0.726104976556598,
0.766973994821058,0.807712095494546,0.81778290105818),.UNSPECIFIED.);
#1644=EDGE_CURVE('E511',#1304,#904,#1643,.T.);
#1645=ORIENTED_EDGE('',*,*,#1644,.F.);
#1646=ORIENTED_EDGE('',*,*,#1305,.T.);
#1647=ORIENTED_EDGE('',*,*,#1124,.F.);
#1648=EDGE_LOOP('',(#1338,#1381,#1382,#1425,#1426,#1469,#1470,#1513,#1514,#1557,#1558,#1601,
#1602,#1645,#1646,#1647));
#1649=FACE_BOUND('',#1648,.T.);
#1650=CARTESIAN_POINT('',(0.,0.,-3.99999999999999));
#1651=DIRECTION('',(0.,0.,1.));
#1652=DIRECTION('',(1.,0.,0.));
#1653=AXIS2_PLACEMENT_3D('',#1650,#1651,#1652);
#1654=CIRCLE('',#1653,12.44);
#1655=CARTESIAN_POINT('',(12.44,0.,-3.99999999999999));
#1656=VERTEX_POINT('',#1655);
#1657=EDGE_CURVE('E286',#1656,#1656,#1654,.T.);
#1658=ORIENTED_EDGE('',*,*,#1657,.F.);
#1659=EDGE_LOOP('',(#1658));
#1660=FACE_BOUND('',#1659,.T.);
#1661=ADVANCED_FACE('F429',(#1649,#1660),#1337,.F.);
#1662=CARTESIAN_POINT('',(0.,14.,-3.99999999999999));
#1663=DIRECTION('',(0.,0.,1.));
#1664=DIRECTION('',(1.,0.,0.));
#1665=AXIS2_PLACEMENT_3D('',#1662,#1663,#1664);
#1666=PLANE('',#1665);
#1667=CARTESIAN_POINT('',(0.,0.,-3.99999999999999));
#1668=DIRECTION('',(0.,0.,1.));
#1669=DIRECTION('',(1.,0.,0.));
#1670=AXIS2_PLACEMENT_3D('',#1667,#1668,#1669);
#1671=CIRCLE('',#1670,13.7);
#1672=CARTESIAN_POINT('',(13.7,0.,-3.99999999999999));
#1673=VERTEX_POINT('',#1672);
#1674=EDGE_CURVE('E11',#1673,#1673,#1671,.F.);
#1675=ORIENTED_EDGE('',*,*,#1674,.T.);
#1676=EDGE_LOOP('',(#1675));
#1677=FACE_BOUND('',#1676,.T.);
#1678=ORIENTED_EDGE('',*,*,#1657,.T.);
#1679=EDGE_LOOP('',(#1678));
#1680=FACE_BOUND('',#1679,.T.);
#1681=ADVANCED_FACE('F426',(#1677,#1680),#1666,.F.);
#1682=CARTESIAN_POINT('',(0.,0.,50.3916163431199));
#1683=DIRECTION('',(0.,0.,1.));
#1684=DIRECTION('',(1.,0.,0.));
#1685=AXIS2_PLACEMENT_3D('',#1682,#1683,#1684);
#1686=CYLINDRICAL_SURFACE('',#1685,14.);
#1687=CARTESIAN_POINT('',(0.,0.,-3.69999999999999));
#1688=DIRECTION('',(0.,0.,1.));
#1689=DIRECTION('',(1.,0.,0.));
#1690=AXIS2_PLACEMENT_3D('',#1687,#1688,#1689);
#1691=CIRCLE('',#1690,14.);
#1692=CARTESIAN_POINT('',(14.,0.,-3.69999999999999));
#1693=VERTEX_POINT('',#1692);
#1694=EDGE_CURVE('E42',#1693,#1693,#1691,.T.);
#1695=ORIENTED_EDGE('',*,*,#1694,.T.);
#1696=EDGE_LOOP('',(#1695));
#1697=FACE_BOUND('',#1696,.T.);
#1698=CARTESIAN_POINT('',(0.,0.,3.49999999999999));
#1699=DIRECTION('',(0.,0.,-1.));
#1700=DIRECTION('',(-1.,0.,0.));
#1701=AXIS2_PLACEMENT_3D('',#1698,#1699,#1700);
#1702=CIRCLE('',#1701,14.);
#1703=CARTESIAN_POINT('',(-14.,0.,3.49999999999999));
#1704=VERTEX_POINT('',#1703);
#1705=EDGE_CURVE('E986',#1704,#1704,#1702,.T.);
#1706=ORIENTED_EDGE('',*,*,#1705,.T.);
#1707=EDGE_LOOP('',(#1706));
#1708=FACE_BOUND('',#1707,.T.);
#1709=ADVANCED_FACE('F422',(#1697,#1708),#1686,.T.);
#1710=CARTESIAN_POINT('',(0.,5.,3.99999999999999));
#1711=DIRECTION('',(0.,0.,-1.));
#1712=DIRECTION('',(-1.,0.,0.));
#1713=AXIS2_PLACEMENT_3D('',#1710,#1711,#1712);
#1714=PLANE('',#1713);
#1715=CARTESIAN_POINT('',(0.,0.,3.99999999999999));
#1716=DIRECTION('',(0.,0.,-1.));
#1717=DIRECTION('',(-1.,0.,0.));
#1718=AXIS2_PLACEMENT_3D('',#1715,#1716,#1717);
#1719=CIRCLE('',#1718,5.5);
#1720=CARTESIAN_POINT('',(-5.5,0.,3.99999999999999));
#1721=VERTEX_POINT('',#1720);
#1722=EDGE_CURVE('E993',#1721,#1721,#1719,.T.);
#1723=ORIENTED_EDGE('',*,*,#1722,.T.);
#1724=EDGE_LOOP('',(#1723));
#1725=FACE_BOUND('',#1724,.T.);
#1726=CARTESIAN_POINT('',(0.,0.,3.99999999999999));
#1727=DIRECTION('',(0.,0.,1.));
#1728=DIRECTION('',(1.,0.,0.));
#1729=AXIS2_PLACEMENT_3D('',#1726,#1727,#1728);
#1730=CIRCLE('',#1729,7.69999999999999);
#1731=CARTESIAN_POINT('',(7.69999999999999,0.,3.99999999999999));
#1732=VERTEX_POINT('',#1731);
#1733=EDGE_CURVE('E307',#1732,#1732,#1730,.T.);
#1734=ORIENTED_EDGE('',*,*,#1733,.T.);
#1735=EDGE_LOOP('',(#1734));
#1736=FACE_BOUND('',#1735,.T.);
#1737=ADVANCED_FACE('F418',(#1725,#1736),#1714,.F.);
#1738=CARTESIAN_POINT('',(0.,0.,70.8625909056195));
#1739=DIRECTION('',(0.,0.,1.));
#1740=DIRECTION('',(1.,0.,0.));
#1741=AXIS2_PLACEMENT_3D('',#1738,#1739,#1740);
#1742=CYLINDRICAL_SURFACE('',#1741,5.);
#1743=CARTESIAN_POINT('',(0.,0.,-3.5));
#1744=DIRECTION('',(0.,0.,1.));
#1745=DIRECTION('',(1.,0.,0.));
#1746=AXIS2_PLACEMENT_3D('',#1743,#1744,#1745);
#1747=CIRCLE('',#1746,5.);
#1748=CARTESIAN_POINT('',(5.,0.,-3.5));
#1749=VERTEX_POINT('',#1748);
#1750=EDGE_CURVE('E996',#1749,#1749,#1747,.F.);
#1751=ORIENTED_EDGE('',*,*,#1750,.T.);
#1752=EDGE_LOOP('',(#1751));
#1753=FACE_BOUND('',#1752,.T.);
#1754=CARTESIAN_POINT('',(0.,0.,3.49999999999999));
#1755=DIRECTION('',(0.,0.,-1.));
#1756=DIRECTION('',(-1.,0.,0.));
#1757=AXIS2_PLACEMENT_3D('',#1754,#1755,#1756);
#1758=CIRCLE('',#1757,5.);
#1759=CARTESIAN_POINT('',(-5.,0.,3.49999999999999));
#1760=VERTEX_POINT('',#1759);
#1761=EDGE_CURVE('E998',#1760,#1760,#1758,.F.);
#1762=ORIENTED_EDGE('',*,*,#1761,.T.);
#1763=EDGE_LOOP('',(#1762));
#1764=FACE_BOUND('',#1763,.T.);
#1765=ADVANCED_FACE('F414',(#1753,#1764),#1742,.F.);
#1766=CARTESIAN_POINT('',(0.,5.,-4.));
#1767=DIRECTION('',(0.,0.,1.));
#1768=DIRECTION('',(1.,0.,0.));
#1769=AXIS2_PLACEMENT_3D('',#1766,#1767,#1768);
#1770=PLANE('',#1769);
#1771=CARTESIAN_POINT('',(0.,0.,-4.));
#1772=DIRECTION('',(0.,0.,1.));
#1773=DIRECTION('',(1.,0.,0.));
#1774=AXIS2_PLACEMENT_3D('',#1771,#1772,#1773);
#1775=CIRCLE('',#1774,5.5);
#1776=CARTESIAN_POINT('',(5.5,0.,-4.));
#1777=VERTEX_POINT('',#1776);
#1778=EDGE_CURVE('E404',#1777,#1777,#1775,.T.);
#1779=ORIENTED_EDGE('',*,*,#1778,.T.);
#1780=EDGE_LOOP('',(#1779));
#1781=FACE_BOUND('',#1780,.T.);
#1782=CARTESIAN_POINT('',(0.,0.,-4.));
#1783=DIRECTION('',(0.,0.,1.));
#1784=DIRECTION('',(1.,0.,0.));
#1785=AXIS2_PLACEMENT_3D('',#1782,#1783,#1784);
#1786=CIRCLE('',#1785,7.7);
#1787=CARTESIAN_POINT('',(7.7,0.,-4.));
#1788=VERTEX_POINT('',#1787);
#1789=EDGE_CURVE('E291',#1788,#1788,#1786,.T.);
#1790=ORIENTED_EDGE('',*,*,#1789,.F.);
#1791=EDGE_LOOP('',(#1790));
#1792=FACE_BOUND('',#1791,.T.);
#1793=ADVANCED_FACE('F410',(#1781,#1792),#1770,.F.);
#1794=CARTESIAN_POINT('',(0.,0.,70.8625909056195));
#1795=DIRECTION('',(0.,0.,1.));
#1796=DIRECTION('',(1.,0.,0.));
#1797=AXIS2_PLACEMENT_3D('',#1794,#1795,#1796);
#1798=CYLINDRICAL_SURFACE('',#1797,7.7);
#1799=ORIENTED_EDGE('',*,*,#151,.F.);
#1800=CARTESIAN_POINT('',(-5.28679763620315,5.59819352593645,-2.32436447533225));
#1801=CARTESIAN_POINT('',(-5.3401813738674,5.54777863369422,-2.33292094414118));
#1802=CARTESIAN_POINT('',(-5.39282290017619,5.4966215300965,-2.33719917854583));
#1803=CARTESIAN_POINT('',(-5.49662153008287,5.39282290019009,-2.33719917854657));
#1804=CARTESIAN_POINT('',(-5.54777863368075,5.34018137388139,-2.33292094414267));
#1805=CARTESIAN_POINT('',(-5.59819352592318,5.2867976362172,-2.32436447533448));
#1806=B_SPLINE_CURVE_WITH_KNOTS('',3,(#1800,#1801,#1802,#1803,#1804,#1805),.UNSPECIFIED.,.F.,
.F.,(4,2,4),(0.,0.220586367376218,0.441172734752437),.UNSPECIFIED.);
#1807=CARTESIAN_POINT('',(-5.2880465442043,5.59701382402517,-2.32456447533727));
#1808=VERTEX_POINT('',#1807);
#1809=EDGE_CURVE('E637',#1808,#141,#1806,.T.);
#1810=ORIENTED_EDGE('',*,*,#1809,.F.);
#1811=EDGE_CURVE('E295',#1137,#1808,#148,.T.);
#1812=ORIENTED_EDGE('',*,*,#1811,.F.);
#1813=ORIENTED_EDGE('',*,*,#1138,.F.);
#1814=ORIENTED_EDGE('',*,*,#1003,.F.);
#1815=CARTESIAN_POINT('',(5.5981935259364,5.2867976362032,-2.32436447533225));
#1816=CARTESIAN_POINT('',(5.54777863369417,5.34018137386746,-2.33292094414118));
#1817=CARTESIAN_POINT('',(5.49662153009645,5.39282290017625,-2.33719917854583));
#1818=CARTESIAN_POINT('',(5.39282290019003,5.49662153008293,-2.33719917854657));
#1819=CARTESIAN_POINT('',(5.34018137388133,5.54777863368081,-2.33292094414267));
#1820=CARTESIAN_POINT('',(5.28679763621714,5.59819352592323,-2.32436447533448));
#1821=B_SPLINE_CURVE_WITH_KNOTS('',3,(#1815,#1816,#1817,#1818,#1819,#1820),.UNSPECIFIED.,.F.,
.F.,(4,2,4),(0.,0.220586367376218,0.441172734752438),.UNSPECIFIED.);
#1822=EDGE_CURVE('E518',#860,#998,#1821,.T.);
#1823=ORIENTED_EDGE('',*,*,#1822,.F.);
#1824=ORIENTED_EDGE('',*,*,#861,.F.);
#1825=CARTESIAN_POINT('',(7.69685106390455,-0.220190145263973,-2.32436447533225));
#1826=CARTESIAN_POINT('',(7.69895035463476,-0.146793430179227,-2.33292094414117));
#1827=CARTESIAN_POINT('',(7.69999999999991,-0.0733967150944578,-2.33719917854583));
#1828=CARTESIAN_POINT('',(7.70000000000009,0.073396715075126,-2.33719917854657));
#1829=CARTESIAN_POINT('',(7.69895035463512,0.146793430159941,-2.33292094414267));
#1830=CARTESIAN_POINT('',(7.6968510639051,0.220190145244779,-2.32436447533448));
#1831=B_SPLINE_CURVE_WITH_KNOTS('',3,(#1825,#1826,#1827,#1828,#1829,#1830),.UNSPECIFIED.,.F.,
.F.,(4,2,4),(0.,0.220586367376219,0.441172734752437),.UNSPECIFIED.);
#1832=EDGE_CURVE('E575',#718,#856,#1831,.T.);
#1833=ORIENTED_EDGE('',*,*,#1832,.F.);
#1834=ORIENTED_EDGE('',*,*,#719,.F.);
#1835=CARTESIAN_POINT('',(5.28679763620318,-5.59819352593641,-2.32436447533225));
#1836=CARTESIAN_POINT('',(5.34018137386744,-5.54777863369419,-2.33292094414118));
#1837=CARTESIAN_POINT('',(5.39282290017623,-5.49662153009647,-2.33719917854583));
#1838=CARTESIAN_POINT('',(5.49662153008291,-5.39282290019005,-2.33719917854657));
#1839=CARTESIAN_POINT('',(5.54777863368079,-5.34018137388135,-2.33292094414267));
#1840=CARTESIAN_POINT('',(5.59819352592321,-5.28679763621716,-2.32436447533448));
#1841=B_SPLINE_CURVE_WITH_KNOTS('',3,(#1835,#1836,#1837,#1838,#1839,#1840),.UNSPECIFIED.,.F.,
.F.,(4,2,4),(0.,0.220586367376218,0.441172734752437),.UNSPECIFIED.);
#1842=EDGE_CURVE('E892',#576,#714,#1841,.T.);
#1843=ORIENTED_EDGE('',*,*,#1842,.F.);
#1844=ORIENTED_EDGE('',*,*,#577,.F.);
#1845=CARTESIAN_POINT('',(-0.220190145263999,-7.69685106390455,-2.32436447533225));
#1846=CARTESIAN_POINT('',(-0.146793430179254,-7.69895035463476,-2.33292094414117));
#1847=CARTESIAN_POINT('',(-0.0733967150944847,-7.69999999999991,-2.33719917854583));
#1848=CARTESIAN_POINT('',(0.0733967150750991,-7.70000000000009,-2.33719917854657));
#1849=CARTESIAN_POINT('',(0.146793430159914,-7.69895035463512,-2.33292094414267));
#1850=CARTESIAN_POINT('',(0.220190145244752,-7.6968510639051,-2.32436447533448));
#1851=B_SPLINE_CURVE_WITH_KNOTS('',3,(#1845,#1846,#1847,#1848,#1849,#1850),.UNSPECIFIED.,.F.,
.F.,(4,2,4),(0.,0.220586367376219,0.441172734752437),.UNSPECIFIED.);
#1852=EDGE_CURVE('E830',#434,#572,#1851,.T.);
#1853=ORIENTED_EDGE('',*,*,#1852,.F.);
#1854=ORIENTED_EDGE('',*,*,#435,.F.);
#1855=CARTESIAN_POINT('',(-5.59819352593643,-5.28679763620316,-2.32436447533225));
#1856=CARTESIAN_POINT('',(-5.5477786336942,-5.34018137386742,-2.33292094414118));
#1857=CARTESIAN_POINT('',(-5.49662153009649,-5.39282290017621,-2.33719917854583));
#1858=CARTESIAN_POINT('',(-5.39282290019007,-5.49662153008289,-2.33719917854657));
#1859=CARTESIAN_POINT('',(-5.34018137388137,-5.54777863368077,-2.33292094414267));
#1860=CARTESIAN_POINT('',(-5.28679763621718,-5.59819352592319,-2.32436447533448));
#1861=B_SPLINE_CURVE_WITH_KNOTS('',3,(#1855,#1856,#1857,#1858,#1859,#1860),.UNSPECIFIED.,.F.,
.F.,(4,2,4),(0.,0.220586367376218,0.441172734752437),.UNSPECIFIED.);
#1862=EDGE_CURVE('E765',#292,#430,#1861,.T.);
#1863=ORIENTED_EDGE('',*,*,#1862,.F.);
#1864=ORIENTED_EDGE('',*,*,#293,.F.);
#1865=CARTESIAN_POINT('',(-7.69685106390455,0.220190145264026,-2.32436447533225));
#1866=CARTESIAN_POINT('',(-7.69895035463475,0.14679343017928,-2.33292094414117));
#1867=CARTESIAN_POINT('',(-7.69999999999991,0.0733967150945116,-2.33719917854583));
#1868=CARTESIAN_POINT('',(-7.70000000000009,-0.0733967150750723,-2.33719917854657));
#1869=CARTESIAN_POINT('',(-7.69895035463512,-0.146793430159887,-2.33292094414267));
#1870=CARTESIAN_POINT('',(-7.6968510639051,-0.220190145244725,-2.32436447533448));
#1871=B_SPLINE_CURVE_WITH_KNOTS('',3,(#1865,#1866,#1867,#1868,#1869,#1870),.UNSPECIFIED.,.F.,
.F.,(4,2,4),(0.,0.220586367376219,0.441172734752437),.UNSPECIFIED.);
#1872=EDGE_CURVE('E709',#150,#288,#1871,.T.);
#1873=ORIENTED_EDGE('',*,*,#1872,.F.);
#1874=EDGE_LOOP('',(#1799,#1810,#1812,#1813,#1814,#1823,#1824,#1833,#1834,#1843,#1844,#1853,
#1854,#1863,#1864,#1873));
#1875=FACE_BOUND('',#1874,.T.);
#1876=ORIENTED_EDGE('',*,*,#1789,.T.);
#1877=EDGE_LOOP('',(#1876));
#1878=FACE_BOUND('',#1877,.T.);
#1879=ADVANCED_FACE('F406',(#1875,#1878),#1798,.T.);
#1880=ORIENTED_EDGE('',*,*,#1811,.T.);
#1881=CARTESIAN_POINT('',(-5.28822660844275,5.59719907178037,2.32476447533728));
#1882=CARTESIAN_POINT('',(-5.24264670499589,5.55030713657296,2.27415407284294));
#1883=CARTESIAN_POINT('',(-5.19856819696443,5.50495120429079,2.2207750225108));
#1884=CARTESIAN_POINT('',(-5.1137081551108,5.41761719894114,2.10888540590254));
#1885=CARTESIAN_POINT('',(-5.07292646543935,5.37563896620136,2.05037508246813));
#1886=CARTESIAN_POINT('',(-4.99497636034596,5.29538898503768,1.92866518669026));
#1887=CARTESIAN_POINT('',(-4.95780550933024,5.25711473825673,1.86546882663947));
#1888=CARTESIAN_POINT('',(-4.88731477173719,5.18452081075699,1.73483020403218));
#1889=CARTESIAN_POINT('',(-4.85399483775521,5.15020108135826,1.66738799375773));
#1890=CARTESIAN_POINT('',(-4.76014612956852,5.05352345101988,1.4593120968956));
#1891=CARTESIAN_POINT('',(-4.70569744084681,4.99741517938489,1.31288063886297));
#1892=CARTESIAN_POINT('',(-4.61475012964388,4.90367911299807,1.00908566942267));
#1893=CARTESIAN_POINT('',(-4.57824680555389,4.86604647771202,0.851725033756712));
#1894=CARTESIAN_POINT('',(-4.52415007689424,4.8102711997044,0.530443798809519));
#1895=CARTESIAN_POINT('',(-4.50655338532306,4.79212516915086,0.36652434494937));
#1896=CARTESIAN_POINT('',(-4.49076552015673,4.77584458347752,0.0366933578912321));
#1897=CARTESIAN_POINT('',(-4.49258323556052,4.77771919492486,-0.129219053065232));
#1898=CARTESIAN_POINT('',(-4.51558639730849,4.80143983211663,-0.458305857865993));
#1899=CARTESIAN_POINT('',(-4.53678044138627,4.82329472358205,-0.621479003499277));
#1900=CARTESIAN_POINT('',(-4.59794384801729,4.88635256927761,-0.940223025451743));
#1901=CARTESIAN_POINT('',(-4.63788552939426,4.92752699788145,-1.09580473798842));
#1902=CARTESIAN_POINT('',(-4.71317439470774,5.00511799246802,-1.32701813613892));
#1903=CARTESIAN_POINT('',(-4.74237952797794,5.03521272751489,-1.40688828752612));
#1904=CARTESIAN_POINT('',(-4.80577712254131,5.10053105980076,-1.56244542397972));
#1905=CARTESIAN_POINT('',(-4.8399688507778,5.13575390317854,-1.63813302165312));
#1906=CARTESIAN_POINT('',(-4.92502886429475,5.22336373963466,-1.80867878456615));
#1907=CARTESIAN_POINT('',(-4.97769294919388,5.27759567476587,-1.90170534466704));
#1908=CARTESIAN_POINT('',(-5.09051839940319,5.39374990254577,-2.07781658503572));
#1909=CARTESIAN_POINT('',(-5.15067551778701,5.45566783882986,-2.1609068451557));
#1910=CARTESIAN_POINT('',(-5.23834308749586,5.54587699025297,-2.26802026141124));
#1911=CARTESIAN_POINT('',(-5.26305959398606,5.57130760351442,-2.29681885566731));
#1912=CARTESIAN_POINT('',(-5.28822660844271,5.59719907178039,-2.32476447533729));
#1913=B_SPLINE_CURVE_WITH_KNOTS('',3,(#1881,#1882,#1883,#1884,#1885,#1886,#1887,#1888,#1889,
#1890,#1891,#1892,#1893,#1894,#1895,#1896,#1897,#1898,#1899,#1900,#1901,#1902,#1903,#1904,#1905,
#1906,#1907,#1908,#1909,#1910,#1911,#1912),.UNSPECIFIED.,.F.,.F.,(4,2,2,2,2,2,2,2,2,2,2,2,2,2,2,
4),(0.,0.247992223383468,0.495972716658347,0.743784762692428,0.991593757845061,1.48701674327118,
1.98230986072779,2.47751685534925,2.97295059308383,3.46860427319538,3.96352840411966,
4.23382992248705,4.50409174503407,4.86279314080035,5.22129214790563,5.35828916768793),.UNSPECIFIED.);
#1914=CARTESIAN_POINT('',(-5.28804654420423,5.59701382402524,2.32456447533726));
#1915=VERTEX_POINT('',#1914);
#1916=EDGE_CURVE('E250',#1915,#1808,#1913,.T.);
#1917=ORIENTED_EDGE('',*,*,#1916,.F.);
#1918=EDGE_CURVE('E302',#1174,#1915,#100,.T.);
#1919=ORIENTED_EDGE('',*,*,#1918,.F.);
#1920=ORIENTED_EDGE('',*,*,#1175,.F.);
#1921=EDGE_LOOP('',(#1880,#1917,#1919,#1920));
#1922=FACE_BOUND('',#1921,.T.);
#1923=ADVANCED_FACE('F338',(#1922),#95,.F.);
#1924=CARTESIAN_POINT('',(0.,0.,70.8625909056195));
#1925=DIRECTION('',(0.,0.,1.));
#1926=DIRECTION('',(1.,0.,0.));
#1927=AXIS2_PLACEMENT_3D('',#1924,#1925,#1926);
#1928=CYLINDRICAL_SURFACE('',#1927,7.7);
#1929=ORIENTED_EDGE('',*,*,#1918,.T.);
#1930=CARTESIAN_POINT('',(-5.5981935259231,5.28679763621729,2.32436447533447));
#1931=CARTESIAN_POINT('',(-5.5477786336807,5.34018137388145,2.33292094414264));
#1932=CARTESIAN_POINT('',(-5.49662153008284,5.39282290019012,2.33719917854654));
#1933=CARTESIAN_POINT('',(-5.39282290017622,5.49662153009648,2.3371991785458));
#1934=CARTESIAN_POINT('',(-5.34018137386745,5.54777863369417,2.33292094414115));
#1935=CARTESIAN_POINT('',(-5.28679763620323,5.59819352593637,2.32436447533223));
#1936=B_SPLINE_CURVE_WITH_KNOTS('',3,(#1930,#1931,#1932,#1933,#1934,#1935),.UNSPECIFIED.,.F.,
.F.,(4,2,4),(0.,0.220586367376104,0.441172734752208),.UNSPECIFIED.);
#1937=EDGE_CURVE('E642',#102,#1915,#1936,.T.);
#1938=ORIENTED_EDGE('',*,*,#1937,.F.);
#1939=ORIENTED_EDGE('',*,*,#105,.T.);
#1940=CARTESIAN_POINT('',(-7.6968510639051,-0.220190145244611,2.32436447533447));
#1941=CARTESIAN_POINT('',(-7.69895035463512,-0.146793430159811,2.33292094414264));
#1942=CARTESIAN_POINT('',(-7.70000000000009,-0.0733967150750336,2.33719917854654));
#1943=CARTESIAN_POINT('',(-7.69999999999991,0.0733967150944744,2.3371991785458));
#1944=CARTESIAN_POINT('',(-7.69895035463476,0.146793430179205,2.33292094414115));
#1945=CARTESIAN_POINT('',(-7.69685106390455,0.220190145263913,2.32436447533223));
#1946=B_SPLINE_CURVE_WITH_KNOTS('',3,(#1940,#1941,#1942,#1943,#1944,#1945),.UNSPECIFIED.,.F.,
.F.,(4,2,4),(0.,0.220586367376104,0.441172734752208),.UNSPECIFIED.);
#1947=EDGE_CURVE('E664',#249,#104,#1946,.T.);
#1948=ORIENTED_EDGE('',*,*,#1947,.F.);
#1949=ORIENTED_EDGE('',*,*,#252,.T.);
#1950=CARTESIAN_POINT('',(-5.28679763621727,-5.59819352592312,2.32436447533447));
#1951=CARTESIAN_POINT('',(-5.34018137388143,-5.54777863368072,2.33292094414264));
#1952=CARTESIAN_POINT('',(-5.3928229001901,-5.49662153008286,2.33719917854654));
#1953=CARTESIAN_POINT('',(-5.49662153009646,-5.39282290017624,2.3371991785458));
#1954=CARTESIAN_POINT('',(-5.54777863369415,-5.34018137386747,2.33292094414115));
#1955=CARTESIAN_POINT('',(-5.59819352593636,-5.28679763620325,2.32436447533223));
#1956=B_SPLINE_CURVE_WITH_KNOTS('',3,(#1950,#1951,#1952,#1953,#1954,#1955),.UNSPECIFIED.,.F.,
.F.,(4,2,4),(0.,0.220586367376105,0.441172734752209),.UNSPECIFIED.);
#1957=EDGE_CURVE('E775',#391,#251,#1956,.T.);
#1958=ORIENTED_EDGE('',*,*,#1957,.F.);
#1959=ORIENTED_EDGE('',*,*,#394,.T.);
#1960=CARTESIAN_POINT('',(0.220190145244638,-7.6968510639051,2.32436447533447));
#1961=CARTESIAN_POINT('',(0.146793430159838,-7.69895035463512,2.33292094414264));
#1962=CARTESIAN_POINT('',(0.0733967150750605,-7.70000000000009,2.33719917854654));
#1963=CARTESIAN_POINT('',(-0.0733967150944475,-7.69999999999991,2.3371991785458));
#1964=CARTESIAN_POINT('',(-0.146793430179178,-7.69895035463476,2.33292094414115));
#1965=CARTESIAN_POINT('',(-0.220190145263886,-7.69685106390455,2.32436447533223));
#1966=B_SPLINE_CURVE_WITH_KNOTS('',3,(#1960,#1961,#1962,#1963,#1964,#1965),.UNSPECIFIED.,.F.,
.F.,(4,2,4),(0.,0.220586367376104,0.441172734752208),.UNSPECIFIED.);
#1967=EDGE_CURVE('E840',#533,#393,#1966,.T.);
#1968=ORIENTED_EDGE('',*,*,#1967,.F.);
#1969=ORIENTED_EDGE('',*,*,#536,.T.);
#1970=CARTESIAN_POINT('',(5.59819352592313,-5.28679763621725,2.32436447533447));
#1971=CARTESIAN_POINT('',(5.54777863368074,-5.34018137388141,2.33292094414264));
#1972=CARTESIAN_POINT('',(5.49662153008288,-5.39282290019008,2.33719917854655));
#1973=CARTESIAN_POINT('',(5.39282290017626,-5.49662153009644,2.3371991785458));
#1974=CARTESIAN_POINT('',(5.34018137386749,-5.54777863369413,2.33292094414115));
#1975=CARTESIAN_POINT('',(5.28679763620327,-5.59819352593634,2.32436447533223));
#1976=B_SPLINE_CURVE_WITH_KNOTS('',3,(#1970,#1971,#1972,#1973,#1974,#1975),.UNSPECIFIED.,.F.,
.F.,(4,2,4),(0.,0.220586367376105,0.441172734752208),.UNSPECIFIED.);
#1977=EDGE_CURVE('E604',#675,#535,#1976,.T.);
#1978=ORIENTED_EDGE('',*,*,#1977,.F.);
#1979=ORIENTED_EDGE('',*,*,#678,.T.);
#1980=CARTESIAN_POINT('',(7.6968510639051,0.220190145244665,2.32436447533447));
#1981=CARTESIAN_POINT('',(7.69895035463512,0.146793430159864,2.33292094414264));
#1982=CARTESIAN_POINT('',(7.70000000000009,0.0733967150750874,2.33719917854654));
#1983=CARTESIAN_POINT('',(7.69999999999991,-0.0733967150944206,2.3371991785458));
#1984=CARTESIAN_POINT('',(7.69895035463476,-0.146793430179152,2.33292094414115));
#1985=CARTESIAN_POINT('',(7.69685106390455,-0.220190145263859,2.32436447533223));
#1986=B_SPLINE_CURVE_WITH_KNOTS('',3,(#1980,#1981,#1982,#1983,#1984,#1985),.UNSPECIFIED.,.F.,
.F.,(4,2,4),(0.,0.220586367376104,0.441172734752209),.UNSPECIFIED.);
#1987=EDGE_CURVE('E550',#817,#677,#1986,.T.);
#1988=ORIENTED_EDGE('',*,*,#1987,.F.);
#1989=ORIENTED_EDGE('',*,*,#820,.T.);
#1990=CARTESIAN_POINT('',(5.28679763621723,5.59819352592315,2.32436447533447));
#1991=CARTESIAN_POINT('',(5.34018137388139,5.54777863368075,2.33292094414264));
#1992=CARTESIAN_POINT('',(5.39282290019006,5.4966215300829,2.33719917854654));
#1993=CARTESIAN_POINT('',(5.49662153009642,5.39282290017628,2.3371991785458));
#1994=CARTESIAN_POINT('',(5.54777863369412,5.34018137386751,2.33292094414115));
#1995=CARTESIAN_POINT('',(5.59819352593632,5.28679763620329,2.32436447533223));
#1996=B_SPLINE_CURVE_WITH_KNOTS('',3,(#1990,#1991,#1992,#1993,#1994,#1995),.UNSPECIFIED.,.F.,
.F.,(4,2,4),(0.,0.220586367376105,0.441172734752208),.UNSPECIFIED.);
#1997=EDGE_CURVE('E310',#959,#819,#1996,.T.);
#1998=ORIENTED_EDGE('',*,*,#1997,.F.);
#1999=ORIENTED_EDGE('',*,*,#962,.T.);
#2000=ORIENTED_EDGE('',*,*,#1184,.F.);
#2001=EDGE_LOOP('',(#1929,#1938,#1939,#1948,#1949,#1958,#1959,#1968,#1969,#1978,#1979,#1988,
#1989,#1998,#1999,#2000));
#2002=FACE_BOUND('',#2001,.T.);
#2003=ORIENTED_EDGE('',*,*,#1733,.F.);
#2004=EDGE_LOOP('',(#2003));
#2005=FACE_BOUND('',#2004,.T.);
#2006=ADVANCED_FACE('F333',(#2002,#2005),#1928,.T.);
#2007=CARTESIAN_POINT('',(0.,0.,-3.5));
#2008=DIRECTION('',(0.,0.,1.));
#2009=DIRECTION('',(1.,0.,0.));
#2010=AXIS2_PLACEMENT_3D('',#2007,#2008,#2009);
#2011=TOROIDAL_SURFACE('',#2010,5.5,0.5);
#2012=ORIENTED_EDGE('',*,*,#1750,.F.);
#2013=EDGE_LOOP('',(#2012));
#2014=FACE_BOUND('',#2013,.T.);
#2015=ORIENTED_EDGE('',*,*,#1778,.F.);
#2016=EDGE_LOOP('',(#2015));
#2017=FACE_BOUND('',#2016,.T.);
#2018=ADVANCED_FACE('F337',(#2014,#2017),#2011,.T.);
#2019=CARTESIAN_POINT('',(0.,0.,3.49999999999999));
#2020=DIRECTION('',(0.,0.,-1.));
#2021=DIRECTION('',(-1.,0.,0.));
#2022=AXIS2_PLACEMENT_3D('',#2019,#2020,#2021);
#2023=TOROIDAL_SURFACE('',#2022,5.5,0.5);
#2024=ORIENTED_EDGE('',*,*,#1722,.F.);
#2025=EDGE_LOOP('',(#2024));
#2026=FACE_BOUND('',#2025,.T.);
#2027=ORIENTED_EDGE('',*,*,#1761,.F.);
#2028=EDGE_LOOP('',(#2027));
#2029=FACE_BOUND('',#2028,.T.);
#2030=ADVANCED_FACE('F980',(#2026,#2029),#2023,.T.);
#2031=CARTESIAN_POINT('',(0.,0.,3.49999999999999));
#2032=DIRECTION('',(0.,0.,-1.));
#2033=DIRECTION('',(-1.,0.,0.));
#2034=AXIS2_PLACEMENT_3D('',#2031,#2032,#2033);
#2035=TOROIDAL_SURFACE('',#2034,13.5,0.5);
#2036=ORIENTED_EDGE('',*,*,#1705,.F.);
#2037=EDGE_LOOP('',(#2036));
#2038=FACE_BOUND('',#2037,.T.);
#2039=ORIENTED_EDGE('',*,*,#1201,.F.);
#2040=EDGE_LOOP('',(#2039));
#2041=FACE_BOUND('',#2040,.T.);
#2042=ADVANCED_FACE('F975',(#2038,#2041),#2035,.T.);
#2043=CARTESIAN_POINT('',(0.,0.,-3.69999999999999));
#2044=DIRECTION('',(0.,0.,1.));
#2045=DIRECTION('',(1.,0.,0.));
#2046=AXIS2_PLACEMENT_3D('',#2043,#2044,#2045);
#2047=TOROIDAL_SURFACE('',#2046,13.7,0.3);
#2048=ORIENTED_EDGE('',*,*,#1674,.F.);
#2049=EDGE_LOOP('',(#2048));
#2050=FACE_BOUND('',#2049,.T.);
#2051=ORIENTED_EDGE('',*,*,#1694,.F.);
#2052=EDGE_LOOP('',(#2051));
#2053=FACE_BOUND('',#2052,.T.);
#2054=ADVANCED_FACE('F36',(#2050,#2053),#2047,.T.);
#2055=CARTESIAN_POINT('',(6.71751442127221,6.71751442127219,0.));
#2056=DIRECTION('',(0.707106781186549,0.707106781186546,0.));
#2057=DIRECTION('',(0.,0.,-1.));
#2058=AXIS2_PLACEMENT_3D('',#2055,#2056,#2057);
#2059=SPHERICAL_SURFACE('',#2058,2.95);
#2060=ORIENTED_EDGE('',*,*,#953,.T.);
#2061=ORIENTED_EDGE('',*,*,#1245,.T.);
#2062=ORIENTED_EDGE('',*,*,#1326,.T.);
#2063=ORIENTED_EDGE('',*,*,#1644,.T.);
#2064=EDGE_LOOP('',(#2060,#2061,#2062,#2063));
#2065=FACE_BOUND('',#2064,.T.);
#2066=ORIENTED_EDGE('',*,*,#896,.T.);
#2067=ORIENTED_EDGE('',*,*,#1822,.T.);
#2068=ORIENTED_EDGE('',*,*,#999,.T.);
#2069=ORIENTED_EDGE('',*,*,#1997,.T.);
#2070=EDGE_LOOP('',(#2066,#2067,#2068,#2069));
#2071=FACE_BOUND('',#2070,.T.);
#2072=ADVANCED_FACE('F324',(#2065,#2071),#2059,.T.);
#2073=CARTESIAN_POINT('',(9.5,0.,0.));
#2074=DIRECTION('',(1.,0.,0.));
#2075=DIRECTION('',(0.,0.,-1.));
#2076=AXIS2_PLACEMENT_3D('',#2073,#2074,#2075);
#2077=SPHERICAL_SURFACE('',#2076,2.95);
#2078=ORIENTED_EDGE('',*,*,#811,.T.);
#2079=ORIENTED_EDGE('',*,*,#1255,.T.);
#2080=ORIENTED_EDGE('',*,*,#928,.T.);
#2081=ORIENTED_EDGE('',*,*,#1600,.T.);
#2082=EDGE_LOOP('',(#2078,#2079,#2080,#2081));
#2083=FACE_BOUND('',#2082,.T.);
#2084=ORIENTED_EDGE('',*,*,#754,.T.);
#2085=ORIENTED_EDGE('',*,*,#1832,.T.);
#2086=ORIENTED_EDGE('',*,*,#857,.T.);
#2087=ORIENTED_EDGE('',*,*,#1987,.T.);
#2088=EDGE_LOOP('',(#2084,#2085,#2086,#2087));
#2089=FACE_BOUND('',#2088,.T.);
#2090=ADVANCED_FACE('F565',(#2083,#2089),#2077,.T.);
#2091=CARTESIAN_POINT('',(6.71751442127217,-6.71751442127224,0.));
#2092=DIRECTION('',(0.707106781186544,-0.707106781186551,0.));
#2093=DIRECTION('',(0.,0.,-1.));
#2094=AXIS2_PLACEMENT_3D('',#2091,#2092,#2093);
#2095=SPHERICAL_SURFACE('',#2094,2.95);
#2096=ORIENTED_EDGE('',*,*,#669,.T.);
#2097=ORIENTED_EDGE('',*,*,#1265,.T.);
#2098=ORIENTED_EDGE('',*,*,#786,.T.);
#2099=ORIENTED_EDGE('',*,*,#1556,.T.);
#2100=EDGE_LOOP('',(#2096,#2097,#2098,#2099));
#2101=FACE_BOUND('',#2100,.T.);
#2102=ORIENTED_EDGE('',*,*,#612,.T.);
#2103=ORIENTED_EDGE('',*,*,#1842,.T.);
#2104=ORIENTED_EDGE('',*,*,#715,.T.);
#2105=ORIENTED_EDGE('',*,*,#1977,.T.);
#2106=EDGE_LOOP('',(#2102,#2103,#2104,#2105));
#2107=FACE_BOUND('',#2106,.T.);
#2108=ADVANCED_FACE('F791',(#2101,#2107),#2095,.T.);
#2109=CARTESIAN_POINT('',(0.,-9.5,0.));
#2110=DIRECTION('',(0.,-1.,0.));
#2111=DIRECTION('',(0.,0.,-1.));
#2112=AXIS2_PLACEMENT_3D('',#2109,#2110,#2111);
#2113=SPHERICAL_SURFACE('',#2112,2.95);
#2114=ORIENTED_EDGE('',*,*,#527,.T.);
#2115=ORIENTED_EDGE('',*,*,#1275,.T.);
#2116=ORIENTED_EDGE('',*,*,#644,.T.);
#2117=ORIENTED_EDGE('',*,*,#1512,.T.);
#2118=EDGE_LOOP('',(#2114,#2115,#2116,#2117));
#2119=FACE_BOUND('',#2118,.T.);
#2120=ORIENTED_EDGE('',*,*,#470,.T.);
#2121=ORIENTED_EDGE('',*,*,#1852,.T.);
#2122=ORIENTED_EDGE('',*,*,#573,.T.);
#2123=ORIENTED_EDGE('',*,*,#1967,.T.);
#2124=EDGE_LOOP('',(#2120,#2121,#2122,#2123));
#2125=FACE_BOUND('',#2124,.T.);
#2126=ADVANCED_FACE('F731',(#2119,#2125),#2113,.T.);
#2127=CARTESIAN_POINT('',(-6.71751442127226,-6.71751442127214,0.));
#2128=DIRECTION('',(-0.707106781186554,-0.707106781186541,0.));
#2129=DIRECTION('',(0.,0.,-1.));
#2130=AXIS2_PLACEMENT_3D('',#2127,#2128,#2129);
#2131=SPHERICAL_SURFACE('',#2130,2.95);
#2132=ORIENTED_EDGE('',*,*,#385,.T.);
#2133=ORIENTED_EDGE('',*,*,#1285,.T.);
#2134=ORIENTED_EDGE('',*,*,#502,.T.);
#2135=ORIENTED_EDGE('',*,*,#1468,.T.);
#2136=EDGE_LOOP('',(#2132,#2133,#2134,#2135));
#2137=FACE_BOUND('',#2136,.T.);
#2138=ORIENTED_EDGE('',*,*,#328,.T.);
#2139=ORIENTED_EDGE('',*,*,#1862,.T.);
#2140=ORIENTED_EDGE('',*,*,#431,.T.);
#2141=ORIENTED_EDGE('',*,*,#1957,.T.);
#2142=EDGE_LOOP('',(#2138,#2139,#2140,#2141));
#2143=FACE_BOUND('',#2142,.T.);
#2144=ADVANCED_FACE('F728',(#2137,#2143),#2131,.T.);
#2145=CARTESIAN_POINT('',(-9.5,0.,0.));
#2146=DIRECTION('',(-1.,0.,0.));
#2147=DIRECTION('',(0.,0.,-1.));
#2148=AXIS2_PLACEMENT_3D('',#2145,#2146,#2147);
#2149=SPHERICAL_SURFACE('',#2148,2.95);
#2150=ORIENTED_EDGE('',*,*,#243,.T.);
#2151=ORIENTED_EDGE('',*,*,#1295,.T.);
#2152=ORIENTED_EDGE('',*,*,#360,.T.);
#2153=ORIENTED_EDGE('',*,*,#1424,.T.);
#2154=EDGE_LOOP('',(#2150,#2151,#2152,#2153));
#2155=FACE_BOUND('',#2154,.T.);
#2156=ORIENTED_EDGE('',*,*,#186,.T.);
#2157=ORIENTED_EDGE('',*,*,#1872,.T.);
#2158=ORIENTED_EDGE('',*,*,#289,.T.);
#2159=ORIENTED_EDGE('',*,*,#1947,.T.);
#2160=EDGE_LOOP('',(#2156,#2157,#2158,#2159));
#2161=FACE_BOUND('',#2160,.T.);
#2162=ADVANCED_FACE('F668',(#2155,#2161),#2149,.T.);
#2163=CARTESIAN_POINT('',(-6.71751442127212,6.71751442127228,0.));
#2164=DIRECTION('',(-0.707106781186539,0.707106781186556,0.));
#2165=DIRECTION('',(0.,0.,-1.));
#2166=AXIS2_PLACEMENT_3D('',#2163,#2164,#2165);
#2167=SPHERICAL_SURFACE('',#2166,2.95);
#2168=ORIENTED_EDGE('',*,*,#56,.T.);
#2169=ORIENTED_EDGE('',*,*,#1230,.T.);
#2170=ORIENTED_EDGE('',*,*,#218,.T.);
#2171=ORIENTED_EDGE('',*,*,#1380,.T.);
#2172=EDGE_LOOP('',(#2168,#2169,#2170,#2171));
#2173=FACE_BOUND('',#2172,.T.);
#2174=ORIENTED_EDGE('',*,*,#1916,.T.);
#2175=ORIENTED_EDGE('',*,*,#1809,.T.);
#2176=ORIENTED_EDGE('',*,*,#142,.T.);
#2177=ORIENTED_EDGE('',*,*,#1937,.T.);
#2178=EDGE_LOOP('',(#2174,#2175,#2176,#2177));
#2179=FACE_BOUND('',#2178,.T.);
#2180=ADVANCED_FACE('F243',(#2173,#2179),#2167,.T.);
#2181=CLOSED_SHELL('',(#90,#190,#247,#332,#389,#474,#531,#616,#673,#758,#815,#900,#957,#1042,
#1188,#1216,#1302,#1332,#1661,#1681,#1709,#1737,#1765,#1793,#1879,#1923,#2006,#2018,#2030,#2042,
#2054,#2072,#2090,#2108,#2126,#2144,#2162,#2180));
#2182=MANIFOLD_SOLID_BREP('B2',#2181);
#2183=ADVANCED_BREP_SHAPE_REPRESENTATION('',(#18,#2182),#14);
#2184=SHAPE_DEFINITION_REPRESENTATION(#9,#2183);
ENDSEC;
END-ISO-10303-21;
